VERSION 5.7 ;
NAMESCASESENSITIVE ON ;
BUSBITCHARS "[]" ;
DIVIDERCHAR "|" ;

PROPERTYDEFINITIONS
    LAYER LEF58_TYPE STRING ;
END PROPERTYDEFINITIONS


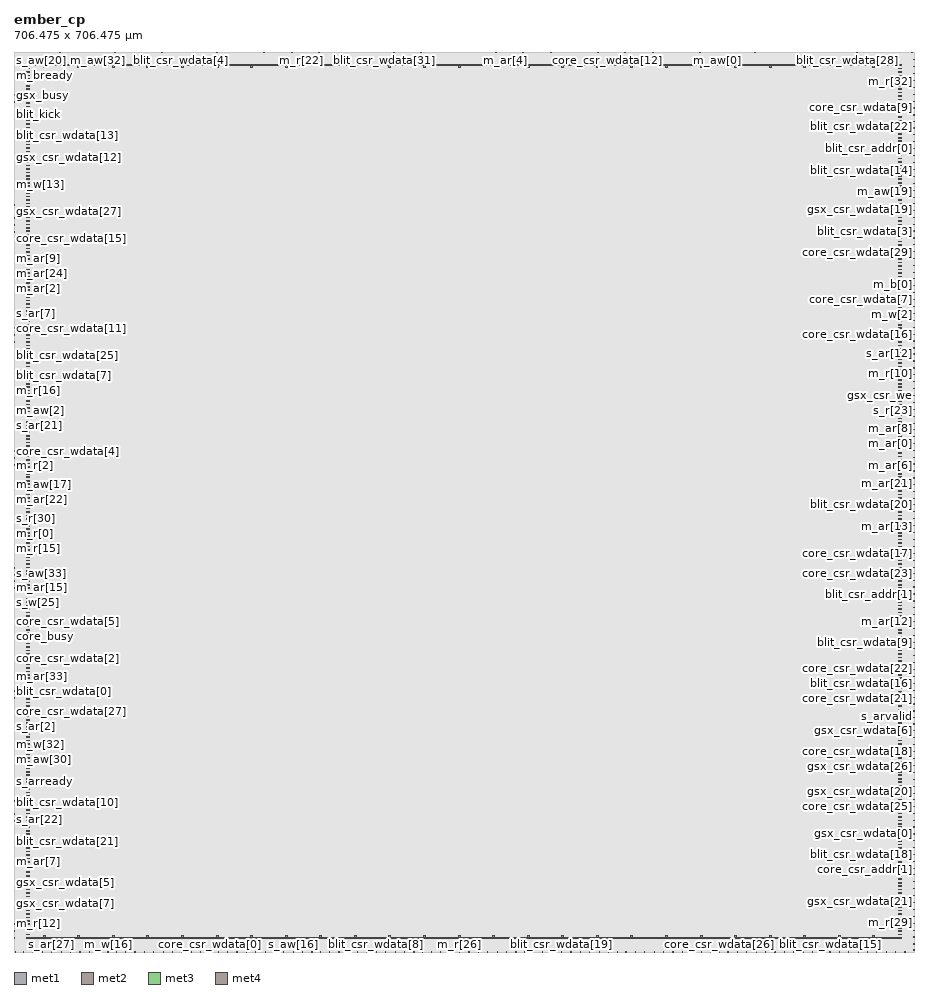
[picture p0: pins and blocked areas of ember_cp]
MACRO ember_cp
    CLASS BLOCK ;
    SIZE 706.475 BY 706.475 ;
    SYMMETRY Y ;
    PIN blit_busy
        DIRECTION INPUT ; 
        USE SIGNAL ; 
        PORT
            LAYER met1 ;
              RECT  705.88 420.34 706.475 420.48 ;
        END
    END blit_busy
    PIN blit_csr_addr[0]
        DIRECTION OUTPUT ; 
        USE SIGNAL ; 
        PORT
            LAYER met1 ;
              RECT  705.88 630.46 706.475 630.6 ;
        END
    END blit_csr_addr[0]
    PIN blit_csr_addr[1]
        DIRECTION OUTPUT ; 
        USE SIGNAL ; 
        PORT
            LAYER met1 ;
              RECT  705.88 280.94 706.475 281.08 ;
        END
    END blit_csr_addr[1]
    PIN blit_csr_wdata[0]
        DIRECTION OUTPUT ; 
        USE SIGNAL ; 
        PORT
            LAYER met1 ;
              RECT  0 204.78 0.595 204.92 ;
        END
    END blit_csr_wdata[0]
    PIN blit_csr_wdata[10]
        DIRECTION OUTPUT ; 
        USE SIGNAL ; 
        PORT
            LAYER met1 ;
              RECT  0 123.86 0.595 124 ;
        END
    END blit_csr_wdata[10]
    PIN blit_csr_wdata[11]
        DIRECTION OUTPUT ; 
        USE SIGNAL ; 
        PORT
            LAYER met2 ;
              RECT  28.68 705.99 28.82 706.475 ;
        END
    END blit_csr_wdata[11]
    PIN blit_csr_wdata[12]
        DIRECTION OUTPUT ; 
        USE SIGNAL ; 
        PORT
            LAYER met2 ;
              RECT  159.32 705.99 159.46 706.475 ;
        END
    END blit_csr_wdata[12]
    PIN blit_csr_wdata[13]
        DIRECTION OUTPUT ; 
        USE SIGNAL ; 
        PORT
            LAYER met1 ;
              RECT  0 640.66 0.595 640.8 ;
        END
    END blit_csr_wdata[13]
    PIN blit_csr_wdata[14]
        DIRECTION OUTPUT ; 
        USE SIGNAL ; 
        PORT
            LAYER met1 ;
              RECT  705.88 619.58 706.475 619.72 ;
        END
    END blit_csr_wdata[14]
    PIN blit_csr_wdata[15]
        DIRECTION OUTPUT ; 
        USE SIGNAL ; 
        PORT
            LAYER met2 ;
              RECT  640.48 0 640.62 0.485 ;
        END
    END blit_csr_wdata[15]
    PIN blit_csr_wdata[16]
        DIRECTION OUTPUT ; 
        USE SIGNAL ; 
        PORT
            LAYER met1 ;
              RECT  705.88 210.9 706.475 211.04 ;
        END
    END blit_csr_wdata[16]
    PIN blit_csr_wdata[17]
        DIRECTION OUTPUT ; 
        USE SIGNAL ; 
        PORT
            LAYER met2 ;
              RECT  626.68 0 626.82 0.485 ;
        END
    END blit_csr_wdata[17]
    PIN blit_csr_wdata[18]
        DIRECTION OUTPUT ; 
        USE SIGNAL ; 
        PORT
            LAYER met1 ;
              RECT  705.88 76.26 706.475 76.4 ;
        END
    END blit_csr_wdata[18]
    PIN blit_csr_wdata[19]
        DIRECTION OUTPUT ; 
        USE SIGNAL ; 
        PORT
            LAYER met2 ;
              RECT  429.8 0 429.94 0.485 ;
        END
    END blit_csr_wdata[19]
    PIN blit_csr_wdata[1]
        DIRECTION OUTPUT ; 
        USE SIGNAL ; 
        PORT
            LAYER met2 ;
              RECT  211.76 0 211.9 0.485 ;
        END
    END blit_csr_wdata[1]
    PIN blit_csr_wdata[20]
        DIRECTION OUTPUT ; 
        USE SIGNAL ; 
        PORT
            LAYER met1 ;
              RECT  705.88 350.98 706.475 351.12 ;
        END
    END blit_csr_wdata[20]
    PIN blit_csr_wdata[21]
        DIRECTION OUTPUT ; 
        USE SIGNAL ; 
        PORT
            LAYER met1 ;
              RECT  0 86.46 0.595 86.6 ;
        END
    END blit_csr_wdata[21]
    PIN blit_csr_wdata[22]
        DIRECTION OUTPUT ; 
        USE SIGNAL ; 
        PORT
            LAYER met1 ;
              RECT  705.88 641.34 706.475 641.48 ;
        END
    END blit_csr_wdata[22]
    PIN blit_csr_wdata[23]
        DIRECTION OUTPUT ; 
        USE SIGNAL ; 
        PORT
            LAYER met1 ;
              RECT  0 511.46 0.595 511.6 ;
        END
    END blit_csr_wdata[23]
    PIN blit_csr_wdata[24]
        DIRECTION OUTPUT ; 
        USE SIGNAL ; 
        PORT
            LAYER met1 ;
              RECT  705.88 608.7 706.475 608.84 ;
        END
    END blit_csr_wdata[24]
    PIN blit_csr_wdata[25]
        DIRECTION OUTPUT ; 
        USE SIGNAL ; 
        PORT
            LAYER met1 ;
              RECT  0 467.94 0.595 468.08 ;
        END
    END blit_csr_wdata[25]
    PIN blit_csr_wdata[26]
        DIRECTION OUTPUT ; 
        USE SIGNAL ; 
        PORT
            LAYER met2 ;
              RECT  51.68 0 51.82 0.485 ;
        END
    END blit_csr_wdata[26]
    PIN blit_csr_wdata[27]
        DIRECTION OUTPUT ; 
        USE SIGNAL ; 
        PORT
            LAYER met2 ;
              RECT  306.52 0 306.66 0.485 ;
        END
    END blit_csr_wdata[27]
    PIN blit_csr_wdata[28]
        DIRECTION OUTPUT ; 
        USE SIGNAL ; 
        PORT
            LAYER met2 ;
              RECT  654.28 705.99 654.42 706.475 ;
        END
    END blit_csr_wdata[28]
    PIN blit_csr_wdata[29]
        DIRECTION OUTPUT ; 
        USE SIGNAL ; 
        PORT
            LAYER met1 ;
              RECT  0 5.54 0.595 5.68 ;
        END
    END blit_csr_wdata[29]
    PIN blit_csr_wdata[2]
        DIRECTION OUTPUT ; 
        USE SIGNAL ; 
        PORT
            LAYER met1 ;
              RECT  705.88 700.5 706.475 700.64 ;
        END
    END blit_csr_wdata[2]
    PIN blit_csr_wdata[30]
        DIRECTION OUTPUT ; 
        USE SIGNAL ; 
        PORT
            LAYER met1 ;
              RECT  0 699.82 0.595 699.96 ;
        END
    END blit_csr_wdata[30]
    PIN blit_csr_wdata[31]
        DIRECTION OUTPUT ; 
        USE SIGNAL ; 
        PORT
            LAYER met2 ;
              RECT  290.88 705.99 291.02 706.475 ;
        END
    END blit_csr_wdata[31]
    PIN blit_csr_wdata[3]
        DIRECTION OUTPUT ; 
        USE SIGNAL ; 
        PORT
            LAYER met1 ;
              RECT  705.88 565.86 706.475 566 ;
        END
    END blit_csr_wdata[3]
    PIN blit_csr_wdata[4]
        DIRECTION OUTPUT ; 
        USE SIGNAL ; 
        PORT
            LAYER met2 ;
              RECT  130.8 705.99 130.94 706.475 ;
        END
    END blit_csr_wdata[4]
    PIN blit_csr_wdata[5]
        DIRECTION OUTPUT ; 
        USE SIGNAL ; 
        PORT
            LAYER met1 ;
              RECT  0 231.98 0.595 232.12 ;
        END
    END blit_csr_wdata[5]
    PIN blit_csr_wdata[6]
        DIRECTION OUTPUT ; 
        USE SIGNAL ; 
        PORT
            LAYER met1 ;
              RECT  0 167.38 0.595 167.52 ;
        END
    END blit_csr_wdata[6]
    PIN blit_csr_wdata[7]
        DIRECTION OUTPUT ; 
        USE SIGNAL ; 
        PORT
            LAYER met1 ;
              RECT  0 452.3 0.595 452.44 ;
        END
    END blit_csr_wdata[7]
    PIN blit_csr_wdata[8]
        DIRECTION OUTPUT ; 
        USE SIGNAL ; 
        PORT
            LAYER met2 ;
              RECT  284.44 0 284.58 0.485 ;
        END
    END blit_csr_wdata[8]
    PIN blit_csr_wdata[9]
        DIRECTION OUTPUT ; 
        USE SIGNAL ; 
        PORT
            LAYER met1 ;
              RECT  705.88 242.86 706.475 243 ;
        END
    END blit_csr_wdata[9]
    PIN blit_csr_we
        DIRECTION OUTPUT ; 
        USE SIGNAL ; 
        PORT
            LAYER met1 ;
              RECT  0 21.86 0.595 22 ;
        END
    END blit_csr_we
    PIN blit_kick
        DIRECTION OUTPUT ; 
        USE SIGNAL ; 
        PORT
            LAYER met1 ;
              RECT  0 650.86 0.595 651 ;
        END
    END blit_kick
    PIN clk
        DIRECTION INPUT ; 
        USE SIGNAL ; 
        PORT
            LAYER met2 ;
              RECT  611.96 0 612.1 0.485 ;
        END
    END clk
    PIN core_busy
        DIRECTION INPUT ; 
        USE SIGNAL ; 
        PORT
            LAYER met1 ;
              RECT  0 247.62 0.595 247.76 ;
        END
    END core_busy
    PIN core_csr_addr[0]
        DIRECTION OUTPUT ; 
        USE SIGNAL ; 
        PORT
            LAYER met2 ;
              RECT  364.48 0 364.62 0.485 ;
        END
    END core_csr_addr[0]
    PIN core_csr_addr[1]
        DIRECTION OUTPUT ; 
        USE SIGNAL ; 
        PORT
            LAYER met1 ;
              RECT  705.88 70.82 706.475 70.96 ;
        END
    END core_csr_addr[1]
    PIN core_csr_wdata[0]
        DIRECTION OUTPUT ; 
        USE SIGNAL ; 
        PORT
            LAYER met2 ;
              RECT  153.8 0 153.94 0.485 ;
        END
    END core_csr_wdata[0]
    PIN core_csr_wdata[10]
        DIRECTION OUTPUT ; 
        USE SIGNAL ; 
        PORT
            LAYER met2 ;
              RECT  124.36 0 124.5 0.485 ;
        END
    END core_csr_wdata[10]
    PIN core_csr_wdata[11]
        DIRECTION OUTPUT ; 
        USE SIGNAL ; 
        PORT
            LAYER met1 ;
              RECT  0 489.7 0.595 489.84 ;
        END
    END core_csr_wdata[11]
    PIN core_csr_wdata[12]
        DIRECTION OUTPUT ; 
        USE SIGNAL ; 
        PORT
            LAYER met2 ;
              RECT  465.68 705.99 465.82 706.475 ;
        END
    END core_csr_wdata[12]
    PIN core_csr_wdata[13]
        DIRECTION OUTPUT ; 
        USE SIGNAL ; 
        PORT
            LAYER met2 ;
              RECT  450.96 705.99 451.1 706.475 ;
        END
    END core_csr_wdata[13]
    PIN core_csr_wdata[14]
        DIRECTION OUTPUT ; 
        USE SIGNAL ; 
        PORT
            LAYER met1 ;
              RECT  0 457.74 0.595 457.88 ;
        END
    END core_csr_wdata[14]
    PIN core_csr_wdata[15]
        DIRECTION OUTPUT ; 
        USE SIGNAL ; 
        PORT
            LAYER met1 ;
              RECT  0 559.74 0.595 559.88 ;
        END
    END core_csr_wdata[15]
    PIN core_csr_wdata[16]
        DIRECTION OUTPUT ; 
        USE SIGNAL ; 
        PORT
            LAYER met1 ;
              RECT  705.88 484.94 706.475 485.08 ;
        END
    END core_csr_wdata[16]
    PIN core_csr_wdata[17]
        DIRECTION OUTPUT ; 
        USE SIGNAL ; 
        PORT
            LAYER met1 ;
              RECT  705.88 312.9 706.475 313.04 ;
        END
    END core_csr_wdata[17]
    PIN core_csr_wdata[18]
        DIRECTION OUTPUT ; 
        USE SIGNAL ; 
        PORT
            LAYER met1 ;
              RECT  705.88 157.18 706.475 157.32 ;
        END
    END core_csr_wdata[18]
    PIN core_csr_wdata[19]
        DIRECTION OUTPUT ; 
        USE SIGNAL ; 
        PORT
            LAYER met2 ;
              RECT  117 0 117.14 0.485 ;
        END
    END core_csr_wdata[19]
    PIN core_csr_wdata[1]
        DIRECTION OUTPUT ; 
        USE SIGNAL ; 
        PORT
            LAYER met2 ;
              RECT  232 705.99 232.14 706.475 ;
        END
    END core_csr_wdata[1]
    PIN core_csr_wdata[20]
        DIRECTION OUTPUT ; 
        USE SIGNAL ; 
        PORT
            LAYER met1 ;
              RECT  0 661.74 0.595 661.88 ;
        END
    END core_csr_wdata[20]
    PIN core_csr_wdata[21]
        DIRECTION OUTPUT ; 
        USE SIGNAL ; 
        PORT
            LAYER met1 ;
              RECT  705.88 205.46 706.475 205.6 ;
        END
    END core_csr_wdata[21]
    PIN core_csr_wdata[22]
        DIRECTION OUTPUT ; 
        USE SIGNAL ; 
        PORT
            LAYER met1 ;
              RECT  705.88 216.34 706.475 216.48 ;
        END
    END core_csr_wdata[22]
    PIN core_csr_wdata[23]
        DIRECTION OUTPUT ; 
        USE SIGNAL ; 
        PORT
            LAYER met1 ;
              RECT  705.88 297.26 706.475 297.4 ;
        END
    END core_csr_wdata[23]
    PIN core_csr_wdata[24]
        DIRECTION OUTPUT ; 
        USE SIGNAL ; 
        PORT
            LAYER met1 ;
              RECT  705.88 1.46 706.475 1.6 ;
        END
    END core_csr_wdata[24]
    PIN core_csr_wdata[25]
        DIRECTION OUTPUT ; 
        USE SIGNAL ; 
        PORT
            LAYER met1 ;
              RECT  705.88 114.34 706.475 114.48 ;
        END
    END core_csr_wdata[25]
    PIN core_csr_wdata[26]
        DIRECTION OUTPUT ; 
        USE SIGNAL ; 
        PORT
            LAYER met2 ;
              RECT  554 0 554.14 0.485 ;
        END
    END core_csr_wdata[26]
    PIN core_csr_wdata[27]
        DIRECTION OUTPUT ; 
        USE SIGNAL ; 
        PORT
            LAYER met1 ;
              RECT  0 188.46 0.595 188.6 ;
        END
    END core_csr_wdata[27]
    PIN core_csr_wdata[28]
        DIRECTION OUTPUT ; 
        USE SIGNAL ; 
        PORT
            LAYER met2 ;
              RECT  102.28 0 102.42 0.485 ;
        END
    END core_csr_wdata[28]
    PIN core_csr_wdata[29]
        DIRECTION OUTPUT ; 
        USE SIGNAL ; 
        PORT
            LAYER met1 ;
              RECT  705.88 554.98 706.475 555.12 ;
        END
    END core_csr_wdata[29]
    PIN core_csr_wdata[2]
        DIRECTION OUTPUT ; 
        USE SIGNAL ; 
        PORT
            LAYER met1 ;
              RECT  0 236.74 0.595 236.88 ;
        END
    END core_csr_wdata[2]
    PIN core_csr_wdata[30]
        DIRECTION OUTPUT ; 
        USE SIGNAL ; 
        PORT
            LAYER met2 ;
              RECT  319.4 705.99 319.54 706.475 ;
        END
    END core_csr_wdata[30]
    PIN core_csr_wdata[31]
        DIRECTION OUTPUT ; 
        USE SIGNAL ; 
        PORT
            LAYER met1 ;
              RECT  705.88 189.14 706.475 189.28 ;
        END
    END core_csr_wdata[31]
    PIN core_csr_wdata[3]
        DIRECTION OUTPUT ; 
        USE SIGNAL ; 
        PORT
            LAYER met1 ;
              RECT  0 10.98 0.595 11.12 ;
        END
    END core_csr_wdata[3]
    PIN core_csr_wdata[4]
        DIRECTION OUTPUT ; 
        USE SIGNAL ; 
        PORT
            LAYER met1 ;
              RECT  0 393.14 0.595 393.28 ;
        END
    END core_csr_wdata[4]
    PIN core_csr_wdata[5]
        DIRECTION OUTPUT ; 
        USE SIGNAL ; 
        PORT
            LAYER met1 ;
              RECT  0 253.06 0.595 253.2 ;
        END
    END core_csr_wdata[5]
    PIN core_csr_wdata[6]
        DIRECTION OUTPUT ; 
        USE SIGNAL ; 
        PORT
            LAYER met2 ;
              RECT  277.08 0 277.22 0.485 ;
        END
    END core_csr_wdata[6]
    PIN core_csr_wdata[7]
        DIRECTION OUTPUT ; 
        USE SIGNAL ; 
        PORT
            LAYER met1 ;
              RECT  705.88 512.14 706.475 512.28 ;
        END
    END core_csr_wdata[7]
    PIN core_csr_wdata[8]
        DIRECTION OUTPUT ; 
        USE SIGNAL ; 
        PORT
            LAYER met2 ;
              RECT  639.56 705.99 639.7 706.475 ;
        END
    END core_csr_wdata[8]
    PIN core_csr_wdata[9]
        DIRECTION OUTPUT ; 
        USE SIGNAL ; 
        PORT
            LAYER met1 ;
              RECT  705.88 656.98 706.475 657.12 ;
        END
    END core_csr_wdata[9]
    PIN core_csr_we
        DIRECTION OUTPUT ; 
        USE SIGNAL ; 
        PORT
            LAYER met2 ;
              RECT  596.32 705.99 596.46 706.475 ;
        END
    END core_csr_we
    PIN core_kick
        DIRECTION OUTPUT ; 
        USE SIGNAL ; 
        PORT
            LAYER met1 ;
              RECT  705.88 227.22 706.475 227.36 ;
        END
    END core_kick
    PIN gsx_busy
        DIRECTION INPUT ; 
        USE SIGNAL ; 
        PORT
            LAYER met1 ;
              RECT  0 672.62 0.595 672.76 ;
        END
    END gsx_busy
    PIN gsx_csr_addr[0]
        DIRECTION OUTPUT ; 
        USE SIGNAL ; 
        PORT
            LAYER met2 ;
              RECT  379.2 0 379.34 0.485 ;
        END
    END gsx_csr_addr[0]
    PIN gsx_csr_addr[1]
        DIRECTION OUTPUT ; 
        USE SIGNAL ; 
        PORT
            LAYER met1 ;
              RECT  705.88 60.62 706.475 60.76 ;
        END
    END gsx_csr_addr[1]
    PIN gsx_csr_wdata[0]
        DIRECTION OUTPUT ; 
        USE SIGNAL ; 
        PORT
            LAYER met1 ;
              RECT  705.88 92.58 706.475 92.72 ;
        END
    END gsx_csr_wdata[0]
    PIN gsx_csr_wdata[10]
        DIRECTION OUTPUT ; 
        USE SIGNAL ; 
        PORT
            LAYER met2 ;
              RECT  22.24 0 22.38 0.485 ;
        END
    END gsx_csr_wdata[10]
    PIN gsx_csr_wdata[11]
        DIRECTION OUTPUT ; 
        USE SIGNAL ; 
        PORT
            LAYER met1 ;
              RECT  0 172.82 0.595 172.96 ;
        END
    END gsx_csr_wdata[11]
    PIN gsx_csr_wdata[12]
        DIRECTION OUTPUT ; 
        USE SIGNAL ; 
        PORT
            LAYER met1 ;
              RECT  0 629.78 0.595 629.92 ;
        END
    END gsx_csr_wdata[12]
    PIN gsx_csr_wdata[13]
        DIRECTION OUTPUT ; 
        USE SIGNAL ; 
        PORT
            LAYER met2 ;
              RECT  574.24 705.99 574.38 706.475 ;
        END
    END gsx_csr_wdata[13]
    PIN gsx_csr_wdata[14]
        DIRECTION OUTPUT ; 
        USE SIGNAL ; 
        PORT
            LAYER met2 ;
              RECT  312.04 705.99 312.18 706.475 ;
        END
    END gsx_csr_wdata[14]
    PIN gsx_csr_wdata[15]
        DIRECTION OUTPUT ; 
        USE SIGNAL ; 
        PORT
            LAYER met2 ;
              RECT  669 705.99 669.14 706.475 ;
        END
    END gsx_csr_wdata[15]
    PIN gsx_csr_wdata[16]
        DIRECTION OUTPUT ; 
        USE SIGNAL ; 
        PORT
            LAYER met2 ;
              RECT  422.44 0 422.58 0.485 ;
        END
    END gsx_csr_wdata[16]
    PIN gsx_csr_wdata[17]
        DIRECTION OUTPUT ; 
        USE SIGNAL ; 
        PORT
            LAYER met1 ;
              RECT  0 226.54 0.595 226.68 ;
        END
    END gsx_csr_wdata[17]
    PIN gsx_csr_wdata[18]
        DIRECTION OUTPUT ; 
        USE SIGNAL ; 
        PORT
            LAYER met2 ;
              RECT  181.4 705.99 181.54 706.475 ;
        END
    END gsx_csr_wdata[18]
    PIN gsx_csr_wdata[19]
        DIRECTION OUTPUT ; 
        USE SIGNAL ; 
        PORT
            LAYER met1 ;
              RECT  705.88 576.74 706.475 576.88 ;
        END
    END gsx_csr_wdata[19]
    PIN gsx_csr_wdata[1]
        DIRECTION OUTPUT ; 
        USE SIGNAL ; 
        PORT
            LAYER met2 ;
              RECT  196.12 705.99 196.26 706.475 ;
        END
    END gsx_csr_wdata[1]
    PIN gsx_csr_wdata[20]
        DIRECTION OUTPUT ; 
        USE SIGNAL ; 
        PORT
            LAYER met1 ;
              RECT  705.88 119.78 706.475 119.92 ;
        END
    END gsx_csr_wdata[20]
    PIN gsx_csr_wdata[21]
        DIRECTION OUTPUT ; 
        USE SIGNAL ; 
        PORT
            LAYER met1 ;
              RECT  705.88 33.42 706.475 33.56 ;
        END
    END gsx_csr_wdata[21]
    PIN gsx_csr_wdata[22]
        DIRECTION OUTPUT ; 
        USE SIGNAL ; 
        PORT
            LAYER met2 ;
              RECT  400.36 0 400.5 0.485 ;
        END
    END gsx_csr_wdata[22]
    PIN gsx_csr_wdata[23]
        DIRECTION OUTPUT ; 
        USE SIGNAL ; 
        PORT
            LAYER met1 ;
              RECT  705.88 614.14 706.475 614.28 ;
        END
    END gsx_csr_wdata[23]
    PIN gsx_csr_wdata[24]
        DIRECTION OUTPUT ; 
        USE SIGNAL ; 
        PORT
            LAYER met1 ;
              RECT  705.88 323.78 706.475 323.92 ;
        END
    END gsx_csr_wdata[24]
    PIN gsx_csr_wdata[25]
        DIRECTION OUTPUT ; 
        USE SIGNAL ; 
        PORT
            LAYER met2 ;
              RECT  72.84 705.99 72.98 706.475 ;
        END
    END gsx_csr_wdata[25]
    PIN gsx_csr_wdata[26]
        DIRECTION OUTPUT ; 
        USE SIGNAL ; 
        PORT
            LAYER met1 ;
              RECT  705.88 151.74 706.475 151.88 ;
        END
    END gsx_csr_wdata[26]
    PIN gsx_csr_wdata[27]
        DIRECTION OUTPUT ; 
        USE SIGNAL ; 
        PORT
            LAYER met1 ;
              RECT  0 581.5 0.595 581.64 ;
        END
    END gsx_csr_wdata[27]
    PIN gsx_csr_wdata[28]
        DIRECTION OUTPUT ; 
        USE SIGNAL ; 
        PORT
            LAYER met1 ;
              RECT  0 586.26 0.595 586.4 ;
        END
    END gsx_csr_wdata[28]
    PIN gsx_csr_wdata[29]
        DIRECTION OUTPUT ; 
        USE SIGNAL ; 
        PORT
            LAYER met1 ;
              RECT  705.88 98.02 706.475 98.16 ;
        END
    END gsx_csr_wdata[29]
    PIN gsx_csr_wdata[2]
        DIRECTION OUTPUT ; 
        USE SIGNAL ; 
        PORT
            LAYER met2 ;
              RECT  356.2 705.99 356.34 706.475 ;
        END
    END gsx_csr_wdata[2]
    PIN gsx_csr_wdata[30]
        DIRECTION OUTPUT ; 
        USE SIGNAL ; 
        PORT
            LAYER met2 ;
              RECT  94.92 0 95.06 0.485 ;
        END
    END gsx_csr_wdata[30]
    PIN gsx_csr_wdata[31]
        DIRECTION OUTPUT ; 
        USE SIGNAL ; 
        PORT
            LAYER met1 ;
              RECT  705.88 140.86 706.475 141 ;
        END
    END gsx_csr_wdata[31]
    PIN gsx_csr_wdata[3]
        DIRECTION OUTPUT ; 
        USE SIGNAL ; 
        PORT
            LAYER met2 ;
              RECT  79.28 705.99 79.42 706.475 ;
        END
    END gsx_csr_wdata[3]
    PIN gsx_csr_wdata[4]
        DIRECTION OUTPUT ; 
        USE SIGNAL ; 
        PORT
            LAYER met1 ;
              RECT  0 118.42 0.595 118.56 ;
        END
    END gsx_csr_wdata[4]
    PIN gsx_csr_wdata[5]
        DIRECTION OUTPUT ; 
        USE SIGNAL ; 
        PORT
            LAYER met1 ;
              RECT  0 54.5 0.595 54.64 ;
        END
    END gsx_csr_wdata[5]
    PIN gsx_csr_wdata[6]
        DIRECTION OUTPUT ; 
        USE SIGNAL ; 
        PORT
            LAYER met1 ;
              RECT  705.88 173.5 706.475 173.64 ;
        END
    END gsx_csr_wdata[6]
    PIN gsx_csr_wdata[7]
        DIRECTION OUTPUT ; 
        USE SIGNAL ; 
        PORT
            LAYER met1 ;
              RECT  0 38.18 0.595 38.32 ;
        END
    END gsx_csr_wdata[7]
    PIN gsx_csr_wdata[8]
        DIRECTION OUTPUT ; 
        USE SIGNAL ; 
        PORT
            LAYER met1 ;
              RECT  0 161.94 0.595 162.08 ;
        END
    END gsx_csr_wdata[8]
    PIN gsx_csr_wdata[9]
        DIRECTION OUTPUT ; 
        USE SIGNAL ; 
        PORT
            LAYER met1 ;
              RECT  0 59.26 0.595 59.4 ;
        END
    END gsx_csr_wdata[9]
    PIN gsx_csr_we
        DIRECTION OUTPUT ; 
        USE SIGNAL ; 
        PORT
            LAYER met1 ;
              RECT  705.88 436.66 706.475 436.8 ;
        END
    END gsx_csr_we
    PIN gsx_kick
        DIRECTION OUTPUT ; 
        USE SIGNAL ; 
        PORT
            LAYER met2 ;
              RECT  246.72 705.99 246.86 706.475 ;
        END
    END gsx_kick
    PIN m_ar[0]
        DIRECTION OUTPUT ; 
        USE SIGNAL ; 
        PORT
            LAYER met1 ;
              RECT  705.88 399.26 706.475 399.4 ;
        END
    END m_ar[0]
    PIN m_ar[10]
        DIRECTION OUTPUT ; 
        USE SIGNAL ; 
        PORT
            LAYER met2 ;
              RECT  255 0 255.14 0.485 ;
        END
    END m_ar[10]
    PIN m_ar[11]
        DIRECTION OUTPUT ; 
        USE SIGNAL ; 
        PORT
            LAYER met2 ;
              RECT  523.64 705.99 523.78 706.475 ;
        END
    END m_ar[11]
    PIN m_ar[12]
        DIRECTION OUTPUT ; 
        USE SIGNAL ; 
        PORT
            LAYER met1 ;
              RECT  705.88 259.18 706.475 259.32 ;
        END
    END m_ar[12]
    PIN m_ar[13]
        DIRECTION OUTPUT ; 
        USE SIGNAL ; 
        PORT
            LAYER met1 ;
              RECT  705.88 340.1 706.475 340.24 ;
        END
    END m_ar[13]
    PIN m_ar[14]
        DIRECTION OUTPUT ; 
        USE SIGNAL ; 
        PORT
            LAYER met2 ;
              RECT  145.52 705.99 145.66 706.475 ;
        END
    END m_ar[14]
    PIN m_ar[15]
        DIRECTION OUTPUT ; 
        USE SIGNAL ; 
        PORT
            LAYER met1 ;
              RECT  0 285.7 0.595 285.84 ;
        END
    END m_ar[15]
    PIN m_ar[16]
        DIRECTION OUTPUT ; 
        USE SIGNAL ; 
        PORT
            LAYER met2 ;
              RECT  174.04 705.99 174.18 706.475 ;
        END
    END m_ar[16]
    PIN m_ar[17]
        DIRECTION OUTPUT ; 
        USE SIGNAL ; 
        PORT
            LAYER met1 ;
              RECT  705.88 38.86 706.475 39 ;
        END
    END m_ar[17]
    PIN m_ar[18]
        DIRECTION OUTPUT ; 
        USE SIGNAL ; 
        PORT
            LAYER met1 ;
              RECT  0 269.38 0.595 269.52 ;
        END
    END m_ar[18]
    PIN m_ar[19]
        DIRECTION OUTPUT ; 
        USE SIGNAL ; 
        PORT
            LAYER met1 ;
              RECT  705.88 6.22 706.475 6.36 ;
        END
    END m_ar[19]
    PIN m_ar[1]
        DIRECTION OUTPUT ; 
        USE SIGNAL ; 
        PORT
            LAYER met1 ;
              RECT  0 306.78 0.595 306.92 ;
        END
    END m_ar[1]
    PIN m_ar[20]
        DIRECTION OUTPUT ; 
        USE SIGNAL ; 
        PORT
            LAYER met2 ;
              RECT  625.76 705.99 625.9 706.475 ;
        END
    END m_ar[20]
    PIN m_ar[21]
        DIRECTION OUTPUT ; 
        USE SIGNAL ; 
        PORT
            LAYER met1 ;
              RECT  705.88 361.18 706.475 361.32 ;
        END
    END m_ar[21]
    PIN m_ar[22]
        DIRECTION OUTPUT ; 
        USE SIGNAL ; 
        PORT
            LAYER met1 ;
              RECT  0 355.06 0.595 355.2 ;
        END
    END m_ar[22]
    PIN m_ar[23]
        DIRECTION OUTPUT ; 
        USE SIGNAL ; 
        PORT
            LAYER met2 ;
              RECT  218.2 705.99 218.34 706.475 ;
        END
    END m_ar[23]
    PIN m_ar[24]
        DIRECTION OUTPUT ; 
        USE SIGNAL ; 
        PORT
            LAYER met1 ;
              RECT  0 532.54 0.595 532.68 ;
        END
    END m_ar[24]
    PIN m_ar[25]
        DIRECTION OUTPUT ; 
        USE SIGNAL ; 
        PORT
            LAYER met2 ;
              RECT  399.44 705.99 399.58 706.475 ;
        END
    END m_ar[25]
    PIN m_ar[26]
        DIRECTION OUTPUT ; 
        USE SIGNAL ; 
        PORT
            LAYER met1 ;
              RECT  705.88 334.66 706.475 334.8 ;
        END
    END m_ar[26]
    PIN m_ar[27]
        DIRECTION OUTPUT ; 
        USE SIGNAL ; 
        PORT
            LAYER met1 ;
              RECT  705.88 11.66 706.475 11.8 ;
        END
    END m_ar[27]
    PIN m_ar[28]
        DIRECTION OUTPUT ; 
        USE SIGNAL ; 
        PORT
            LAYER met1 ;
              RECT  0 635.22 0.595 635.36 ;
        END
    END m_ar[28]
    PIN m_ar[29]
        DIRECTION OUTPUT ; 
        USE SIGNAL ; 
        PORT
            LAYER met2 ;
              RECT  479.48 705.99 479.62 706.475 ;
        END
    END m_ar[29]
    PIN m_ar[2]
        DIRECTION OUTPUT ; 
        USE SIGNAL ; 
        PORT
            LAYER met1 ;
              RECT  0 527.1 0.595 527.24 ;
        END
    END m_ar[2]
    PIN m_ar[30]
        DIRECTION OUTPUT ; 
        USE SIGNAL ; 
        PORT
            LAYER met2 ;
              RECT  305.6 705.99 305.74 706.475 ;
        END
    END m_ar[30]
    PIN m_ar[31]
        DIRECTION OUTPUT ; 
        USE SIGNAL ; 
        PORT
            LAYER met1 ;
              RECT  0 350.3 0.595 350.44 ;
        END
    END m_ar[31]
    PIN m_ar[32]
        DIRECTION OUTPUT ; 
        USE SIGNAL ; 
        PORT
            LAYER met1 ;
              RECT  705.88 501.26 706.475 501.4 ;
        END
    END m_ar[32]
    PIN m_ar[33]
        DIRECTION OUTPUT ; 
        USE SIGNAL ; 
        PORT
            LAYER met1 ;
              RECT  0 210.22 0.595 210.36 ;
        END
    END m_ar[33]
    PIN m_ar[34]
        DIRECTION OUTPUT ; 
        USE SIGNAL ; 
        PORT
            LAYER met2 ;
              RECT  619.32 0 619.46 0.485 ;
        END
    END m_ar[34]
    PIN m_ar[3]
        DIRECTION OUTPUT ; 
        USE SIGNAL ; 
        PORT
            LAYER met2 ;
              RECT  116.08 705.99 116.22 706.475 ;
        END
    END m_ar[3]
    PIN m_ar[4]
        DIRECTION OUTPUT ; 
        USE SIGNAL ; 
        PORT
            LAYER met2 ;
              RECT  385.64 705.99 385.78 706.475 ;
        END
    END m_ar[4]
    PIN m_ar[5]
        DIRECTION OUTPUT ; 
        USE SIGNAL ; 
        PORT
            LAYER met2 ;
              RECT  138.16 705.99 138.3 706.475 ;
        END
    END m_ar[5]
    PIN m_ar[6]
        DIRECTION OUTPUT ; 
        USE SIGNAL ; 
        PORT
            LAYER met1 ;
              RECT  705.88 388.38 706.475 388.52 ;
        END
    END m_ar[6]
    PIN m_ar[7]
        DIRECTION OUTPUT ; 
        USE SIGNAL ; 
        PORT
            LAYER met1 ;
              RECT  0 64.7 0.595 64.84 ;
        END
    END m_ar[7]
    PIN m_ar[8]
        DIRECTION OUTPUT ; 
        USE SIGNAL ; 
        PORT
            LAYER met1 ;
              RECT  705.88 404.7 706.475 404.84 ;
        END
    END m_ar[8]
    PIN m_ar[9]
        DIRECTION OUTPUT ; 
        USE SIGNAL ; 
        PORT
            LAYER met1 ;
              RECT  0 537.98 0.595 538.12 ;
        END
    END m_ar[9]
    PIN m_arready
        DIRECTION INPUT ; 
        USE SIGNAL ; 
        PORT
            LAYER met2 ;
              RECT  473.96 0 474.1 0.485 ;
        END
    END m_arready
    PIN m_arvalid
        DIRECTION OUTPUT ; 
        USE SIGNAL ; 
        PORT
            LAYER met2 ;
              RECT  531.92 0 532.06 0.485 ;
        END
    END m_arvalid
    PIN m_aw[0]
        DIRECTION OUTPUT ; 
        USE SIGNAL ; 
        PORT
            LAYER met2 ;
              RECT  552.16 705.99 552.3 706.475 ;
        END
    END m_aw[0]
    PIN m_aw[10]
        DIRECTION OUTPUT ; 
        USE SIGNAL ; 
        PORT
            LAYER met1 ;
              RECT  705.88 684.18 706.475 684.32 ;
        END
    END m_aw[10]
    PIN m_aw[11]
        DIRECTION OUTPUT ; 
        USE SIGNAL ; 
        PORT
            LAYER met2 ;
              RECT  21.32 705.99 21.46 706.475 ;
        END
    END m_aw[11]
    PIN m_aw[12]
        DIRECTION OUTPUT ; 
        USE SIGNAL ; 
        PORT
            LAYER met2 ;
              RECT  291.8 0 291.94 0.485 ;
        END
    END m_aw[12]
    PIN m_aw[13]
        DIRECTION OUTPUT ; 
        USE SIGNAL ; 
        PORT
            LAYER met2 ;
              RECT  437.16 0 437.3 0.485 ;
        END
    END m_aw[13]
    PIN m_aw[14]
        DIRECTION OUTPUT ; 
        USE SIGNAL ; 
        PORT
            LAYER met2 ;
              RECT  226.48 0 226.62 0.485 ;
        END
    END m_aw[14]
    PIN m_aw[15]
        DIRECTION OUTPUT ; 
        USE SIGNAL ; 
        PORT
            LAYER met1 ;
              RECT  0 624.34 0.595 624.48 ;
        END
    END m_aw[15]
    PIN m_aw[16]
        DIRECTION OUTPUT ; 
        USE SIGNAL ; 
        PORT
            LAYER met2 ;
              RECT  335.04 0 335.18 0.485 ;
        END
    END m_aw[16]
    PIN m_aw[17]
        DIRECTION OUTPUT ; 
        USE SIGNAL ; 
        PORT
            LAYER met1 ;
              RECT  0 360.5 0.595 360.64 ;
        END
    END m_aw[17]
    PIN m_aw[18]
        DIRECTION OUTPUT ; 
        USE SIGNAL ; 
        PORT
            LAYER met2 ;
              RECT  501.56 705.99 501.7 706.475 ;
        END
    END m_aw[18]
    PIN m_aw[19]
        DIRECTION OUTPUT ; 
        USE SIGNAL ; 
        PORT
            LAYER met1 ;
              RECT  705.88 603.26 706.475 603.4 ;
        END
    END m_aw[19]
    PIN m_aw[1]
        DIRECTION OUTPUT ; 
        USE SIGNAL ; 
        PORT
            LAYER met1 ;
              RECT  705.88 194.58 706.475 194.72 ;
        END
    END m_aw[1]
    PIN m_aw[20]
        DIRECTION OUTPUT ; 
        USE SIGNAL ; 
        PORT
            LAYER met2 ;
              RECT  313.88 0 314.02 0.485 ;
        END
    END m_aw[20]
    PIN m_aw[21]
        DIRECTION OUTPUT ; 
        USE SIGNAL ; 
        PORT
            LAYER met2 ;
              RECT  684.64 0 684.78 0.485 ;
        END
    END m_aw[21]
    PIN m_aw[22]
        DIRECTION OUTPUT ; 
        USE SIGNAL ; 
        PORT
            LAYER met2 ;
              RECT  589.88 0 590.02 0.485 ;
        END
    END m_aw[22]
    PIN m_aw[23]
        DIRECTION OUTPUT ; 
        USE SIGNAL ; 
        PORT
            LAYER met1 ;
              RECT  705.88 44.3 706.475 44.44 ;
        END
    END m_aw[23]
    PIN m_aw[24]
        DIRECTION OUTPUT ; 
        USE SIGNAL ; 
        PORT
            LAYER met1 ;
              RECT  705.88 22.54 706.475 22.68 ;
        END
    END m_aw[24]
    PIN m_aw[25]
        DIRECTION OUTPUT ; 
        USE SIGNAL ; 
        PORT
            LAYER met2 ;
              RECT  233.84 0 233.98 0.485 ;
        END
    END m_aw[25]
    PIN m_aw[26]
        DIRECTION OUTPUT ; 
        USE SIGNAL ; 
        PORT
            LAYER met2 ;
              RECT  101.36 705.99 101.5 706.475 ;
        END
    END m_aw[26]
    PIN m_aw[27]
        DIRECTION OUTPUT ; 
        USE SIGNAL ; 
        PORT
            LAYER met2 ;
              RECT  581.6 705.99 581.74 706.475 ;
        END
    END m_aw[27]
    PIN m_aw[28]
        DIRECTION OUTPUT ; 
        USE SIGNAL ; 
        PORT
            LAYER met2 ;
              RECT  334.12 705.99 334.26 706.475 ;
        END
    END m_aw[28]
    PIN m_aw[29]
        DIRECTION OUTPUT ; 
        USE SIGNAL ; 
        PORT
            LAYER met2 ;
              RECT  517.2 0 517.34 0.485 ;
        END
    END m_aw[29]
    PIN m_aw[2]
        DIRECTION OUTPUT ; 
        USE SIGNAL ; 
        PORT
            LAYER met1 ;
              RECT  0 425.1 0.595 425.24 ;
        END
    END m_aw[2]
    PIN m_aw[30]
        DIRECTION OUTPUT ; 
        USE SIGNAL ; 
        PORT
            LAYER met1 ;
              RECT  0 151.06 0.595 151.2 ;
        END
    END m_aw[30]
    PIN m_aw[31]
        DIRECTION OUTPUT ; 
        USE SIGNAL ; 
        PORT
            LAYER met1 ;
              RECT  0 408.78 0.595 408.92 ;
        END
    END m_aw[31]
    PIN m_aw[32]
        DIRECTION OUTPUT ; 
        USE SIGNAL ; 
        PORT
            LAYER met2 ;
              RECT  65.48 705.99 65.62 706.475 ;
        END
    END m_aw[32]
    PIN m_aw[33]
        DIRECTION OUTPUT ; 
        USE SIGNAL ; 
        PORT
            LAYER met2 ;
              RECT  342.4 0 342.54 0.485 ;
        END
    END m_aw[33]
    PIN m_aw[34]
        DIRECTION OUTPUT ; 
        USE SIGNAL ; 
        PORT
            LAYER met2 ;
              RECT  407.72 0 407.86 0.485 ;
        END
    END m_aw[34]
    PIN m_aw[3]
        DIRECTION OUTPUT ; 
        USE SIGNAL ; 
        PORT
            LAYER met1 ;
              RECT  705.88 695.06 706.475 695.2 ;
        END
    END m_aw[3]
    PIN m_aw[4]
        DIRECTION OUTPUT ; 
        USE SIGNAL ; 
        PORT
            LAYER met1 ;
              RECT  705.88 625.02 706.475 625.16 ;
        END
    END m_aw[4]
    PIN m_aw[5]
        DIRECTION OUTPUT ; 
        USE SIGNAL ; 
        PORT
            LAYER met1 ;
              RECT  0 221.1 0.595 221.24 ;
        END
    END m_aw[5]
    PIN m_aw[6]
        DIRECTION OUTPUT ; 
        USE SIGNAL ; 
        PORT
            LAYER met1 ;
              RECT  0 516.9 0.595 517.04 ;
        END
    END m_aw[6]
    PIN m_aw[7]
        DIRECTION OUTPUT ; 
        USE SIGNAL ; 
        PORT
            LAYER met2 ;
              RECT  283.52 705.99 283.66 706.475 ;
        END
    END m_aw[7]
    PIN m_aw[8]
        DIRECTION OUTPUT ; 
        USE SIGNAL ; 
        PORT
            LAYER met2 ;
              RECT  189.68 0 189.82 0.485 ;
        END
    END m_aw[8]
    PIN m_aw[9]
        DIRECTION OUTPUT ; 
        USE SIGNAL ; 
        PORT
            LAYER met1 ;
              RECT  705.88 414.9 706.475 415.04 ;
        END
    END m_aw[9]
    PIN m_awready
        DIRECTION INPUT ; 
        USE SIGNAL ; 
        PORT
            LAYER met2 ;
              RECT  509.84 0 509.98 0.485 ;
        END
    END m_awready
    PIN m_awvalid
        DIRECTION OUTPUT ; 
        USE SIGNAL ; 
        PORT
            LAYER met1 ;
              RECT  0 683.5 0.595 683.64 ;
        END
    END m_awvalid
    PIN m_b[0]
        DIRECTION INPUT ; 
        USE SIGNAL ; 
        PORT
            LAYER met1 ;
              RECT  705.88 517.58 706.475 517.72 ;
        END
    END m_b[0]
    PIN m_b[1]
        DIRECTION INPUT ; 
        USE SIGNAL ; 
        PORT
            LAYER met2 ;
              RECT  632.2 705.99 632.34 706.475 ;
        END
    END m_b[1]
    PIN m_bready
        DIRECTION OUTPUT ; 
        USE SIGNAL ; 
        PORT
            LAYER met1 ;
              RECT  0 694.38 0.595 694.52 ;
        END
    END m_bready
    PIN m_bvalid
        DIRECTION INPUT ; 
        USE SIGNAL ; 
        PORT
            LAYER met2 ;
              RECT  299.16 0 299.3 0.485 ;
        END
    END m_bvalid
    PIN m_r[0]
        DIRECTION INPUT ; 
        USE SIGNAL ; 
        PORT
            LAYER met1 ;
              RECT  0 328.54 0.595 328.68 ;
        END
    END m_r[0]
    PIN m_r[10]
        DIRECTION INPUT ; 
        USE SIGNAL ; 
        PORT
            LAYER met1 ;
              RECT  705.88 447.54 706.475 447.68 ;
        END
    END m_r[10]
    PIN m_r[11]
        DIRECTION INPUT ; 
        USE SIGNAL ; 
        PORT
            LAYER met1 ;
              RECT  705.88 27.98 706.475 28.12 ;
        END
    END m_r[11]
    PIN m_r[12]
        DIRECTION INPUT ; 
        USE SIGNAL ; 
        PORT
            LAYER met1 ;
              RECT  0 16.42 0.595 16.56 ;
        END
    END m_r[12]
    PIN m_r[13]
        DIRECTION INPUT ; 
        USE SIGNAL ; 
        PORT
            LAYER met2 ;
              RECT  43.4 705.99 43.54 706.475 ;
        END
    END m_r[13]
    PIN m_r[14]
        DIRECTION INPUT ; 
        USE SIGNAL ; 
        PORT
            LAYER met2 ;
              RECT  691.08 705.99 691.22 706.475 ;
        END
    END m_r[14]
    PIN m_r[15]
        DIRECTION INPUT ; 
        USE SIGNAL ; 
        PORT
            LAYER met1 ;
              RECT  0 323.1 0.595 323.24 ;
        END
    END m_r[15]
    PIN m_r[16]
        DIRECTION INPUT ; 
        USE SIGNAL ; 
        PORT
            LAYER met1 ;
              RECT  0 446.86 0.595 447 ;
        END
    END m_r[16]
    PIN m_r[17]
        DIRECTION INPUT ; 
        USE SIGNAL ; 
        PORT
            LAYER met1 ;
              RECT  0 473.38 0.595 473.52 ;
        END
    END m_r[17]
    PIN m_r[18]
        DIRECTION INPUT ; 
        USE SIGNAL ; 
        PORT
            LAYER met1 ;
              RECT  705.88 635.9 706.475 636.04 ;
        END
    END m_r[18]
    PIN m_r[19]
        DIRECTION INPUT ; 
        USE SIGNAL ; 
        PORT
            LAYER met1 ;
              RECT  705.88 582.18 706.475 582.32 ;
        END
    END m_r[19]
    PIN m_r[1]
        DIRECTION INPUT ; 
        USE SIGNAL ; 
        PORT
            LAYER met1 ;
              RECT  0 404.02 0.595 404.16 ;
        END
    END m_r[1]
    PIN m_r[20]
        DIRECTION INPUT ; 
        USE SIGNAL ; 
        PORT
            LAYER met1 ;
              RECT  705.88 355.74 706.475 355.88 ;
        END
    END m_r[20]
    PIN m_r[21]
        DIRECTION INPUT ; 
        USE SIGNAL ; 
        PORT
            LAYER met2 ;
              RECT  428.88 705.99 429.02 706.475 ;
        END
    END m_r[21]
    PIN m_r[22]
        DIRECTION INPUT ; 
        USE SIGNAL ; 
        PORT
            LAYER met2 ;
              RECT  225.56 705.99 225.7 706.475 ;
        END
    END m_r[22]
    PIN m_r[23]
        DIRECTION INPUT ; 
        USE SIGNAL ; 
        PORT
            LAYER met2 ;
              RECT  261.44 705.99 261.58 706.475 ;
        END
    END m_r[23]
    PIN m_r[24]
        DIRECTION INPUT ; 
        USE SIGNAL ; 
        PORT
            LAYER met2 ;
              RECT  566.88 705.99 567.02 706.475 ;
        END
    END m_r[24]
    PIN m_r[25]
        DIRECTION INPUT ; 
        USE SIGNAL ; 
        PORT
            LAYER met2 ;
              RECT  393.92 0 394.06 0.485 ;
        END
    END m_r[25]
    PIN m_r[26]
        DIRECTION INPUT ; 
        USE SIGNAL ; 
        PORT
            LAYER met2 ;
              RECT  349.76 0 349.9 0.485 ;
        END
    END m_r[26]
    PIN m_r[27]
        DIRECTION INPUT ; 
        USE SIGNAL ; 
        PORT
            LAYER met1 ;
              RECT  705.88 458.42 706.475 458.56 ;
        END
    END m_r[27]
    PIN m_r[28]
        DIRECTION INPUT ; 
        USE SIGNAL ; 
        PORT
            LAYER met2 ;
              RECT  436.24 705.99 436.38 706.475 ;
        END
    END m_r[28]
    PIN m_r[29]
        DIRECTION INPUT ; 
        USE SIGNAL ; 
        PORT
            LAYER met1 ;
              RECT  705.88 17.1 706.475 17.24 ;
        END
    END m_r[29]
    PIN m_r[2]
        DIRECTION INPUT ; 
        USE SIGNAL ; 
        PORT
            LAYER met1 ;
              RECT  0 387.7 0.595 387.84 ;
        END
    END m_r[2]
    PIN m_r[30]
        DIRECTION INPUT ; 
        USE SIGNAL ; 
        PORT
            LAYER met2 ;
              RECT  123.44 705.99 123.58 706.475 ;
        END
    END m_r[30]
    PIN m_r[31]
        DIRECTION INPUT ; 
        USE SIGNAL ; 
        PORT
            LAYER met2 ;
              RECT  203.48 705.99 203.62 706.475 ;
        END
    END m_r[31]
    PIN m_r[32]
        DIRECTION INPUT ; 
        USE SIGNAL ; 
        PORT
            LAYER met1 ;
              RECT  705.88 689.62 706.475 689.76 ;
        END
    END m_r[32]
    PIN m_r[33]
        DIRECTION INPUT ; 
        USE SIGNAL ; 
        PORT
            LAYER met1 ;
              RECT  705.88 410.14 706.475 410.28 ;
        END
    END m_r[33]
    PIN m_r[3]
        DIRECTION INPUT ; 
        USE SIGNAL ; 
        PORT
            LAYER met1 ;
              RECT  705.88 162.62 706.475 162.76 ;
        END
    END m_r[3]
    PIN m_r[4]
        DIRECTION INPUT ; 
        USE SIGNAL ; 
        PORT
            LAYER met1 ;
              RECT  705.88 238.1 706.475 238.24 ;
        END
    END m_r[4]
    PIN m_r[5]
        DIRECTION INPUT ; 
        USE SIGNAL ; 
        PORT
            LAYER met2 ;
              RECT  575.16 0 575.3 0.485 ;
        END
    END m_r[5]
    PIN m_r[6]
        DIRECTION INPUT ; 
        USE SIGNAL ; 
        PORT
            LAYER met1 ;
              RECT  0 242.18 0.595 242.32 ;
        END
    END m_r[6]
    PIN m_r[7]
        DIRECTION INPUT ; 
        USE SIGNAL ; 
        PORT
            LAYER met1 ;
              RECT  705.88 345.54 706.475 345.68 ;
        END
    END m_r[7]
    PIN m_r[8]
        DIRECTION INPUT ; 
        USE SIGNAL ; 
        PORT
            LAYER met1 ;
              RECT  0 371.38 0.595 371.52 ;
        END
    END m_r[8]
    PIN m_r[9]
        DIRECTION INPUT ; 
        USE SIGNAL ; 
        PORT
            LAYER met1 ;
              RECT  0 113.66 0.595 113.8 ;
        END
    END m_r[9]
    PIN m_rready
        DIRECTION OUTPUT ; 
        USE SIGNAL ; 
        PORT
            LAYER met2 ;
              RECT  371.84 0 371.98 0.485 ;
        END
    END m_rready
    PIN m_rvalid
        DIRECTION INPUT ; 
        USE SIGNAL ; 
        PORT
            LAYER met2 ;
              RECT  254.08 705.99 254.22 706.475 ;
        END
    END m_rvalid
    PIN m_w[0]
        DIRECTION OUTPUT ; 
        USE SIGNAL ; 
        PORT
            LAYER met1 ;
              RECT  705.88 495.82 706.475 495.96 ;
        END
    END m_w[0]
    PIN m_w[10]
        DIRECTION OUTPUT ; 
        USE SIGNAL ; 
        PORT
            LAYER met1 ;
              RECT  0 500.58 0.595 500.72 ;
        END
    END m_w[10]
    PIN m_w[11]
        DIRECTION OUTPUT ; 
        USE SIGNAL ; 
        PORT
            LAYER met1 ;
              RECT  0 81.02 0.595 81.16 ;
        END
    END m_w[11]
    PIN m_w[12]
        DIRECTION OUTPUT ; 
        USE SIGNAL ; 
        PORT
            LAYER met2 ;
              RECT  204.4 0 204.54 0.485 ;
        END
    END m_w[12]
    PIN m_w[13]
        DIRECTION OUTPUT ; 
        USE SIGNAL ; 
        PORT
            LAYER met1 ;
              RECT  0 602.58 0.595 602.72 ;
        END
    END m_w[13]
    PIN m_w[14]
        DIRECTION OUTPUT ; 
        USE SIGNAL ; 
        PORT
            LAYER met1 ;
              RECT  0 312.22 0.595 312.36 ;
        END
    END m_w[14]
    PIN m_w[15]
        DIRECTION OUTPUT ; 
        USE SIGNAL ; 
        PORT
            LAYER met1 ;
              RECT  0 570.62 0.595 570.76 ;
        END
    END m_w[15]
    PIN m_w[16]
        DIRECTION OUTPUT ; 
        USE SIGNAL ; 
        PORT
            LAYER met2 ;
              RECT  73.76 0 73.9 0.485 ;
        END
    END m_w[16]
    PIN m_w[17]
        DIRECTION OUTPUT ; 
        USE SIGNAL ; 
        PORT
            LAYER met2 ;
              RECT  348.84 705.99 348.98 706.475 ;
        END
    END m_w[17]
    PIN m_w[18]
        DIRECTION OUTPUT ; 
        USE SIGNAL ; 
        PORT
            LAYER met2 ;
              RECT  495.12 0 495.26 0.485 ;
        END
    END m_w[18]
    PIN m_w[19]
        DIRECTION OUTPUT ; 
        USE SIGNAL ; 
        PORT
            LAYER met2 ;
              RECT  210.84 705.99 210.98 706.475 ;
        END
    END m_w[19]
    PIN m_w[1]
        DIRECTION OUTPUT ; 
        USE SIGNAL ; 
        PORT
            LAYER met2 ;
              RECT  677.28 0 677.42 0.485 ;
        END
    END m_w[1]
    PIN m_w[20]
        DIRECTION OUTPUT ; 
        USE SIGNAL ; 
        PORT
            LAYER met2 ;
              RECT  459.24 0 459.38 0.485 ;
        END
    END m_w[20]
    PIN m_w[21]
        DIRECTION OUTPUT ; 
        USE SIGNAL ; 
        PORT
            LAYER met1 ;
              RECT  705.88 291.82 706.475 291.96 ;
        END
    END m_w[21]
    PIN m_w[22]
        DIRECTION OUTPUT ; 
        USE SIGNAL ; 
        PORT
            LAYER met2 ;
              RECT  378.28 705.99 378.42 706.475 ;
        END
    END m_w[22]
    PIN m_w[23]
        DIRECTION OUTPUT ; 
        USE SIGNAL ; 
        PORT
            LAYER met1 ;
              RECT  0 295.9 0.595 296.04 ;
        END
    END m_w[23]
    PIN m_w[24]
        DIRECTION OUTPUT ; 
        USE SIGNAL ; 
        PORT
            LAYER met2 ;
              RECT  683.72 705.99 683.86 706.475 ;
        END
    END m_w[24]
    PIN m_w[25]
        DIRECTION OUTPUT ; 
        USE SIGNAL ; 
        PORT
            LAYER met1 ;
              RECT  0 613.46 0.595 613.6 ;
        END
    END m_w[25]
    PIN m_w[26]
        DIRECTION OUTPUT ; 
        USE SIGNAL ; 
        PORT
            LAYER met1 ;
              RECT  0 43.62 0.595 43.76 ;
        END
    END m_w[26]
    PIN m_w[27]
        DIRECTION OUTPUT ; 
        USE SIGNAL ; 
        PORT
            LAYER met2 ;
              RECT  240.28 0 240.42 0.485 ;
        END
    END m_w[27]
    PIN m_w[28]
        DIRECTION OUTPUT ; 
        USE SIGNAL ; 
        PORT
            LAYER met1 ;
              RECT  705.88 49.74 706.475 49.88 ;
        END
    END m_w[28]
    PIN m_w[29]
        DIRECTION OUTPUT ; 
        USE SIGNAL ; 
        PORT
            LAYER met2 ;
              RECT  239.36 705.99 239.5 706.475 ;
        END
    END m_w[29]
    PIN m_w[2]
        DIRECTION OUTPUT ; 
        USE SIGNAL ; 
        PORT
            LAYER met1 ;
              RECT  705.88 506.7 706.475 506.84 ;
        END
    END m_w[2]
    PIN m_w[30]
        DIRECTION OUTPUT ; 
        USE SIGNAL ; 
        PORT
            LAYER met1 ;
              RECT  705.88 318.34 706.475 318.48 ;
        END
    END m_w[30]
    PIN m_w[31]
        DIRECTION OUTPUT ; 
        USE SIGNAL ; 
        PORT
            LAYER met2 ;
              RECT  559.52 705.99 559.66 706.475 ;
        END
    END m_w[31]
    PIN m_w[32]
        DIRECTION OUTPUT ; 
        USE SIGNAL ; 
        PORT
            LAYER met1 ;
              RECT  0 156.5 0.595 156.64 ;
        END
    END m_w[32]
    PIN m_w[33]
        DIRECTION OUTPUT ; 
        USE SIGNAL ; 
        PORT
            LAYER met1 ;
              RECT  0 667.18 0.595 667.32 ;
        END
    END m_w[33]
    PIN m_w[34]
        DIRECTION OUTPUT ; 
        USE SIGNAL ; 
        PORT
            LAYER met1 ;
              RECT  705.88 377.5 706.475 377.64 ;
        END
    END m_w[34]
    PIN m_w[35]
        DIRECTION OUTPUT ; 
        USE SIGNAL ; 
        PORT
            LAYER met1 ;
              RECT  705.88 592.38 706.475 592.52 ;
        END
    END m_w[35]
    PIN m_w[3]
        DIRECTION OUTPUT ; 
        USE SIGNAL ; 
        PORT
            LAYER met2 ;
              RECT  6.6 705.99 6.74 706.475 ;
        END
    END m_w[3]
    PIN m_w[4]
        DIRECTION OUTPUT ; 
        USE SIGNAL ; 
        PORT
            LAYER met1 ;
              RECT  0 548.86 0.595 549 ;
        END
    END m_w[4]
    PIN m_w[5]
        DIRECTION OUTPUT ; 
        USE SIGNAL ; 
        PORT
            LAYER met1 ;
              RECT  0 317.66 0.595 317.8 ;
        END
    END m_w[5]
    PIN m_w[6]
        DIRECTION OUTPUT ; 
        USE SIGNAL ; 
        PORT
            LAYER met2 ;
              RECT  197.04 0 197.18 0.485 ;
        END
    END m_w[6]
    PIN m_w[7]
        DIRECTION OUTPUT ; 
        USE SIGNAL ; 
        PORT
            LAYER met2 ;
              RECT  699.36 0 699.5 0.485 ;
        END
    END m_w[7]
    PIN m_w[8]
        DIRECTION OUTPUT ; 
        USE SIGNAL ; 
        PORT
            LAYER met1 ;
              RECT  705.88 183.7 706.475 183.84 ;
        END
    END m_w[8]
    PIN m_w[9]
        DIRECTION OUTPUT ; 
        USE SIGNAL ; 
        PORT
            LAYER met2 ;
              RECT  166.68 705.99 166.82 706.475 ;
        END
    END m_w[9]
    PIN m_wready
        DIRECTION INPUT ; 
        USE SIGNAL ; 
        PORT
            LAYER met1 ;
              RECT  0 656.3 0.595 656.44 ;
        END
    END m_wready
    PIN m_wvalid
        DIRECTION OUTPUT ; 
        USE SIGNAL ; 
        PORT
            LAYER met2 ;
              RECT  508.92 705.99 509.06 706.475 ;
        END
    END m_wvalid
    PIN rst_n
        DIRECTION INPUT ; 
        USE SIGNAL ; 
        PORT
            LAYER met2 ;
              RECT  392.08 705.99 392.22 706.475 ;
        END
    END rst_n
    PIN rtr_busy
        DIRECTION INPUT ; 
        USE SIGNAL ; 
        PORT
            LAYER met2 ;
              RECT  247.64 0 247.78 0.485 ;
        END
    END rtr_busy
    PIN rtr_kick
        DIRECTION OUTPUT ; 
        USE SIGNAL ; 
        PORT
            LAYER met1 ;
              RECT  0 32.74 0.595 32.88 ;
        END
    END rtr_kick
    PIN s_ar[0]
        DIRECTION INPUT ; 
        USE SIGNAL ; 
        PORT
            LAYER met1 ;
              RECT  705.88 55.18 706.475 55.32 ;
        END
    END s_ar[0]
    PIN s_ar[10]
        DIRECTION INPUT ; 
        USE SIGNAL ; 
        PORT
            LAYER met2 ;
              RECT  341.48 705.99 341.62 706.475 ;
        END
    END s_ar[10]
    PIN s_ar[11]
        DIRECTION INPUT ; 
        USE SIGNAL ; 
        PORT
            LAYER met2 ;
              RECT  160.24 0 160.38 0.485 ;
        END
    END s_ar[11]
    PIN s_ar[12]
        DIRECTION INPUT ; 
        USE SIGNAL ; 
        PORT
            LAYER met1 ;
              RECT  705.88 463.86 706.475 464 ;
        END
    END s_ar[12]
    PIN s_ar[13]
        DIRECTION INPUT ; 
        USE SIGNAL ; 
        PORT
            LAYER met2 ;
              RECT  661.64 705.99 661.78 706.475 ;
        END
    END s_ar[13]
    PIN s_ar[14]
        DIRECTION INPUT ; 
        USE SIGNAL ; 
        PORT
            LAYER met2 ;
              RECT  611.04 705.99 611.18 706.475 ;
        END
    END s_ar[14]
    PIN s_ar[15]
        DIRECTION INPUT ; 
        USE SIGNAL ; 
        PORT
            LAYER met1 ;
              RECT  705.88 678.74 706.475 678.88 ;
        END
    END s_ar[15]
    PIN s_ar[16]
        DIRECTION INPUT ; 
        USE SIGNAL ; 
        PORT
            LAYER met1 ;
              RECT  0 215.66 0.595 215.8 ;
        END
    END s_ar[16]
    PIN s_ar[17]
        DIRECTION INPUT ; 
        USE SIGNAL ; 
        PORT
            LAYER met1 ;
              RECT  0 376.82 0.595 376.96 ;
        END
    END s_ar[17]
    PIN s_ar[18]
        DIRECTION INPUT ; 
        USE SIGNAL ; 
        PORT
            LAYER met2 ;
              RECT  444.52 0 444.66 0.485 ;
        END
    END s_ar[18]
    PIN s_ar[19]
        DIRECTION INPUT ; 
        USE SIGNAL ; 
        PORT
            LAYER met1 ;
              RECT  0 591.7 0.595 591.84 ;
        END
    END s_ar[19]
    PIN s_ar[1]
        DIRECTION INPUT ; 
        USE SIGNAL ; 
        PORT
            LAYER met1 ;
              RECT  0 543.42 0.595 543.56 ;
        END
    END s_ar[1]
    PIN s_ar[20]
        DIRECTION INPUT ; 
        USE SIGNAL ; 
        PORT
            LAYER met2 ;
              RECT  7.52 0 7.66 0.485 ;
        END
    END s_ar[20]
    PIN s_ar[21]
        DIRECTION INPUT ; 
        USE SIGNAL ; 
        PORT
            LAYER met1 ;
              RECT  0 419.66 0.595 419.8 ;
        END
    END s_ar[21]
    PIN s_ar[22]
        DIRECTION INPUT ; 
        USE SIGNAL ; 
        PORT
            LAYER met1 ;
              RECT  0 97.34 0.595 97.48 ;
        END
    END s_ar[22]
    PIN s_ar[23]
        DIRECTION INPUT ; 
        USE SIGNAL ; 
        PORT
            LAYER met1 ;
              RECT  705.88 146.3 706.475 146.44 ;
        END
    END s_ar[23]
    PIN s_ar[24]
        DIRECTION INPUT ; 
        USE SIGNAL ; 
        PORT
            LAYER met2 ;
              RECT  588.96 705.99 589.1 706.475 ;
        END
    END s_ar[24]
    PIN s_ar[25]
        DIRECTION INPUT ; 
        USE SIGNAL ; 
        PORT
            LAYER met1 ;
              RECT  705.88 200.02 706.475 200.16 ;
        END
    END s_ar[25]
    PIN s_ar[26]
        DIRECTION INPUT ; 
        USE SIGNAL ; 
        PORT
            LAYER met1 ;
              RECT  0 576.06 0.595 576.2 ;
        END
    END s_ar[26]
    PIN s_ar[27]
        DIRECTION INPUT ; 
        USE SIGNAL ; 
        PORT
            LAYER met2 ;
              RECT  29.6 0 29.74 0.485 ;
        END
    END s_ar[27]
    PIN s_ar[28]
        DIRECTION INPUT ; 
        USE SIGNAL ; 
        PORT
            LAYER met2 ;
              RECT  167.6 0 167.74 0.485 ;
        END
    END s_ar[28]
    PIN s_ar[29]
        DIRECTION INPUT ; 
        USE SIGNAL ; 
        PORT
            LAYER met2 ;
              RECT  386.56 0 386.7 0.485 ;
        END
    END s_ar[29]
    PIN s_ar[2]
        DIRECTION INPUT ; 
        USE SIGNAL ; 
        PORT
            LAYER met1 ;
              RECT  0 183.02 0.595 183.16 ;
        END
    END s_ar[2]
    PIN s_ar[30]
        DIRECTION INPUT ; 
        USE SIGNAL ; 
        PORT
            LAYER met1 ;
              RECT  0 478.82 0.595 478.96 ;
        END
    END s_ar[30]
    PIN s_ar[31]
        DIRECTION INPUT ; 
        USE SIGNAL ; 
        PORT
            LAYER met1 ;
              RECT  0 435.98 0.595 436.12 ;
        END
    END s_ar[31]
    PIN s_ar[32]
        DIRECTION INPUT ; 
        USE SIGNAL ; 
        PORT
            LAYER met2 ;
              RECT  647.84 0 647.98 0.485 ;
        END
    END s_ar[32]
    PIN s_ar[33]
        DIRECTION INPUT ; 
        USE SIGNAL ; 
        PORT
            LAYER met1 ;
              RECT  705.88 425.78 706.475 425.92 ;
        END
    END s_ar[33]
    PIN s_ar[34]
        DIRECTION INPUT ; 
        USE SIGNAL ; 
        PORT
            LAYER met1 ;
              RECT  705.88 544.1 706.475 544.24 ;
        END
    END s_ar[34]
    PIN s_ar[3]
        DIRECTION INPUT ; 
        USE SIGNAL ; 
        PORT
            LAYER met2 ;
              RECT  669.92 0 670.06 0.485 ;
        END
    END s_ar[3]
    PIN s_ar[4]
        DIRECTION INPUT ; 
        USE SIGNAL ; 
        PORT
            LAYER met2 ;
              RECT  58.12 705.99 58.26 706.475 ;
        END
    END s_ar[4]
    PIN s_ar[5]
        DIRECTION INPUT ; 
        USE SIGNAL ; 
        PORT
            LAYER met1 ;
              RECT  705.88 108.9 706.475 109.04 ;
        END
    END s_ar[5]
    PIN s_ar[6]
        DIRECTION INPUT ; 
        USE SIGNAL ; 
        PORT
            LAYER met1 ;
              RECT  705.88 523.02 706.475 523.16 ;
        END
    END s_ar[6]
    PIN s_ar[7]
        DIRECTION INPUT ; 
        USE SIGNAL ; 
        PORT
            LAYER met1 ;
              RECT  0 495.14 0.595 495.28 ;
        END
    END s_ar[7]
    PIN s_ar[8]
        DIRECTION INPUT ; 
        USE SIGNAL ; 
        PORT
            LAYER met1 ;
              RECT  705.88 442.1 706.475 442.24 ;
        END
    END s_ar[8]
    PIN s_ar[9]
        DIRECTION INPUT ; 
        USE SIGNAL ; 
        PORT
            LAYER met2 ;
              RECT  655.2 0 655.34 0.485 ;
        END
    END s_ar[9]
    PIN s_arready
        DIRECTION OUTPUT ; 
        USE SIGNAL ; 
        PORT
            LAYER met1 ;
              RECT  0 140.18 0.595 140.32 ;
        END
    END s_arready
    PIN s_arvalid
        DIRECTION INPUT ; 
        USE SIGNAL ; 
        PORT
            LAYER met1 ;
              RECT  705.88 178.94 706.475 179.08 ;
        END
    END s_arvalid
    PIN s_aw[0]
        DIRECTION INPUT ; 
        USE SIGNAL ; 
        PORT
            LAYER met1 ;
              RECT  0 108.22 0.595 108.36 ;
        END
    END s_aw[0]
    PIN s_aw[10]
        DIRECTION INPUT ; 
        USE SIGNAL ; 
        PORT
            LAYER met1 ;
              RECT  705.88 65.38 706.475 65.52 ;
        END
    END s_aw[10]
    PIN s_aw[11]
        DIRECTION INPUT ; 
        USE SIGNAL ; 
        PORT
            LAYER met1 ;
              RECT  0 704.58 0.595 704.72 ;
        END
    END s_aw[11]
    PIN s_aw[12]
        DIRECTION INPUT ; 
        USE SIGNAL ; 
        PORT
            LAYER met2 ;
              RECT  109.64 0 109.78 0.485 ;
        END
    END s_aw[12]
    PIN s_aw[13]
        DIRECTION INPUT ; 
        USE SIGNAL ; 
        PORT
            LAYER met1 ;
              RECT  0 344.86 0.595 345 ;
        END
    END s_aw[13]
    PIN s_aw[14]
        DIRECTION INPUT ; 
        USE SIGNAL ; 
        PORT
            LAYER met1 ;
              RECT  0 339.42 0.595 339.56 ;
        END
    END s_aw[14]
    PIN s_aw[15]
        DIRECTION INPUT ; 
        USE SIGNAL ; 
        PORT
            LAYER met1 ;
              RECT  705.88 528.46 706.475 528.6 ;
        END
    END s_aw[15]
    PIN s_aw[16]
        DIRECTION INPUT ; 
        USE SIGNAL ; 
        PORT
            LAYER met2 ;
              RECT  219.12 0 219.26 0.485 ;
        END
    END s_aw[16]
    PIN s_aw[17]
        DIRECTION INPUT ; 
        USE SIGNAL ; 
        PORT
            LAYER met1 ;
              RECT  705.88 81.7 706.475 81.84 ;
        END
    END s_aw[17]
    PIN s_aw[18]
        DIRECTION INPUT ; 
        USE SIGNAL ; 
        PORT
            LAYER met1 ;
              RECT  0 274.82 0.595 274.96 ;
        END
    END s_aw[18]
    PIN s_aw[19]
        DIRECTION INPUT ; 
        USE SIGNAL ; 
        PORT
            LAYER met2 ;
              RECT  531 705.99 531.14 706.475 ;
        END
    END s_aw[19]
    PIN s_aw[1]
        DIRECTION INPUT ; 
        USE SIGNAL ; 
        PORT
            LAYER met1 ;
              RECT  705.88 597.82 706.475 597.96 ;
        END
    END s_aw[1]
    PIN s_aw[20]
        DIRECTION INPUT ; 
        USE SIGNAL ; 
        PORT
            LAYER met2 ;
              RECT  13.96 705.99 14.1 706.475 ;
        END
    END s_aw[20]
    PIN s_aw[21]
        DIRECTION INPUT ; 
        USE SIGNAL ; 
        PORT
            LAYER met2 ;
              RECT  86.64 705.99 86.78 706.475 ;
        END
    END s_aw[21]
    PIN s_aw[22]
        DIRECTION INPUT ; 
        USE SIGNAL ; 
        PORT
            LAYER met1 ;
              RECT  705.88 221.78 706.475 221.92 ;
        END
    END s_aw[22]
    PIN s_aw[23]
        DIRECTION INPUT ; 
        USE SIGNAL ; 
        PORT
            LAYER met1 ;
              RECT  0 27.3 0.595 27.44 ;
        END
    END s_aw[23]
    PIN s_aw[24]
        DIRECTION INPUT ; 
        USE SIGNAL ; 
        PORT
            LAYER met1 ;
              RECT  705.88 329.22 706.475 329.36 ;
        END
    END s_aw[24]
    PIN s_aw[25]
        DIRECTION INPUT ; 
        USE SIGNAL ; 
        PORT
            LAYER met2 ;
              RECT  370.92 705.99 371.06 706.475 ;
        END
    END s_aw[25]
    PIN s_aw[26]
        DIRECTION INPUT ; 
        USE SIGNAL ; 
        PORT
            LAYER met2 ;
              RECT  188.76 705.99 188.9 706.475 ;
        END
    END s_aw[26]
    PIN s_aw[27]
        DIRECTION INPUT ; 
        USE SIGNAL ; 
        PORT
            LAYER met1 ;
              RECT  0 597.14 0.595 597.28 ;
        END
    END s_aw[27]
    PIN s_aw[28]
        DIRECTION INPUT ; 
        USE SIGNAL ; 
        PORT
            LAYER met2 ;
              RECT  80.2 0 80.34 0.485 ;
        END
    END s_aw[28]
    PIN s_aw[29]
        DIRECTION INPUT ; 
        USE SIGNAL ; 
        PORT
            LAYER met1 ;
              RECT  0 365.94 0.595 366.08 ;
        END
    END s_aw[29]
    PIN s_aw[2]
        DIRECTION INPUT ; 
        USE SIGNAL ; 
        PORT
            LAYER met1 ;
              RECT  0 75.58 0.595 75.72 ;
        END
    END s_aw[2]
    PIN s_aw[30]
        DIRECTION INPUT ; 
        USE SIGNAL ; 
        PORT
            LAYER met1 ;
              RECT  705.88 533.22 706.475 533.36 ;
        END
    END s_aw[30]
    PIN s_aw[31]
        DIRECTION INPUT ; 
        USE SIGNAL ; 
        PORT
            LAYER met2 ;
              RECT  546.64 0 546.78 0.485 ;
        END
    END s_aw[31]
    PIN s_aw[32]
        DIRECTION INPUT ; 
        USE SIGNAL ; 
        PORT
            LAYER met1 ;
              RECT  705.88 490.38 706.475 490.52 ;
        END
    END s_aw[32]
    PIN s_aw[33]
        DIRECTION INPUT ; 
        USE SIGNAL ; 
        PORT
            LAYER met1 ;
              RECT  0 291.14 0.595 291.28 ;
        END
    END s_aw[33]
    PIN s_aw[34]
        DIRECTION INPUT ; 
        USE SIGNAL ; 
        PORT
            LAYER met1 ;
              RECT  705.88 87.14 706.475 87.28 ;
        END
    END s_aw[34]
    PIN s_aw[3]
        DIRECTION INPUT ; 
        USE SIGNAL ; 
        PORT
            LAYER met2 ;
              RECT  363.56 705.99 363.7 706.475 ;
        END
    END s_aw[3]
    PIN s_aw[4]
        DIRECTION INPUT ; 
        USE SIGNAL ; 
        PORT
            LAYER met2 ;
              RECT  603.68 705.99 603.82 706.475 ;
        END
    END s_aw[4]
    PIN s_aw[5]
        DIRECTION INPUT ; 
        USE SIGNAL ; 
        PORT
            LAYER met2 ;
              RECT  480.4 0 480.54 0.485 ;
        END
    END s_aw[5]
    PIN s_aw[6]
        DIRECTION INPUT ; 
        USE SIGNAL ; 
        PORT
            LAYER met1 ;
              RECT  0 258.5 0.595 258.64 ;
        END
    END s_aw[6]
    PIN s_aw[7]
        DIRECTION INPUT ; 
        USE SIGNAL ; 
        PORT
            LAYER met1 ;
              RECT  705.88 253.74 706.475 253.88 ;
        END
    END s_aw[7]
    PIN s_aw[8]
        DIRECTION INPUT ; 
        USE SIGNAL ; 
        PORT
            LAYER met1 ;
              RECT  0 645.42 0.595 645.56 ;
        END
    END s_aw[8]
    PIN s_aw[9]
        DIRECTION INPUT ; 
        USE SIGNAL ; 
        PORT
            LAYER met2 ;
              RECT  466.6 0 466.74 0.485 ;
        END
    END s_aw[9]
    PIN s_awready
        DIRECTION OUTPUT ; 
        USE SIGNAL ; 
        PORT
            LAYER met2 ;
              RECT  87.56 0 87.7 0.485 ;
        END
    END s_awready
    PIN s_awvalid
        DIRECTION INPUT ; 
        USE SIGNAL ; 
        PORT
            LAYER met1 ;
              RECT  0 102.78 0.595 102.92 ;
        END
    END s_awvalid
    PIN s_b[0]
        DIRECTION OUTPUT ; 
        USE SIGNAL ; 
        PORT
            LAYER met1 ;
              RECT  705.88 474.06 706.475 474.2 ;
        END
    END s_b[0]
    PIN s_b[1]
        DIRECTION OUTPUT ; 
        USE SIGNAL ; 
        PORT
            LAYER met2 ;
              RECT  704.88 705.99 705.02 706.475 ;
        END
    END s_b[1]
    PIN s_bready
        DIRECTION INPUT ; 
        USE SIGNAL ; 
        PORT
            LAYER met2 ;
              RECT  327.68 0 327.82 0.485 ;
        END
    END s_bready
    PIN s_bvalid
        DIRECTION OUTPUT ; 
        USE SIGNAL ; 
        PORT
            LAYER met2 ;
              RECT  494.2 705.99 494.34 706.475 ;
        END
    END s_bvalid
    PIN s_r[0]
        DIRECTION OUTPUT ; 
        USE SIGNAL ; 
        PORT
            LAYER met1 ;
              RECT  705.88 372.06 706.475 372.2 ;
        END
    END s_r[0]
    PIN s_r[10]
        DIRECTION OUTPUT ; 
        USE SIGNAL ; 
        PORT
            LAYER met1 ;
              RECT  0 145.62 0.595 145.76 ;
        END
    END s_r[10]
    PIN s_r[11]
        DIRECTION OUTPUT ; 
        USE SIGNAL ; 
        PORT
            LAYER met2 ;
              RECT  472.12 705.99 472.26 706.475 ;
        END
    END s_r[11]
    PIN s_r[12]
        DIRECTION OUTPUT ; 
        USE SIGNAL ; 
        PORT
            LAYER met2 ;
              RECT  633.12 0 633.26 0.485 ;
        END
    END s_r[12]
    PIN s_r[13]
        DIRECTION OUTPUT ; 
        USE SIGNAL ; 
        PORT
            LAYER met2 ;
              RECT  269.72 0 269.86 0.485 ;
        END
    END s_r[13]
    PIN s_r[14]
        DIRECTION OUTPUT ; 
        USE SIGNAL ; 
        PORT
            LAYER met2 ;
              RECT  44.32 0 44.46 0.485 ;
        END
    END s_r[14]
    PIN s_r[15]
        DIRECTION OUTPUT ; 
        USE SIGNAL ; 
        PORT
            LAYER met1 ;
              RECT  705.88 103.46 706.475 103.6 ;
        END
    END s_r[15]
    PIN s_r[16]
        DIRECTION OUTPUT ; 
        USE SIGNAL ; 
        PORT
            LAYER met1 ;
              RECT  705.88 275.5 706.475 275.64 ;
        END
    END s_r[16]
    PIN s_r[17]
        DIRECTION OUTPUT ; 
        USE SIGNAL ; 
        PORT
            LAYER met1 ;
              RECT  0 129.3 0.595 129.44 ;
        END
    END s_r[17]
    PIN s_r[18]
        DIRECTION OUTPUT ; 
        USE SIGNAL ; 
        PORT
            LAYER met1 ;
              RECT  705.88 646.78 706.475 646.92 ;
        END
    END s_r[18]
    PIN s_r[19]
        DIRECTION OUTPUT ; 
        USE SIGNAL ; 
        PORT
            LAYER met1 ;
              RECT  0 441.42 0.595 441.56 ;
        END
    END s_r[19]
    PIN s_r[1]
        DIRECTION OUTPUT ; 
        USE SIGNAL ; 
        PORT
            LAYER met1 ;
              RECT  0 484.26 0.595 484.4 ;
        END
    END s_r[1]
    PIN s_r[20]
        DIRECTION OUTPUT ; 
        USE SIGNAL ; 
        PORT
            LAYER met1 ;
              RECT  0 463.18 0.595 463.32 ;
        END
    END s_r[20]
    PIN s_r[21]
        DIRECTION OUTPUT ; 
        USE SIGNAL ; 
        PORT
            LAYER met2 ;
              RECT  36.96 0 37.1 0.485 ;
        END
    END s_r[21]
    PIN s_r[22]
        DIRECTION OUTPUT ; 
        USE SIGNAL ; 
        PORT
            LAYER met1 ;
              RECT  0 70.14 0.595 70.28 ;
        END
    END s_r[22]
    PIN s_r[23]
        DIRECTION OUTPUT ; 
        USE SIGNAL ; 
        PORT
            LAYER met1 ;
              RECT  705.88 431.22 706.475 431.36 ;
        END
    END s_r[23]
    PIN s_r[24]
        DIRECTION OUTPUT ; 
        USE SIGNAL ; 
        PORT
            LAYER met2 ;
              RECT  487.76 0 487.9 0.485 ;
        END
    END s_r[24]
    PIN s_r[25]
        DIRECTION OUTPUT ; 
        USE SIGNAL ; 
        PORT
            LAYER met2 ;
              RECT  414.16 705.99 414.3 706.475 ;
        END
    END s_r[25]
    PIN s_r[26]
        DIRECTION OUTPUT ; 
        USE SIGNAL ; 
        PORT
            LAYER met2 ;
              RECT  618.4 705.99 618.54 706.475 ;
        END
    END s_r[26]
    PIN s_r[27]
        DIRECTION OUTPUT ; 
        USE SIGNAL ; 
        PORT
            LAYER met1 ;
              RECT  0 618.9 0.595 619.04 ;
        END
    END s_r[27]
    PIN s_r[28]
        DIRECTION OUTPUT ; 
        USE SIGNAL ; 
        PORT
            LAYER met2 ;
              RECT  131.72 0 131.86 0.485 ;
        END
    END s_r[28]
    PIN s_r[29]
        DIRECTION OUTPUT ; 
        USE SIGNAL ; 
        PORT
            LAYER met1 ;
              RECT  0 263.94 0.595 264.08 ;
        END
    END s_r[29]
    PIN s_r[2]
        DIRECTION OUTPUT ; 
        USE SIGNAL ; 
        PORT
            LAYER met2 ;
              RECT  646.92 705.99 647.06 706.475 ;
        END
    END s_r[2]
    PIN s_r[30]
        DIRECTION OUTPUT ; 
        USE SIGNAL ; 
        PORT
            LAYER met1 ;
              RECT  0 333.98 0.595 334.12 ;
        END
    END s_r[30]
    PIN s_r[31]
        DIRECTION OUTPUT ; 
        USE SIGNAL ; 
        PORT
            LAYER met1 ;
              RECT  705.88 587.62 706.475 587.76 ;
        END
    END s_r[31]
    PIN s_r[32]
        DIRECTION OUTPUT ; 
        USE SIGNAL ; 
        PORT
            LAYER met1 ;
              RECT  705.88 307.46 706.475 307.6 ;
        END
    END s_r[32]
    PIN s_r[33]
        DIRECTION OUTPUT ; 
        USE SIGNAL ; 
        PORT
            LAYER met2 ;
              RECT  582.52 0 582.66 0.485 ;
        END
    END s_r[33]
    PIN s_r[3]
        DIRECTION OUTPUT ; 
        USE SIGNAL ; 
        PORT
            LAYER met2 ;
              RECT  545.72 705.99 545.86 706.475 ;
        END
    END s_r[3]
    PIN s_r[4]
        DIRECTION OUTPUT ; 
        USE SIGNAL ; 
        PORT
            LAYER met2 ;
              RECT  50.76 705.99 50.9 706.475 ;
        END
    END s_r[4]
    PIN s_r[5]
        DIRECTION OUTPUT ; 
        USE SIGNAL ; 
        PORT
            LAYER met2 ;
              RECT  262.36 0 262.5 0.485 ;
        END
    END s_r[5]
    PIN s_r[6]
        DIRECTION OUTPUT ; 
        USE SIGNAL ; 
        PORT
            LAYER met1 ;
              RECT  705.88 479.5 706.475 479.64 ;
        END
    END s_r[6]
    PIN s_r[7]
        DIRECTION OUTPUT ; 
        USE SIGNAL ; 
        PORT
            LAYER met2 ;
              RECT  692 0 692.14 0.485 ;
        END
    END s_r[7]
    PIN s_r[8]
        DIRECTION OUTPUT ; 
        USE SIGNAL ; 
        PORT
            LAYER met1 ;
              RECT  705.88 286.38 706.475 286.52 ;
        END
    END s_r[8]
    PIN s_r[9]
        DIRECTION OUTPUT ; 
        USE SIGNAL ; 
        PORT
            LAYER met1 ;
              RECT  0 301.34 0.595 301.48 ;
        END
    END s_r[9]
    PIN s_rready
        DIRECTION INPUT ; 
        USE SIGNAL ; 
        PORT
            LAYER met1 ;
              RECT  705.88 124.54 706.475 124.68 ;
        END
    END s_rready
    PIN s_rvalid
        DIRECTION OUTPUT ; 
        USE SIGNAL ; 
        PORT
            LAYER met2 ;
              RECT  139.08 0 139.22 0.485 ;
        END
    END s_rvalid
    PIN s_w[0]
        DIRECTION INPUT ; 
        USE SIGNAL ; 
        PORT
            LAYER met2 ;
              RECT  415.08 0 415.22 0.485 ;
        END
    END s_w[0]
    PIN s_w[10]
        DIRECTION INPUT ; 
        USE SIGNAL ; 
        PORT
            LAYER met1 ;
              RECT  705.88 366.62 706.475 366.76 ;
        END
    END s_w[10]
    PIN s_w[11]
        DIRECTION INPUT ; 
        USE SIGNAL ; 
        PORT
            LAYER met2 ;
              RECT  516.28 705.99 516.42 706.475 ;
        END
    END s_w[11]
    PIN s_w[12]
        DIRECTION INPUT ; 
        USE SIGNAL ; 
        PORT
            LAYER met1 ;
              RECT  705.88 651.54 706.475 651.68 ;
        END
    END s_w[12]
    PIN s_w[13]
        DIRECTION INPUT ; 
        USE SIGNAL ; 
        PORT
            LAYER met1 ;
              RECT  705.88 129.98 706.475 130.12 ;
        END
    END s_w[13]
    PIN s_w[14]
        DIRECTION INPUT ; 
        USE SIGNAL ; 
        PORT
            LAYER met2 ;
              RECT  66.4 0 66.54 0.485 ;
        END
    END s_w[14]
    PIN s_w[15]
        DIRECTION INPUT ; 
        USE SIGNAL ; 
        PORT
            LAYER met1 ;
              RECT  705.88 452.98 706.475 453.12 ;
        END
    END s_w[15]
    PIN s_w[16]
        DIRECTION INPUT ; 
        USE SIGNAL ; 
        PORT
            LAYER met2 ;
              RECT  14.88 0 15.02 0.485 ;
        END
    END s_w[16]
    PIN s_w[17]
        DIRECTION INPUT ; 
        USE SIGNAL ; 
        PORT
            LAYER met1 ;
              RECT  705.88 667.86 706.475 668 ;
        END
    END s_w[17]
    PIN s_w[18]
        DIRECTION INPUT ; 
        USE SIGNAL ; 
        PORT
            LAYER met2 ;
              RECT  486.84 705.99 486.98 706.475 ;
        END
    END s_w[18]
    PIN s_w[19]
        DIRECTION INPUT ; 
        USE SIGNAL ; 
        PORT
            LAYER met1 ;
              RECT  705.88 168.06 706.475 168.2 ;
        END
    END s_w[19]
    PIN s_w[1]
        DIRECTION INPUT ; 
        USE SIGNAL ; 
        PORT
            LAYER met2 ;
              RECT  458.32 705.99 458.46 706.475 ;
        END
    END s_w[1]
    PIN s_w[20]
        DIRECTION INPUT ; 
        USE SIGNAL ; 
        PORT
            LAYER met2 ;
              RECT  567.8 0 567.94 0.485 ;
        END
    END s_w[20]
    PIN s_w[21]
        DIRECTION INPUT ; 
        USE SIGNAL ; 
        PORT
            LAYER met1 ;
              RECT  0 177.58 0.595 177.72 ;
        END
    END s_w[21]
    PIN s_w[22]
        DIRECTION INPUT ; 
        USE SIGNAL ; 
        PORT
            LAYER met2 ;
              RECT  560.44 0 560.58 0.485 ;
        END
    END s_w[22]
    PIN s_w[23]
        DIRECTION INPUT ; 
        USE SIGNAL ; 
        PORT
            LAYER met2 ;
              RECT  1.08 0 1.22 0.485 ;
        END
    END s_w[23]
    PIN s_w[24]
        DIRECTION INPUT ; 
        USE SIGNAL ; 
        PORT
            LAYER met2 ;
              RECT  662.56 0 662.7 0.485 ;
        END
    END s_w[24]
    PIN s_w[25]
        DIRECTION INPUT ; 
        USE SIGNAL ; 
        PORT
            LAYER met1 ;
              RECT  0 280.26 0.595 280.4 ;
        END
    END s_w[25]
    PIN s_w[26]
        DIRECTION INPUT ; 
        USE SIGNAL ; 
        PORT
            LAYER met1 ;
              RECT  0 522.34 0.595 522.48 ;
        END
    END s_w[26]
    PIN s_w[27]
        DIRECTION INPUT ; 
        USE SIGNAL ; 
        PORT
            LAYER met2 ;
              RECT  94 705.99 94.14 706.475 ;
        END
    END s_w[27]
    PIN s_w[28]
        DIRECTION INPUT ; 
        USE SIGNAL ; 
        PORT
            LAYER met1 ;
              RECT  0 193.9 0.595 194.04 ;
        END
    END s_w[28]
    PIN s_w[29]
        DIRECTION INPUT ; 
        USE SIGNAL ; 
        PORT
            LAYER met2 ;
              RECT  174.96 0 175.1 0.485 ;
        END
    END s_w[29]
    PIN s_w[2]
        DIRECTION INPUT ; 
        USE SIGNAL ; 
        PORT
            LAYER met2 ;
              RECT  59.04 0 59.18 0.485 ;
        END
    END s_w[2]
    PIN s_w[30]
        DIRECTION INPUT ; 
        USE SIGNAL ; 
        PORT
            LAYER met2 ;
              RECT  298.24 705.99 298.38 706.475 ;
        END
    END s_w[30]
    PIN s_w[31]
        DIRECTION INPUT ; 
        USE SIGNAL ; 
        PORT
            LAYER met2 ;
              RECT  108.72 705.99 108.86 706.475 ;
        END
    END s_w[31]
    PIN s_w[32]
        DIRECTION INPUT ; 
        USE SIGNAL ; 
        PORT
            LAYER met2 ;
              RECT  451.88 0 452.02 0.485 ;
        END
    END s_w[32]
    PIN s_w[33]
        DIRECTION INPUT ; 
        USE SIGNAL ; 
        PORT
            LAYER met2 ;
              RECT  443.6 705.99 443.74 706.475 ;
        END
    END s_w[33]
    PIN s_w[34]
        DIRECTION INPUT ; 
        USE SIGNAL ; 
        PORT
            LAYER met1 ;
              RECT  705.88 270.06 706.475 270.2 ;
        END
    END s_w[34]
    PIN s_w[35]
        DIRECTION INPUT ; 
        USE SIGNAL ; 
        PORT
            LAYER met1 ;
              RECT  0 398.58 0.595 398.72 ;
        END
    END s_w[35]
    PIN s_w[3]
        DIRECTION INPUT ; 
        USE SIGNAL ; 
        PORT
            LAYER met1 ;
              RECT  705.88 571.3 706.475 571.44 ;
        END
    END s_w[3]
    PIN s_w[4]
        DIRECTION INPUT ; 
        USE SIGNAL ; 
        PORT
            LAYER met2 ;
              RECT  182.32 0 182.46 0.485 ;
        END
    END s_w[4]
    PIN s_w[5]
        DIRECTION INPUT ; 
        USE SIGNAL ; 
        PORT
            LAYER met2 ;
              RECT  320.32 0 320.46 0.485 ;
        END
    END s_w[5]
    PIN s_w[6]
        DIRECTION INPUT ; 
        USE SIGNAL ; 
        PORT
            LAYER met1 ;
              RECT  0 49.06 0.595 49.2 ;
        END
    END s_w[6]
    PIN s_w[7]
        DIRECTION INPUT ; 
        USE SIGNAL ; 
        PORT
            LAYER met1 ;
              RECT  705.88 549.54 706.475 549.68 ;
        END
    END s_w[7]
    PIN s_w[8]
        DIRECTION INPUT ; 
        USE SIGNAL ; 
        PORT
            LAYER met2 ;
              RECT  502.48 0 502.62 0.485 ;
        END
    END s_w[8]
    PIN s_w[9]
        DIRECTION INPUT ; 
        USE SIGNAL ; 
        PORT
            LAYER met2 ;
              RECT  421.52 705.99 421.66 706.475 ;
        END
    END s_w[9]
    PIN s_wready
        DIRECTION OUTPUT ; 
        USE SIGNAL ; 
        PORT
            LAYER met2 ;
              RECT  406.8 705.99 406.94 706.475 ;
        END
    END s_wready
    PIN s_wvalid
        DIRECTION INPUT ; 
        USE SIGNAL ; 
        PORT
            LAYER met1 ;
              RECT  0 565.18 0.595 565.32 ;
        END
    END s_wvalid
    PIN tu_busy
        DIRECTION INPUT ; 
        USE SIGNAL ; 
        PORT
            LAYER met1 ;
              RECT  0 678.06 0.595 678.2 ;
        END
    END tu_busy
    PIN tu_csr_addr[0]
        DIRECTION OUTPUT ; 
        USE SIGNAL ; 
        PORT
            LAYER met2 ;
              RECT  604.6 0 604.74 0.485 ;
        END
    END tu_csr_addr[0]
    PIN tu_csr_addr[1]
        DIRECTION OUTPUT ; 
        USE SIGNAL ; 
        PORT
            LAYER met1 ;
              RECT  0 134.74 0.595 134.88 ;
        END
    END tu_csr_addr[1]
    PIN tu_csr_wdata[0]
        DIRECTION OUTPUT ; 
        USE SIGNAL ; 
        PORT
            LAYER met1 ;
              RECT  705.88 302.02 706.475 302.16 ;
        END
    END tu_csr_wdata[0]
    PIN tu_csr_wdata[10]
        DIRECTION OUTPUT ; 
        USE SIGNAL ; 
        PORT
            LAYER met1 ;
              RECT  0 414.22 0.595 414.36 ;
        END
    END tu_csr_wdata[10]
    PIN tu_csr_wdata[11]
        DIRECTION OUTPUT ; 
        USE SIGNAL ; 
        PORT
            LAYER met2 ;
              RECT  676.36 705.99 676.5 706.475 ;
        END
    END tu_csr_wdata[11]
    PIN tu_csr_wdata[12]
        DIRECTION OUTPUT ; 
        USE SIGNAL ; 
        PORT
            LAYER met1 ;
              RECT  705.88 673.3 706.475 673.44 ;
        END
    END tu_csr_wdata[12]
    PIN tu_csr_wdata[13]
        DIRECTION OUTPUT ; 
        USE SIGNAL ; 
        PORT
            LAYER met1 ;
              RECT  705.88 560.42 706.475 560.56 ;
        END
    END tu_csr_wdata[13]
    PIN tu_csr_wdata[14]
        DIRECTION OUTPUT ; 
        USE SIGNAL ; 
        PORT
            LAYER met2 ;
              RECT  538.36 705.99 538.5 706.475 ;
        END
    END tu_csr_wdata[14]
    PIN tu_csr_wdata[15]
        DIRECTION OUTPUT ; 
        USE SIGNAL ; 
        PORT
            LAYER met1 ;
              RECT  0 608.02 0.595 608.16 ;
        END
    END tu_csr_wdata[15]
    PIN tu_csr_wdata[16]
        DIRECTION OUTPUT ; 
        USE SIGNAL ; 
        PORT
            LAYER met2 ;
              RECT  698.44 705.99 698.58 706.475 ;
        END
    END tu_csr_wdata[16]
    PIN tu_csr_wdata[17]
        DIRECTION OUTPUT ; 
        USE SIGNAL ; 
        PORT
            LAYER met1 ;
              RECT  0 199.34 0.595 199.48 ;
        END
    END tu_csr_wdata[17]
    PIN tu_csr_wdata[18]
        DIRECTION OUTPUT ; 
        USE SIGNAL ; 
        PORT
            LAYER met1 ;
              RECT  0 382.26 0.595 382.4 ;
        END
    END tu_csr_wdata[18]
    PIN tu_csr_wdata[19]
        DIRECTION OUTPUT ; 
        USE SIGNAL ; 
        PORT
            LAYER met1 ;
              RECT  0 430.54 0.595 430.68 ;
        END
    END tu_csr_wdata[19]
    PIN tu_csr_wdata[1]
        DIRECTION OUTPUT ; 
        USE SIGNAL ; 
        PORT
            LAYER met2 ;
              RECT  539.28 0 539.42 0.485 ;
        END
    END tu_csr_wdata[1]
    PIN tu_csr_wdata[20]
        DIRECTION OUTPUT ; 
        USE SIGNAL ; 
        PORT
            LAYER met1 ;
              RECT  0 554.3 0.595 554.44 ;
        END
    END tu_csr_wdata[20]
    PIN tu_csr_wdata[21]
        DIRECTION OUTPUT ; 
        USE SIGNAL ; 
        PORT
            LAYER met1 ;
              RECT  705.88 248.3 706.475 248.44 ;
        END
    END tu_csr_wdata[21]
    PIN tu_csr_wdata[22]
        DIRECTION OUTPUT ; 
        USE SIGNAL ; 
        PORT
            LAYER met2 ;
              RECT  36.04 705.99 36.18 706.475 ;
        END
    END tu_csr_wdata[22]
    PIN tu_csr_wdata[23]
        DIRECTION OUTPUT ; 
        USE SIGNAL ; 
        PORT
            LAYER met2 ;
              RECT  326.76 705.99 326.9 706.475 ;
        END
    END tu_csr_wdata[23]
    PIN tu_csr_wdata[24]
        DIRECTION OUTPUT ; 
        USE SIGNAL ; 
        PORT
            LAYER met1 ;
              RECT  705.88 135.42 706.475 135.56 ;
        END
    END tu_csr_wdata[24]
    PIN tu_csr_wdata[25]
        DIRECTION OUTPUT ; 
        USE SIGNAL ; 
        PORT
            LAYER met2 ;
              RECT  524.56 0 524.7 0.485 ;
        END
    END tu_csr_wdata[25]
    PIN tu_csr_wdata[26]
        DIRECTION OUTPUT ; 
        USE SIGNAL ; 
        PORT
            LAYER met2 ;
              RECT  146.44 0 146.58 0.485 ;
        END
    END tu_csr_wdata[26]
    PIN tu_csr_wdata[27]
        DIRECTION OUTPUT ; 
        USE SIGNAL ; 
        PORT
            LAYER met1 ;
              RECT  705.88 264.62 706.475 264.76 ;
        END
    END tu_csr_wdata[27]
    PIN tu_csr_wdata[28]
        DIRECTION OUTPUT ; 
        USE SIGNAL ; 
        PORT
            LAYER met1 ;
              RECT  705.88 662.42 706.475 662.56 ;
        END
    END tu_csr_wdata[28]
    PIN tu_csr_wdata[29]
        DIRECTION OUTPUT ; 
        USE SIGNAL ; 
        PORT
            LAYER met2 ;
              RECT  357.12 0 357.26 0.485 ;
        END
    END tu_csr_wdata[29]
    PIN tu_csr_wdata[2]
        DIRECTION OUTPUT ; 
        USE SIGNAL ; 
        PORT
            LAYER met2 ;
              RECT  268.8 705.99 268.94 706.475 ;
        END
    END tu_csr_wdata[2]
    PIN tu_csr_wdata[30]
        DIRECTION OUTPUT ; 
        USE SIGNAL ; 
        PORT
            LAYER met2 ;
              RECT  597.24 0 597.38 0.485 ;
        END
    END tu_csr_wdata[30]
    PIN tu_csr_wdata[31]
        DIRECTION OUTPUT ; 
        USE SIGNAL ; 
        PORT
            LAYER met1 ;
              RECT  705.88 469.3 706.475 469.44 ;
        END
    END tu_csr_wdata[31]
    PIN tu_csr_wdata[3]
        DIRECTION OUTPUT ; 
        USE SIGNAL ; 
        PORT
            LAYER met1 ;
              RECT  0 91.9 0.595 92.04 ;
        END
    END tu_csr_wdata[3]
    PIN tu_csr_wdata[4]
        DIRECTION OUTPUT ; 
        USE SIGNAL ; 
        PORT
            LAYER met2 ;
              RECT  276.16 705.99 276.3 706.475 ;
        END
    END tu_csr_wdata[4]
    PIN tu_csr_wdata[5]
        DIRECTION OUTPUT ; 
        USE SIGNAL ; 
        PORT
            LAYER met1 ;
              RECT  705.88 382.94 706.475 383.08 ;
        END
    END tu_csr_wdata[5]
    PIN tu_csr_wdata[6]
        DIRECTION OUTPUT ; 
        USE SIGNAL ; 
        PORT
            LAYER met2 ;
              RECT  151.96 705.99 152.1 706.475 ;
        END
    END tu_csr_wdata[6]
    PIN tu_csr_wdata[7]
        DIRECTION OUTPUT ; 
        USE SIGNAL ; 
        PORT
            LAYER met1 ;
              RECT  0 688.94 0.595 689.08 ;
        END
    END tu_csr_wdata[7]
    PIN tu_csr_wdata[8]
        DIRECTION OUTPUT ; 
        USE SIGNAL ; 
        PORT
            LAYER met1 ;
              RECT  705.88 538.66 706.475 538.8 ;
        END
    END tu_csr_wdata[8]
    PIN tu_csr_wdata[9]
        DIRECTION OUTPUT ; 
        USE SIGNAL ; 
        PORT
            LAYER met1 ;
              RECT  705.88 232.66 706.475 232.8 ;
        END
    END tu_csr_wdata[9]
    PIN tu_csr_we
        DIRECTION OUTPUT ; 
        USE SIGNAL ; 
        PORT
            LAYER met1 ;
              RECT  0 506.02 0.595 506.16 ;
        END
    END tu_csr_we
    PIN tu_kick
        DIRECTION OUTPUT ; 
        USE SIGNAL ; 
        PORT
            LAYER met1 ;
              RECT  705.88 393.82 706.475 393.96 ;
        END
    END tu_kick
    PIN VGND
        DIRECTION INOUT ; 
        USE GROUND ; 
        PORT
            LAYER met2 ;
              RECT  22.92 10.695 24.46 11.065 ;
        END
        PORT
            LAYER met2 ;
              RECT  22.92 696.135 24.46 696.505 ;
        END
        PORT
            LAYER met2 ;
              RECT  50.06 10.695 51.6 11.065 ;
        END
        PORT
            LAYER met2 ;
              RECT  50.06 696.135 51.6 696.505 ;
        END
        PORT
            LAYER met2 ;
              RECT  77.2 10.695 78.74 11.065 ;
        END
        PORT
            LAYER met2 ;
              RECT  77.2 696.135 78.74 696.505 ;
        END
        PORT
            LAYER met2 ;
              RECT  104.34 10.695 105.88 11.065 ;
        END
        PORT
            LAYER met2 ;
              RECT  104.34 696.135 105.88 696.505 ;
        END
        PORT
            LAYER met2 ;
              RECT  131.48 10.695 133.02 11.065 ;
        END
        PORT
            LAYER met2 ;
              RECT  131.48 696.135 133.02 696.505 ;
        END
        PORT
            LAYER met2 ;
              RECT  158.62 10.695 160.16 11.065 ;
        END
        PORT
            LAYER met2 ;
              RECT  158.62 696.135 160.16 696.505 ;
        END
        PORT
            LAYER met2 ;
              RECT  185.76 10.695 187.3 11.065 ;
        END
        PORT
            LAYER met2 ;
              RECT  185.76 696.135 187.3 696.505 ;
        END
        PORT
            LAYER met2 ;
              RECT  212.9 10.695 214.44 11.065 ;
        END
        PORT
            LAYER met2 ;
              RECT  212.9 696.135 214.44 696.505 ;
        END
        PORT
            LAYER met2 ;
              RECT  240.04 10.695 241.58 11.065 ;
        END
        PORT
            LAYER met2 ;
              RECT  240.04 696.135 241.58 696.505 ;
        END
        PORT
            LAYER met2 ;
              RECT  267.18 10.695 268.72 11.065 ;
        END
        PORT
            LAYER met2 ;
              RECT  267.18 696.135 268.72 696.505 ;
        END
        PORT
            LAYER met2 ;
              RECT  294.32 10.695 295.86 11.065 ;
        END
        PORT
            LAYER met2 ;
              RECT  294.32 696.135 295.86 696.505 ;
        END
        PORT
            LAYER met2 ;
              RECT  321.46 10.695 323 11.065 ;
        END
        PORT
            LAYER met2 ;
              RECT  321.46 696.135 323 696.505 ;
        END
        PORT
            LAYER met2 ;
              RECT  348.6 10.695 350.14 11.065 ;
        END
        PORT
            LAYER met2 ;
              RECT  348.6 696.135 350.14 696.505 ;
        END
        PORT
            LAYER met2 ;
              RECT  375.74 10.695 377.28 11.065 ;
        END
        PORT
            LAYER met2 ;
              RECT  375.74 696.135 377.28 696.505 ;
        END
        PORT
            LAYER met2 ;
              RECT  402.88 10.695 404.42 11.065 ;
        END
        PORT
            LAYER met2 ;
              RECT  402.88 696.135 404.42 696.505 ;
        END
        PORT
            LAYER met2 ;
              RECT  430.02 10.695 431.56 11.065 ;
        END
        PORT
            LAYER met2 ;
              RECT  430.02 696.135 431.56 696.505 ;
        END
        PORT
            LAYER met2 ;
              RECT  457.16 10.695 458.7 11.065 ;
        END
        PORT
            LAYER met2 ;
              RECT  457.16 696.135 458.7 696.505 ;
        END
        PORT
            LAYER met2 ;
              RECT  484.3 10.695 485.84 11.065 ;
        END
        PORT
            LAYER met2 ;
              RECT  484.3 696.135 485.84 696.505 ;
        END
        PORT
            LAYER met2 ;
              RECT  511.44 10.695 512.98 11.065 ;
        END
        PORT
            LAYER met2 ;
              RECT  511.44 696.135 512.98 696.505 ;
        END
        PORT
            LAYER met2 ;
              RECT  538.58 10.695 540.12 11.065 ;
        END
        PORT
            LAYER met2 ;
              RECT  538.58 696.135 540.12 696.505 ;
        END
        PORT
            LAYER met2 ;
              RECT  565.72 10.695 567.26 11.065 ;
        END
        PORT
            LAYER met2 ;
              RECT  565.72 696.135 567.26 696.505 ;
        END
        PORT
            LAYER met2 ;
              RECT  592.86 10.695 594.4 11.065 ;
        END
        PORT
            LAYER met2 ;
              RECT  592.86 696.135 594.4 696.505 ;
        END
        PORT
            LAYER met2 ;
              RECT  620 10.695 621.54 11.065 ;
        END
        PORT
            LAYER met2 ;
              RECT  620 696.135 621.54 696.505 ;
        END
        PORT
            LAYER met2 ;
              RECT  647.14 10.695 648.68 11.065 ;
        END
        PORT
            LAYER met2 ;
              RECT  647.14 696.135 648.68 696.505 ;
        END
        PORT
            LAYER met2 ;
              RECT  674.28 10.695 675.82 11.065 ;
        END
        PORT
            LAYER met2 ;
              RECT  674.28 696.135 675.82 696.505 ;
        END
        PORT
            LAYER met3 ;
              RECT  22.9 10.715 24.48 11.045 ;
        END
        PORT
            LAYER met3 ;
              RECT  22.9 696.155 24.48 696.485 ;
        END
        PORT
            LAYER met3 ;
              RECT  50.04 10.715 51.62 11.045 ;
        END
        PORT
            LAYER met3 ;
              RECT  50.04 696.155 51.62 696.485 ;
        END
        PORT
            LAYER met3 ;
              RECT  77.18 10.715 78.76 11.045 ;
        END
        PORT
            LAYER met3 ;
              RECT  77.18 696.155 78.76 696.485 ;
        END
        PORT
            LAYER met3 ;
              RECT  104.32 10.715 105.9 11.045 ;
        END
        PORT
            LAYER met3 ;
              RECT  104.32 696.155 105.9 696.485 ;
        END
        PORT
            LAYER met3 ;
              RECT  131.46 10.715 133.04 11.045 ;
        END
        PORT
            LAYER met3 ;
              RECT  131.46 696.155 133.04 696.485 ;
        END
        PORT
            LAYER met3 ;
              RECT  158.6 10.715 160.18 11.045 ;
        END
        PORT
            LAYER met3 ;
              RECT  158.6 696.155 160.18 696.485 ;
        END
        PORT
            LAYER met3 ;
              RECT  185.74 10.715 187.32 11.045 ;
        END
        PORT
            LAYER met3 ;
              RECT  185.74 696.155 187.32 696.485 ;
        END
        PORT
            LAYER met3 ;
              RECT  212.88 10.715 214.46 11.045 ;
        END
        PORT
            LAYER met3 ;
              RECT  212.88 696.155 214.46 696.485 ;
        END
        PORT
            LAYER met3 ;
              RECT  240.02 10.715 241.6 11.045 ;
        END
        PORT
            LAYER met3 ;
              RECT  240.02 696.155 241.6 696.485 ;
        END
        PORT
            LAYER met3 ;
              RECT  267.16 10.715 268.74 11.045 ;
        END
        PORT
            LAYER met3 ;
              RECT  267.16 696.155 268.74 696.485 ;
        END
        PORT
            LAYER met3 ;
              RECT  294.3 10.715 295.88 11.045 ;
        END
        PORT
            LAYER met3 ;
              RECT  294.3 696.155 295.88 696.485 ;
        END
        PORT
            LAYER met3 ;
              RECT  321.44 10.715 323.02 11.045 ;
        END
        PORT
            LAYER met3 ;
              RECT  321.44 696.155 323.02 696.485 ;
        END
        PORT
            LAYER met3 ;
              RECT  348.58 10.715 350.16 11.045 ;
        END
        PORT
            LAYER met3 ;
              RECT  348.58 696.155 350.16 696.485 ;
        END
        PORT
            LAYER met3 ;
              RECT  375.72 10.715 377.3 11.045 ;
        END
        PORT
            LAYER met3 ;
              RECT  375.72 696.155 377.3 696.485 ;
        END
        PORT
            LAYER met3 ;
              RECT  402.86 10.715 404.44 11.045 ;
        END
        PORT
            LAYER met3 ;
              RECT  402.86 696.155 404.44 696.485 ;
        END
        PORT
            LAYER met3 ;
              RECT  430 10.715 431.58 11.045 ;
        END
        PORT
            LAYER met3 ;
              RECT  430 696.155 431.58 696.485 ;
        END
        PORT
            LAYER met3 ;
              RECT  457.14 10.715 458.72 11.045 ;
        END
        PORT
            LAYER met3 ;
              RECT  457.14 696.155 458.72 696.485 ;
        END
        PORT
            LAYER met3 ;
              RECT  484.28 10.715 485.86 11.045 ;
        END
        PORT
            LAYER met3 ;
              RECT  484.28 696.155 485.86 696.485 ;
        END
        PORT
            LAYER met3 ;
              RECT  511.42 10.715 513 11.045 ;
        END
        PORT
            LAYER met3 ;
              RECT  511.42 696.155 513 696.485 ;
        END
        PORT
            LAYER met3 ;
              RECT  538.56 10.715 540.14 11.045 ;
        END
        PORT
            LAYER met3 ;
              RECT  538.56 696.155 540.14 696.485 ;
        END
        PORT
            LAYER met3 ;
              RECT  565.7 10.715 567.28 11.045 ;
        END
        PORT
            LAYER met3 ;
              RECT  565.7 696.155 567.28 696.485 ;
        END
        PORT
            LAYER met3 ;
              RECT  592.84 10.715 594.42 11.045 ;
        END
        PORT
            LAYER met3 ;
              RECT  592.84 696.155 594.42 696.485 ;
        END
        PORT
            LAYER met3 ;
              RECT  619.98 10.715 621.56 11.045 ;
        END
        PORT
            LAYER met3 ;
              RECT  619.98 696.155 621.56 696.485 ;
        END
        PORT
            LAYER met3 ;
              RECT  647.12 10.715 648.7 11.045 ;
        END
        PORT
            LAYER met3 ;
              RECT  647.12 696.155 648.7 696.485 ;
        END
        PORT
            LAYER met3 ;
              RECT  674.26 10.715 675.84 11.045 ;
        END
        PORT
            LAYER met3 ;
              RECT  674.26 696.155 675.84 696.485 ;
        END
        PORT
            LAYER met1 ;
              RECT  10.12 10.64 696.44 11.12 ;
        END
        PORT
            LAYER met1 ;
              RECT  694.44 10.64 696.44 11.12 ;
        END
        PORT
            LAYER met1 ;
              RECT  10.12 10.64 12.12 11.12 ;
        END
        PORT
            LAYER met1 ;
              RECT  694.44 16.08 696.44 16.56 ;
        END
        PORT
            LAYER met1 ;
              RECT  10.12 16.08 12.12 16.56 ;
        END
        PORT
            LAYER met1 ;
              RECT  694.44 21.52 696.44 22 ;
        END
        PORT
            LAYER met1 ;
              RECT  10.12 21.52 12.12 22 ;
        END
        PORT
            LAYER met1 ;
              RECT  694.44 26.96 696.44 27.44 ;
        END
        PORT
            LAYER met1 ;
              RECT  10.12 26.96 12.12 27.44 ;
        END
        PORT
            LAYER met1 ;
              RECT  694.44 32.4 696.44 32.88 ;
        END
        PORT
            LAYER met1 ;
              RECT  10.12 32.4 12.12 32.88 ;
        END
        PORT
            LAYER met1 ;
              RECT  694.44 37.84 696.44 38.32 ;
        END
        PORT
            LAYER met1 ;
              RECT  10.12 37.84 12.12 38.32 ;
        END
        PORT
            LAYER met1 ;
              RECT  694.44 43.28 696.44 43.76 ;
        END
        PORT
            LAYER met1 ;
              RECT  10.12 43.28 12.12 43.76 ;
        END
        PORT
            LAYER met1 ;
              RECT  694.44 48.72 696.44 49.2 ;
        END
        PORT
            LAYER met1 ;
              RECT  10.12 48.72 12.12 49.2 ;
        END
        PORT
            LAYER met1 ;
              RECT  694.44 54.16 696.44 54.64 ;
        END
        PORT
            LAYER met1 ;
              RECT  10.12 54.16 12.12 54.64 ;
        END
        PORT
            LAYER met1 ;
              RECT  694.44 59.6 696.44 60.08 ;
        END
        PORT
            LAYER met1 ;
              RECT  10.12 59.6 12.12 60.08 ;
        END
        PORT
            LAYER met1 ;
              RECT  694.44 65.04 696.44 65.52 ;
        END
        PORT
            LAYER met1 ;
              RECT  10.12 65.04 12.12 65.52 ;
        END
        PORT
            LAYER met1 ;
              RECT  694.44 70.48 696.44 70.96 ;
        END
        PORT
            LAYER met1 ;
              RECT  10.12 70.48 12.12 70.96 ;
        END
        PORT
            LAYER met1 ;
              RECT  694.44 75.92 696.44 76.4 ;
        END
        PORT
            LAYER met1 ;
              RECT  10.12 75.92 12.12 76.4 ;
        END
        PORT
            LAYER met1 ;
              RECT  694.44 81.36 696.44 81.84 ;
        END
        PORT
            LAYER met1 ;
              RECT  10.12 81.36 12.12 81.84 ;
        END
        PORT
            LAYER met1 ;
              RECT  694.44 86.8 696.44 87.28 ;
        END
        PORT
            LAYER met1 ;
              RECT  10.12 86.8 12.12 87.28 ;
        END
        PORT
            LAYER met1 ;
              RECT  694.44 92.24 696.44 92.72 ;
        END
        PORT
            LAYER met1 ;
              RECT  10.12 92.24 12.12 92.72 ;
        END
        PORT
            LAYER met1 ;
              RECT  694.44 97.68 696.44 98.16 ;
        END
        PORT
            LAYER met1 ;
              RECT  10.12 97.68 12.12 98.16 ;
        END
        PORT
            LAYER met1 ;
              RECT  694.44 103.12 696.44 103.6 ;
        END
        PORT
            LAYER met1 ;
              RECT  10.12 103.12 12.12 103.6 ;
        END
        PORT
            LAYER met1 ;
              RECT  694.44 108.56 696.44 109.04 ;
        END
        PORT
            LAYER met1 ;
              RECT  10.12 108.56 12.12 109.04 ;
        END
        PORT
            LAYER met1 ;
              RECT  694.44 114 696.44 114.48 ;
        END
        PORT
            LAYER met1 ;
              RECT  10.12 114 12.12 114.48 ;
        END
        PORT
            LAYER met1 ;
              RECT  694.44 119.44 696.44 119.92 ;
        END
        PORT
            LAYER met1 ;
              RECT  10.12 119.44 12.12 119.92 ;
        END
        PORT
            LAYER met1 ;
              RECT  694.44 124.88 696.44 125.36 ;
        END
        PORT
            LAYER met1 ;
              RECT  10.12 124.88 12.12 125.36 ;
        END
        PORT
            LAYER met1 ;
              RECT  694.44 130.32 696.44 130.8 ;
        END
        PORT
            LAYER met1 ;
              RECT  10.12 130.32 12.12 130.8 ;
        END
        PORT
            LAYER met1 ;
              RECT  694.44 135.76 696.44 136.24 ;
        END
        PORT
            LAYER met1 ;
              RECT  10.12 135.76 12.12 136.24 ;
        END
        PORT
            LAYER met1 ;
              RECT  694.44 141.2 696.44 141.68 ;
        END
        PORT
            LAYER met1 ;
              RECT  10.12 141.2 12.12 141.68 ;
        END
        PORT
            LAYER met1 ;
              RECT  694.44 146.64 696.44 147.12 ;
        END
        PORT
            LAYER met1 ;
              RECT  10.12 146.64 12.12 147.12 ;
        END
        PORT
            LAYER met1 ;
              RECT  694.44 152.08 696.44 152.56 ;
        END
        PORT
            LAYER met1 ;
              RECT  10.12 152.08 12.12 152.56 ;
        END
        PORT
            LAYER met1 ;
              RECT  694.44 157.52 696.44 158 ;
        END
        PORT
            LAYER met1 ;
              RECT  10.12 157.52 12.12 158 ;
        END
        PORT
            LAYER met1 ;
              RECT  694.44 162.96 696.44 163.44 ;
        END
        PORT
            LAYER met1 ;
              RECT  10.12 162.96 12.12 163.44 ;
        END
        PORT
            LAYER met1 ;
              RECT  694.44 168.4 696.44 168.88 ;
        END
        PORT
            LAYER met1 ;
              RECT  10.12 168.4 12.12 168.88 ;
        END
        PORT
            LAYER met1 ;
              RECT  694.44 173.84 696.44 174.32 ;
        END
        PORT
            LAYER met1 ;
              RECT  10.12 173.84 12.12 174.32 ;
        END
        PORT
            LAYER met1 ;
              RECT  694.44 179.28 696.44 179.76 ;
        END
        PORT
            LAYER met1 ;
              RECT  10.12 179.28 12.12 179.76 ;
        END
        PORT
            LAYER met1 ;
              RECT  694.44 184.72 696.44 185.2 ;
        END
        PORT
            LAYER met1 ;
              RECT  10.12 184.72 12.12 185.2 ;
        END
        PORT
            LAYER met1 ;
              RECT  694.44 190.16 696.44 190.64 ;
        END
        PORT
            LAYER met1 ;
              RECT  10.12 190.16 12.12 190.64 ;
        END
        PORT
            LAYER met1 ;
              RECT  694.44 195.6 696.44 196.08 ;
        END
        PORT
            LAYER met1 ;
              RECT  10.12 195.6 12.12 196.08 ;
        END
        PORT
            LAYER met1 ;
              RECT  694.44 201.04 696.44 201.52 ;
        END
        PORT
            LAYER met1 ;
              RECT  10.12 201.04 12.12 201.52 ;
        END
        PORT
            LAYER met1 ;
              RECT  694.44 206.48 696.44 206.96 ;
        END
        PORT
            LAYER met1 ;
              RECT  10.12 206.48 12.12 206.96 ;
        END
        PORT
            LAYER met1 ;
              RECT  694.44 211.92 696.44 212.4 ;
        END
        PORT
            LAYER met1 ;
              RECT  10.12 211.92 12.12 212.4 ;
        END
        PORT
            LAYER met1 ;
              RECT  694.44 217.36 696.44 217.84 ;
        END
        PORT
            LAYER met1 ;
              RECT  10.12 217.36 12.12 217.84 ;
        END
        PORT
            LAYER met1 ;
              RECT  694.44 222.8 696.44 223.28 ;
        END
        PORT
            LAYER met1 ;
              RECT  10.12 222.8 12.12 223.28 ;
        END
        PORT
            LAYER met1 ;
              RECT  694.44 228.24 696.44 228.72 ;
        END
        PORT
            LAYER met1 ;
              RECT  10.12 228.24 12.12 228.72 ;
        END
        PORT
            LAYER met1 ;
              RECT  694.44 233.68 696.44 234.16 ;
        END
        PORT
            LAYER met1 ;
              RECT  10.12 233.68 12.12 234.16 ;
        END
        PORT
            LAYER met1 ;
              RECT  694.44 239.12 696.44 239.6 ;
        END
        PORT
            LAYER met1 ;
              RECT  10.12 239.12 12.12 239.6 ;
        END
        PORT
            LAYER met1 ;
              RECT  694.44 244.56 696.44 245.04 ;
        END
        PORT
            LAYER met1 ;
              RECT  10.12 244.56 12.12 245.04 ;
        END
        PORT
            LAYER met1 ;
              RECT  694.44 250 696.44 250.48 ;
        END
        PORT
            LAYER met1 ;
              RECT  10.12 250 12.12 250.48 ;
        END
        PORT
            LAYER met1 ;
              RECT  694.44 255.44 696.44 255.92 ;
        END
        PORT
            LAYER met1 ;
              RECT  10.12 255.44 12.12 255.92 ;
        END
        PORT
            LAYER met1 ;
              RECT  694.44 260.88 696.44 261.36 ;
        END
        PORT
            LAYER met1 ;
              RECT  10.12 260.88 12.12 261.36 ;
        END
        PORT
            LAYER met1 ;
              RECT  694.44 266.32 696.44 266.8 ;
        END
        PORT
            LAYER met1 ;
              RECT  10.12 266.32 12.12 266.8 ;
        END
        PORT
            LAYER met1 ;
              RECT  694.44 271.76 696.44 272.24 ;
        END
        PORT
            LAYER met1 ;
              RECT  10.12 271.76 12.12 272.24 ;
        END
        PORT
            LAYER met1 ;
              RECT  694.44 277.2 696.44 277.68 ;
        END
        PORT
            LAYER met1 ;
              RECT  10.12 277.2 12.12 277.68 ;
        END
        PORT
            LAYER met1 ;
              RECT  694.44 282.64 696.44 283.12 ;
        END
        PORT
            LAYER met1 ;
              RECT  10.12 282.64 12.12 283.12 ;
        END
        PORT
            LAYER met1 ;
              RECT  694.44 288.08 696.44 288.56 ;
        END
        PORT
            LAYER met1 ;
              RECT  10.12 288.08 12.12 288.56 ;
        END
        PORT
            LAYER met1 ;
              RECT  694.44 293.52 696.44 294 ;
        END
        PORT
            LAYER met1 ;
              RECT  10.12 293.52 12.12 294 ;
        END
        PORT
            LAYER met1 ;
              RECT  694.44 298.96 696.44 299.44 ;
        END
        PORT
            LAYER met1 ;
              RECT  10.12 298.96 12.12 299.44 ;
        END
        PORT
            LAYER met1 ;
              RECT  694.44 304.4 696.44 304.88 ;
        END
        PORT
            LAYER met1 ;
              RECT  10.12 304.4 12.12 304.88 ;
        END
        PORT
            LAYER met1 ;
              RECT  694.44 309.84 696.44 310.32 ;
        END
        PORT
            LAYER met1 ;
              RECT  10.12 309.84 12.12 310.32 ;
        END
        PORT
            LAYER met1 ;
              RECT  694.44 315.28 696.44 315.76 ;
        END
        PORT
            LAYER met1 ;
              RECT  10.12 315.28 12.12 315.76 ;
        END
        PORT
            LAYER met1 ;
              RECT  694.44 320.72 696.44 321.2 ;
        END
        PORT
            LAYER met1 ;
              RECT  10.12 320.72 12.12 321.2 ;
        END
        PORT
            LAYER met1 ;
              RECT  694.44 326.16 696.44 326.64 ;
        END
        PORT
            LAYER met1 ;
              RECT  10.12 326.16 12.12 326.64 ;
        END
        PORT
            LAYER met1 ;
              RECT  694.44 331.6 696.44 332.08 ;
        END
        PORT
            LAYER met1 ;
              RECT  10.12 331.6 12.12 332.08 ;
        END
        PORT
            LAYER met1 ;
              RECT  694.44 337.04 696.44 337.52 ;
        END
        PORT
            LAYER met1 ;
              RECT  10.12 337.04 12.12 337.52 ;
        END
        PORT
            LAYER met1 ;
              RECT  694.44 342.48 696.44 342.96 ;
        END
        PORT
            LAYER met1 ;
              RECT  10.12 342.48 12.12 342.96 ;
        END
        PORT
            LAYER met1 ;
              RECT  694.44 347.92 696.44 348.4 ;
        END
        PORT
            LAYER met1 ;
              RECT  10.12 347.92 12.12 348.4 ;
        END
        PORT
            LAYER met1 ;
              RECT  694.44 353.36 696.44 353.84 ;
        END
        PORT
            LAYER met1 ;
              RECT  10.12 353.36 12.12 353.84 ;
        END
        PORT
            LAYER met1 ;
              RECT  694.44 358.8 696.44 359.28 ;
        END
        PORT
            LAYER met1 ;
              RECT  10.12 358.8 12.12 359.28 ;
        END
        PORT
            LAYER met1 ;
              RECT  694.44 364.24 696.44 364.72 ;
        END
        PORT
            LAYER met1 ;
              RECT  10.12 364.24 12.12 364.72 ;
        END
        PORT
            LAYER met1 ;
              RECT  694.44 369.68 696.44 370.16 ;
        END
        PORT
            LAYER met1 ;
              RECT  10.12 369.68 12.12 370.16 ;
        END
        PORT
            LAYER met1 ;
              RECT  694.44 375.12 696.44 375.6 ;
        END
        PORT
            LAYER met1 ;
              RECT  10.12 375.12 12.12 375.6 ;
        END
        PORT
            LAYER met1 ;
              RECT  694.44 380.56 696.44 381.04 ;
        END
        PORT
            LAYER met1 ;
              RECT  10.12 380.56 12.12 381.04 ;
        END
        PORT
            LAYER met1 ;
              RECT  694.44 386 696.44 386.48 ;
        END
        PORT
            LAYER met1 ;
              RECT  10.12 386 12.12 386.48 ;
        END
        PORT
            LAYER met1 ;
              RECT  694.44 391.44 696.44 391.92 ;
        END
        PORT
            LAYER met1 ;
              RECT  10.12 391.44 12.12 391.92 ;
        END
        PORT
            LAYER met1 ;
              RECT  694.44 396.88 696.44 397.36 ;
        END
        PORT
            LAYER met1 ;
              RECT  10.12 396.88 12.12 397.36 ;
        END
        PORT
            LAYER met1 ;
              RECT  694.44 402.32 696.44 402.8 ;
        END
        PORT
            LAYER met1 ;
              RECT  10.12 402.32 12.12 402.8 ;
        END
        PORT
            LAYER met1 ;
              RECT  694.44 407.76 696.44 408.24 ;
        END
        PORT
            LAYER met1 ;
              RECT  10.12 407.76 12.12 408.24 ;
        END
        PORT
            LAYER met1 ;
              RECT  694.44 413.2 696.44 413.68 ;
        END
        PORT
            LAYER met1 ;
              RECT  10.12 413.2 12.12 413.68 ;
        END
        PORT
            LAYER met1 ;
              RECT  694.44 418.64 696.44 419.12 ;
        END
        PORT
            LAYER met1 ;
              RECT  10.12 418.64 12.12 419.12 ;
        END
        PORT
            LAYER met1 ;
              RECT  694.44 424.08 696.44 424.56 ;
        END
        PORT
            LAYER met1 ;
              RECT  10.12 424.08 12.12 424.56 ;
        END
        PORT
            LAYER met1 ;
              RECT  694.44 429.52 696.44 430 ;
        END
        PORT
            LAYER met1 ;
              RECT  10.12 429.52 12.12 430 ;
        END
        PORT
            LAYER met1 ;
              RECT  694.44 434.96 696.44 435.44 ;
        END
        PORT
            LAYER met1 ;
              RECT  10.12 434.96 12.12 435.44 ;
        END
        PORT
            LAYER met1 ;
              RECT  694.44 440.4 696.44 440.88 ;
        END
        PORT
            LAYER met1 ;
              RECT  10.12 440.4 12.12 440.88 ;
        END
        PORT
            LAYER met1 ;
              RECT  694.44 445.84 696.44 446.32 ;
        END
        PORT
            LAYER met1 ;
              RECT  10.12 445.84 12.12 446.32 ;
        END
        PORT
            LAYER met1 ;
              RECT  694.44 451.28 696.44 451.76 ;
        END
        PORT
            LAYER met1 ;
              RECT  10.12 451.28 12.12 451.76 ;
        END
        PORT
            LAYER met1 ;
              RECT  694.44 456.72 696.44 457.2 ;
        END
        PORT
            LAYER met1 ;
              RECT  10.12 456.72 12.12 457.2 ;
        END
        PORT
            LAYER met1 ;
              RECT  694.44 462.16 696.44 462.64 ;
        END
        PORT
            LAYER met1 ;
              RECT  10.12 462.16 12.12 462.64 ;
        END
        PORT
            LAYER met1 ;
              RECT  694.44 467.6 696.44 468.08 ;
        END
        PORT
            LAYER met1 ;
              RECT  10.12 467.6 12.12 468.08 ;
        END
        PORT
            LAYER met1 ;
              RECT  694.44 473.04 696.44 473.52 ;
        END
        PORT
            LAYER met1 ;
              RECT  10.12 473.04 12.12 473.52 ;
        END
        PORT
            LAYER met1 ;
              RECT  694.44 478.48 696.44 478.96 ;
        END
        PORT
            LAYER met1 ;
              RECT  10.12 478.48 12.12 478.96 ;
        END
        PORT
            LAYER met1 ;
              RECT  694.44 483.92 696.44 484.4 ;
        END
        PORT
            LAYER met1 ;
              RECT  10.12 483.92 12.12 484.4 ;
        END
        PORT
            LAYER met1 ;
              RECT  694.44 489.36 696.44 489.84 ;
        END
        PORT
            LAYER met1 ;
              RECT  10.12 489.36 12.12 489.84 ;
        END
        PORT
            LAYER met1 ;
              RECT  694.44 494.8 696.44 495.28 ;
        END
        PORT
            LAYER met1 ;
              RECT  10.12 494.8 12.12 495.28 ;
        END
        PORT
            LAYER met1 ;
              RECT  694.44 500.24 696.44 500.72 ;
        END
        PORT
            LAYER met1 ;
              RECT  10.12 500.24 12.12 500.72 ;
        END
        PORT
            LAYER met1 ;
              RECT  694.44 505.68 696.44 506.16 ;
        END
        PORT
            LAYER met1 ;
              RECT  10.12 505.68 12.12 506.16 ;
        END
        PORT
            LAYER met1 ;
              RECT  694.44 511.12 696.44 511.6 ;
        END
        PORT
            LAYER met1 ;
              RECT  10.12 511.12 12.12 511.6 ;
        END
        PORT
            LAYER met1 ;
              RECT  694.44 516.56 696.44 517.04 ;
        END
        PORT
            LAYER met1 ;
              RECT  10.12 516.56 12.12 517.04 ;
        END
        PORT
            LAYER met1 ;
              RECT  694.44 522 696.44 522.48 ;
        END
        PORT
            LAYER met1 ;
              RECT  10.12 522 12.12 522.48 ;
        END
        PORT
            LAYER met1 ;
              RECT  694.44 527.44 696.44 527.92 ;
        END
        PORT
            LAYER met1 ;
              RECT  10.12 527.44 12.12 527.92 ;
        END
        PORT
            LAYER met1 ;
              RECT  694.44 532.88 696.44 533.36 ;
        END
        PORT
            LAYER met1 ;
              RECT  10.12 532.88 12.12 533.36 ;
        END
        PORT
            LAYER met1 ;
              RECT  694.44 538.32 696.44 538.8 ;
        END
        PORT
            LAYER met1 ;
              RECT  10.12 538.32 12.12 538.8 ;
        END
        PORT
            LAYER met1 ;
              RECT  694.44 543.76 696.44 544.24 ;
        END
        PORT
            LAYER met1 ;
              RECT  10.12 543.76 12.12 544.24 ;
        END
        PORT
            LAYER met1 ;
              RECT  694.44 549.2 696.44 549.68 ;
        END
        PORT
            LAYER met1 ;
              RECT  10.12 549.2 12.12 549.68 ;
        END
        PORT
            LAYER met1 ;
              RECT  694.44 554.64 696.44 555.12 ;
        END
        PORT
            LAYER met1 ;
              RECT  10.12 554.64 12.12 555.12 ;
        END
        PORT
            LAYER met1 ;
              RECT  694.44 560.08 696.44 560.56 ;
        END
        PORT
            LAYER met1 ;
              RECT  10.12 560.08 12.12 560.56 ;
        END
        PORT
            LAYER met1 ;
              RECT  694.44 565.52 696.44 566 ;
        END
        PORT
            LAYER met1 ;
              RECT  10.12 565.52 12.12 566 ;
        END
        PORT
            LAYER met1 ;
              RECT  694.44 570.96 696.44 571.44 ;
        END
        PORT
            LAYER met1 ;
              RECT  10.12 570.96 12.12 571.44 ;
        END
        PORT
            LAYER met1 ;
              RECT  694.44 576.4 696.44 576.88 ;
        END
        PORT
            LAYER met1 ;
              RECT  10.12 576.4 12.12 576.88 ;
        END
        PORT
            LAYER met1 ;
              RECT  694.44 581.84 696.44 582.32 ;
        END
        PORT
            LAYER met1 ;
              RECT  10.12 581.84 12.12 582.32 ;
        END
        PORT
            LAYER met1 ;
              RECT  694.44 587.28 696.44 587.76 ;
        END
        PORT
            LAYER met1 ;
              RECT  10.12 587.28 12.12 587.76 ;
        END
        PORT
            LAYER met1 ;
              RECT  694.44 592.72 696.44 593.2 ;
        END
        PORT
            LAYER met1 ;
              RECT  10.12 592.72 12.12 593.2 ;
        END
        PORT
            LAYER met1 ;
              RECT  694.44 598.16 696.44 598.64 ;
        END
        PORT
            LAYER met1 ;
              RECT  10.12 598.16 12.12 598.64 ;
        END
        PORT
            LAYER met1 ;
              RECT  694.44 603.6 696.44 604.08 ;
        END
        PORT
            LAYER met1 ;
              RECT  10.12 603.6 12.12 604.08 ;
        END
        PORT
            LAYER met1 ;
              RECT  694.44 609.04 696.44 609.52 ;
        END
        PORT
            LAYER met1 ;
              RECT  10.12 609.04 12.12 609.52 ;
        END
        PORT
            LAYER met1 ;
              RECT  694.44 614.48 696.44 614.96 ;
        END
        PORT
            LAYER met1 ;
              RECT  10.12 614.48 12.12 614.96 ;
        END
        PORT
            LAYER met1 ;
              RECT  694.44 619.92 696.44 620.4 ;
        END
        PORT
            LAYER met1 ;
              RECT  10.12 619.92 12.12 620.4 ;
        END
        PORT
            LAYER met1 ;
              RECT  694.44 625.36 696.44 625.84 ;
        END
        PORT
            LAYER met1 ;
              RECT  10.12 625.36 12.12 625.84 ;
        END
        PORT
            LAYER met1 ;
              RECT  694.44 630.8 696.44 631.28 ;
        END
        PORT
            LAYER met1 ;
              RECT  10.12 630.8 12.12 631.28 ;
        END
        PORT
            LAYER met1 ;
              RECT  694.44 636.24 696.44 636.72 ;
        END
        PORT
            LAYER met1 ;
              RECT  10.12 636.24 12.12 636.72 ;
        END
        PORT
            LAYER met1 ;
              RECT  694.44 641.68 696.44 642.16 ;
        END
        PORT
            LAYER met1 ;
              RECT  10.12 641.68 12.12 642.16 ;
        END
        PORT
            LAYER met1 ;
              RECT  694.44 647.12 696.44 647.6 ;
        END
        PORT
            LAYER met1 ;
              RECT  10.12 647.12 12.12 647.6 ;
        END
        PORT
            LAYER met1 ;
              RECT  694.44 652.56 696.44 653.04 ;
        END
        PORT
            LAYER met1 ;
              RECT  10.12 652.56 12.12 653.04 ;
        END
        PORT
            LAYER met1 ;
              RECT  694.44 658 696.44 658.48 ;
        END
        PORT
            LAYER met1 ;
              RECT  10.12 658 12.12 658.48 ;
        END
        PORT
            LAYER met1 ;
              RECT  694.44 663.44 696.44 663.92 ;
        END
        PORT
            LAYER met1 ;
              RECT  10.12 663.44 12.12 663.92 ;
        END
        PORT
            LAYER met1 ;
              RECT  694.44 668.88 696.44 669.36 ;
        END
        PORT
            LAYER met1 ;
              RECT  10.12 668.88 12.12 669.36 ;
        END
        PORT
            LAYER met1 ;
              RECT  694.44 674.32 696.44 674.8 ;
        END
        PORT
            LAYER met1 ;
              RECT  10.12 674.32 12.12 674.8 ;
        END
        PORT
            LAYER met1 ;
              RECT  694.44 679.76 696.44 680.24 ;
        END
        PORT
            LAYER met1 ;
              RECT  10.12 679.76 12.12 680.24 ;
        END
        PORT
            LAYER met1 ;
              RECT  694.44 685.2 696.44 685.68 ;
        END
        PORT
            LAYER met1 ;
              RECT  10.12 685.2 12.12 685.68 ;
        END
        PORT
            LAYER met1 ;
              RECT  694.44 690.64 696.44 691.12 ;
        END
        PORT
            LAYER met1 ;
              RECT  10.12 690.64 12.12 691.12 ;
        END
        PORT
            LAYER met1 ;
              RECT  10.12 696.08 696.44 696.56 ;
        END
        PORT
            LAYER met1 ;
              RECT  694.44 696.08 696.44 696.56 ;
        END
        PORT
            LAYER met1 ;
              RECT  10.12 696.08 12.12 696.56 ;
        END
        PORT
            LAYER met4 ;
              RECT  22.89 694.56 24.49 696.56 ;
        END
        PORT
            LAYER met4 ;
              RECT  22.89 10.64 24.49 12.64 ;
        END
        PORT
            LAYER met4 ;
              RECT  50.03 694.56 51.63 696.56 ;
        END
        PORT
            LAYER met4 ;
              RECT  50.03 10.64 51.63 12.64 ;
        END
        PORT
            LAYER met4 ;
              RECT  77.17 694.56 78.77 696.56 ;
        END
        PORT
            LAYER met4 ;
              RECT  77.17 10.64 78.77 12.64 ;
        END
        PORT
            LAYER met4 ;
              RECT  104.31 694.56 105.91 696.56 ;
        END
        PORT
            LAYER met4 ;
              RECT  104.31 10.64 105.91 12.64 ;
        END
        PORT
            LAYER met4 ;
              RECT  131.45 694.56 133.05 696.56 ;
        END
        PORT
            LAYER met4 ;
              RECT  131.45 10.64 133.05 12.64 ;
        END
        PORT
            LAYER met4 ;
              RECT  158.59 694.56 160.19 696.56 ;
        END
        PORT
            LAYER met4 ;
              RECT  158.59 10.64 160.19 12.64 ;
        END
        PORT
            LAYER met4 ;
              RECT  185.73 694.56 187.33 696.56 ;
        END
        PORT
            LAYER met4 ;
              RECT  185.73 10.64 187.33 12.64 ;
        END
        PORT
            LAYER met4 ;
              RECT  212.87 694.56 214.47 696.56 ;
        END
        PORT
            LAYER met4 ;
              RECT  212.87 10.64 214.47 12.64 ;
        END
        PORT
            LAYER met4 ;
              RECT  240.01 694.56 241.61 696.56 ;
        END
        PORT
            LAYER met4 ;
              RECT  240.01 10.64 241.61 12.64 ;
        END
        PORT
            LAYER met4 ;
              RECT  267.15 694.56 268.75 696.56 ;
        END
        PORT
            LAYER met4 ;
              RECT  267.15 10.64 268.75 12.64 ;
        END
        PORT
            LAYER met4 ;
              RECT  294.29 694.56 295.89 696.56 ;
        END
        PORT
            LAYER met4 ;
              RECT  294.29 10.64 295.89 12.64 ;
        END
        PORT
            LAYER met4 ;
              RECT  321.43 694.56 323.03 696.56 ;
        END
        PORT
            LAYER met4 ;
              RECT  321.43 10.64 323.03 12.64 ;
        END
        PORT
            LAYER met4 ;
              RECT  348.57 694.56 350.17 696.56 ;
        END
        PORT
            LAYER met4 ;
              RECT  348.57 10.64 350.17 12.64 ;
        END
        PORT
            LAYER met4 ;
              RECT  375.71 694.56 377.31 696.56 ;
        END
        PORT
            LAYER met4 ;
              RECT  375.71 10.64 377.31 12.64 ;
        END
        PORT
            LAYER met4 ;
              RECT  402.85 694.56 404.45 696.56 ;
        END
        PORT
            LAYER met4 ;
              RECT  402.85 10.64 404.45 12.64 ;
        END
        PORT
            LAYER met4 ;
              RECT  429.99 694.56 431.59 696.56 ;
        END
        PORT
            LAYER met4 ;
              RECT  429.99 10.64 431.59 12.64 ;
        END
        PORT
            LAYER met4 ;
              RECT  457.13 694.56 458.73 696.56 ;
        END
        PORT
            LAYER met4 ;
              RECT  457.13 10.64 458.73 12.64 ;
        END
        PORT
            LAYER met4 ;
              RECT  484.27 694.56 485.87 696.56 ;
        END
        PORT
            LAYER met4 ;
              RECT  484.27 10.64 485.87 12.64 ;
        END
        PORT
            LAYER met4 ;
              RECT  511.41 694.56 513.01 696.56 ;
        END
        PORT
            LAYER met4 ;
              RECT  511.41 10.64 513.01 12.64 ;
        END
        PORT
            LAYER met4 ;
              RECT  538.55 694.56 540.15 696.56 ;
        END
        PORT
            LAYER met4 ;
              RECT  538.55 10.64 540.15 12.64 ;
        END
        PORT
            LAYER met4 ;
              RECT  565.69 694.56 567.29 696.56 ;
        END
        PORT
            LAYER met4 ;
              RECT  565.69 10.64 567.29 12.64 ;
        END
        PORT
            LAYER met4 ;
              RECT  592.83 694.56 594.43 696.56 ;
        END
        PORT
            LAYER met4 ;
              RECT  592.83 10.64 594.43 12.64 ;
        END
        PORT
            LAYER met4 ;
              RECT  619.97 694.56 621.57 696.56 ;
        END
        PORT
            LAYER met4 ;
              RECT  619.97 10.64 621.57 12.64 ;
        END
        PORT
            LAYER met4 ;
              RECT  647.11 694.56 648.71 696.56 ;
        END
        PORT
            LAYER met4 ;
              RECT  647.11 10.64 648.71 12.64 ;
        END
        PORT
            LAYER met4 ;
              RECT  674.25 694.56 675.85 696.56 ;
        END
        PORT
            LAYER met4 ;
              RECT  674.25 10.64 675.85 12.64 ;
        END
    END VGND
    PIN VPWR
        DIRECTION INOUT ; 
        USE POWER ; 
        PORT
            LAYER met1 ;
              RECT  694.44 13.36 696.44 13.84 ;
        END
        PORT
            LAYER met1 ;
              RECT  10.12 13.36 12.12 13.84 ;
        END
        PORT
            LAYER met1 ;
              RECT  694.44 18.8 696.44 19.28 ;
        END
        PORT
            LAYER met1 ;
              RECT  10.12 18.8 12.12 19.28 ;
        END
        PORT
            LAYER met1 ;
              RECT  694.44 24.24 696.44 24.72 ;
        END
        PORT
            LAYER met1 ;
              RECT  10.12 24.24 12.12 24.72 ;
        END
        PORT
            LAYER met1 ;
              RECT  694.44 29.68 696.44 30.16 ;
        END
        PORT
            LAYER met1 ;
              RECT  10.12 29.68 12.12 30.16 ;
        END
        PORT
            LAYER met1 ;
              RECT  694.44 35.12 696.44 35.6 ;
        END
        PORT
            LAYER met1 ;
              RECT  10.12 35.12 12.12 35.6 ;
        END
        PORT
            LAYER met1 ;
              RECT  694.44 40.56 696.44 41.04 ;
        END
        PORT
            LAYER met1 ;
              RECT  10.12 40.56 12.12 41.04 ;
        END
        PORT
            LAYER met1 ;
              RECT  694.44 46 696.44 46.48 ;
        END
        PORT
            LAYER met1 ;
              RECT  10.12 46 12.12 46.48 ;
        END
        PORT
            LAYER met1 ;
              RECT  694.44 51.44 696.44 51.92 ;
        END
        PORT
            LAYER met1 ;
              RECT  10.12 51.44 12.12 51.92 ;
        END
        PORT
            LAYER met1 ;
              RECT  694.44 56.88 696.44 57.36 ;
        END
        PORT
            LAYER met1 ;
              RECT  10.12 56.88 12.12 57.36 ;
        END
        PORT
            LAYER met1 ;
              RECT  694.44 62.32 696.44 62.8 ;
        END
        PORT
            LAYER met1 ;
              RECT  10.12 62.32 12.12 62.8 ;
        END
        PORT
            LAYER met1 ;
              RECT  694.44 67.76 696.44 68.24 ;
        END
        PORT
            LAYER met1 ;
              RECT  10.12 67.76 12.12 68.24 ;
        END
        PORT
            LAYER met1 ;
              RECT  694.44 73.2 696.44 73.68 ;
        END
        PORT
            LAYER met1 ;
              RECT  10.12 73.2 12.12 73.68 ;
        END
        PORT
            LAYER met1 ;
              RECT  694.44 78.64 696.44 79.12 ;
        END
        PORT
            LAYER met1 ;
              RECT  10.12 78.64 12.12 79.12 ;
        END
        PORT
            LAYER met1 ;
              RECT  694.44 84.08 696.44 84.56 ;
        END
        PORT
            LAYER met1 ;
              RECT  10.12 84.08 12.12 84.56 ;
        END
        PORT
            LAYER met1 ;
              RECT  694.44 89.52 696.44 90 ;
        END
        PORT
            LAYER met1 ;
              RECT  10.12 89.52 12.12 90 ;
        END
        PORT
            LAYER met1 ;
              RECT  694.44 94.96 696.44 95.44 ;
        END
        PORT
            LAYER met1 ;
              RECT  10.12 94.96 12.12 95.44 ;
        END
        PORT
            LAYER met1 ;
              RECT  694.44 100.4 696.44 100.88 ;
        END
        PORT
            LAYER met1 ;
              RECT  10.12 100.4 12.12 100.88 ;
        END
        PORT
            LAYER met1 ;
              RECT  694.44 105.84 696.44 106.32 ;
        END
        PORT
            LAYER met1 ;
              RECT  10.12 105.84 12.12 106.32 ;
        END
        PORT
            LAYER met1 ;
              RECT  694.44 111.28 696.44 111.76 ;
        END
        PORT
            LAYER met1 ;
              RECT  10.12 111.28 12.12 111.76 ;
        END
        PORT
            LAYER met1 ;
              RECT  694.44 116.72 696.44 117.2 ;
        END
        PORT
            LAYER met1 ;
              RECT  10.12 116.72 12.12 117.2 ;
        END
        PORT
            LAYER met1 ;
              RECT  694.44 122.16 696.44 122.64 ;
        END
        PORT
            LAYER met1 ;
              RECT  10.12 122.16 12.12 122.64 ;
        END
        PORT
            LAYER met1 ;
              RECT  694.44 127.6 696.44 128.08 ;
        END
        PORT
            LAYER met1 ;
              RECT  10.12 127.6 12.12 128.08 ;
        END
        PORT
            LAYER met1 ;
              RECT  694.44 133.04 696.44 133.52 ;
        END
        PORT
            LAYER met1 ;
              RECT  10.12 133.04 12.12 133.52 ;
        END
        PORT
            LAYER met1 ;
              RECT  694.44 138.48 696.44 138.96 ;
        END
        PORT
            LAYER met1 ;
              RECT  10.12 138.48 12.12 138.96 ;
        END
        PORT
            LAYER met1 ;
              RECT  694.44 143.92 696.44 144.4 ;
        END
        PORT
            LAYER met1 ;
              RECT  10.12 143.92 12.12 144.4 ;
        END
        PORT
            LAYER met1 ;
              RECT  694.44 149.36 696.44 149.84 ;
        END
        PORT
            LAYER met1 ;
              RECT  10.12 149.36 12.12 149.84 ;
        END
        PORT
            LAYER met1 ;
              RECT  694.44 154.8 696.44 155.28 ;
        END
        PORT
            LAYER met1 ;
              RECT  10.12 154.8 12.12 155.28 ;
        END
        PORT
            LAYER met1 ;
              RECT  694.44 160.24 696.44 160.72 ;
        END
        PORT
            LAYER met1 ;
              RECT  10.12 160.24 12.12 160.72 ;
        END
        PORT
            LAYER met1 ;
              RECT  694.44 165.68 696.44 166.16 ;
        END
        PORT
            LAYER met1 ;
              RECT  10.12 165.68 12.12 166.16 ;
        END
        PORT
            LAYER met1 ;
              RECT  694.44 171.12 696.44 171.6 ;
        END
        PORT
            LAYER met1 ;
              RECT  10.12 171.12 12.12 171.6 ;
        END
        PORT
            LAYER met1 ;
              RECT  694.44 176.56 696.44 177.04 ;
        END
        PORT
            LAYER met1 ;
              RECT  10.12 176.56 12.12 177.04 ;
        END
        PORT
            LAYER met1 ;
              RECT  694.44 182 696.44 182.48 ;
        END
        PORT
            LAYER met1 ;
              RECT  10.12 182 12.12 182.48 ;
        END
        PORT
            LAYER met1 ;
              RECT  694.44 187.44 696.44 187.92 ;
        END
        PORT
            LAYER met1 ;
              RECT  10.12 187.44 12.12 187.92 ;
        END
        PORT
            LAYER met1 ;
              RECT  694.44 192.88 696.44 193.36 ;
        END
        PORT
            LAYER met1 ;
              RECT  10.12 192.88 12.12 193.36 ;
        END
        PORT
            LAYER met1 ;
              RECT  694.44 198.32 696.44 198.8 ;
        END
        PORT
            LAYER met1 ;
              RECT  10.12 198.32 12.12 198.8 ;
        END
        PORT
            LAYER met1 ;
              RECT  694.44 203.76 696.44 204.24 ;
        END
        PORT
            LAYER met1 ;
              RECT  10.12 203.76 12.12 204.24 ;
        END
        PORT
            LAYER met1 ;
              RECT  694.44 209.2 696.44 209.68 ;
        END
        PORT
            LAYER met1 ;
              RECT  10.12 209.2 12.12 209.68 ;
        END
        PORT
            LAYER met1 ;
              RECT  694.44 214.64 696.44 215.12 ;
        END
        PORT
            LAYER met1 ;
              RECT  10.12 214.64 12.12 215.12 ;
        END
        PORT
            LAYER met1 ;
              RECT  694.44 220.08 696.44 220.56 ;
        END
        PORT
            LAYER met1 ;
              RECT  10.12 220.08 12.12 220.56 ;
        END
        PORT
            LAYER met1 ;
              RECT  694.44 225.52 696.44 226 ;
        END
        PORT
            LAYER met1 ;
              RECT  10.12 225.52 12.12 226 ;
        END
        PORT
            LAYER met1 ;
              RECT  694.44 230.96 696.44 231.44 ;
        END
        PORT
            LAYER met1 ;
              RECT  10.12 230.96 12.12 231.44 ;
        END
        PORT
            LAYER met1 ;
              RECT  694.44 236.4 696.44 236.88 ;
        END
        PORT
            LAYER met1 ;
              RECT  10.12 236.4 12.12 236.88 ;
        END
        PORT
            LAYER met1 ;
              RECT  694.44 241.84 696.44 242.32 ;
        END
        PORT
            LAYER met1 ;
              RECT  10.12 241.84 12.12 242.32 ;
        END
        PORT
            LAYER met1 ;
              RECT  694.44 247.28 696.44 247.76 ;
        END
        PORT
            LAYER met1 ;
              RECT  10.12 247.28 12.12 247.76 ;
        END
        PORT
            LAYER met1 ;
              RECT  694.44 252.72 696.44 253.2 ;
        END
        PORT
            LAYER met1 ;
              RECT  10.12 252.72 12.12 253.2 ;
        END
        PORT
            LAYER met1 ;
              RECT  694.44 258.16 696.44 258.64 ;
        END
        PORT
            LAYER met1 ;
              RECT  10.12 258.16 12.12 258.64 ;
        END
        PORT
            LAYER met1 ;
              RECT  694.44 263.6 696.44 264.08 ;
        END
        PORT
            LAYER met1 ;
              RECT  10.12 263.6 12.12 264.08 ;
        END
        PORT
            LAYER met1 ;
              RECT  694.44 269.04 696.44 269.52 ;
        END
        PORT
            LAYER met1 ;
              RECT  10.12 269.04 12.12 269.52 ;
        END
        PORT
            LAYER met1 ;
              RECT  694.44 274.48 696.44 274.96 ;
        END
        PORT
            LAYER met1 ;
              RECT  10.12 274.48 12.12 274.96 ;
        END
        PORT
            LAYER met1 ;
              RECT  694.44 279.92 696.44 280.4 ;
        END
        PORT
            LAYER met1 ;
              RECT  10.12 279.92 12.12 280.4 ;
        END
        PORT
            LAYER met1 ;
              RECT  694.44 285.36 696.44 285.84 ;
        END
        PORT
            LAYER met1 ;
              RECT  10.12 285.36 12.12 285.84 ;
        END
        PORT
            LAYER met1 ;
              RECT  694.44 290.8 696.44 291.28 ;
        END
        PORT
            LAYER met1 ;
              RECT  10.12 290.8 12.12 291.28 ;
        END
        PORT
            LAYER met1 ;
              RECT  694.44 296.24 696.44 296.72 ;
        END
        PORT
            LAYER met1 ;
              RECT  10.12 296.24 12.12 296.72 ;
        END
        PORT
            LAYER met1 ;
              RECT  694.44 301.68 696.44 302.16 ;
        END
        PORT
            LAYER met1 ;
              RECT  10.12 301.68 12.12 302.16 ;
        END
        PORT
            LAYER met1 ;
              RECT  694.44 307.12 696.44 307.6 ;
        END
        PORT
            LAYER met1 ;
              RECT  10.12 307.12 12.12 307.6 ;
        END
        PORT
            LAYER met1 ;
              RECT  694.44 312.56 696.44 313.04 ;
        END
        PORT
            LAYER met1 ;
              RECT  10.12 312.56 12.12 313.04 ;
        END
        PORT
            LAYER met1 ;
              RECT  694.44 318 696.44 318.48 ;
        END
        PORT
            LAYER met1 ;
              RECT  10.12 318 12.12 318.48 ;
        END
        PORT
            LAYER met1 ;
              RECT  694.44 323.44 696.44 323.92 ;
        END
        PORT
            LAYER met1 ;
              RECT  10.12 323.44 12.12 323.92 ;
        END
        PORT
            LAYER met1 ;
              RECT  694.44 328.88 696.44 329.36 ;
        END
        PORT
            LAYER met1 ;
              RECT  10.12 328.88 12.12 329.36 ;
        END
        PORT
            LAYER met1 ;
              RECT  694.44 334.32 696.44 334.8 ;
        END
        PORT
            LAYER met1 ;
              RECT  10.12 334.32 12.12 334.8 ;
        END
        PORT
            LAYER met1 ;
              RECT  694.44 339.76 696.44 340.24 ;
        END
        PORT
            LAYER met1 ;
              RECT  10.12 339.76 12.12 340.24 ;
        END
        PORT
            LAYER met1 ;
              RECT  694.44 345.2 696.44 345.68 ;
        END
        PORT
            LAYER met1 ;
              RECT  10.12 345.2 12.12 345.68 ;
        END
        PORT
            LAYER met1 ;
              RECT  694.44 350.64 696.44 351.12 ;
        END
        PORT
            LAYER met1 ;
              RECT  10.12 350.64 12.12 351.12 ;
        END
        PORT
            LAYER met1 ;
              RECT  694.44 356.08 696.44 356.56 ;
        END
        PORT
            LAYER met1 ;
              RECT  10.12 356.08 12.12 356.56 ;
        END
        PORT
            LAYER met1 ;
              RECT  694.44 361.52 696.44 362 ;
        END
        PORT
            LAYER met1 ;
              RECT  10.12 361.52 12.12 362 ;
        END
        PORT
            LAYER met1 ;
              RECT  694.44 366.96 696.44 367.44 ;
        END
        PORT
            LAYER met1 ;
              RECT  10.12 366.96 12.12 367.44 ;
        END
        PORT
            LAYER met1 ;
              RECT  694.44 372.4 696.44 372.88 ;
        END
        PORT
            LAYER met1 ;
              RECT  10.12 372.4 12.12 372.88 ;
        END
        PORT
            LAYER met1 ;
              RECT  694.44 377.84 696.44 378.32 ;
        END
        PORT
            LAYER met1 ;
              RECT  10.12 377.84 12.12 378.32 ;
        END
        PORT
            LAYER met1 ;
              RECT  694.44 383.28 696.44 383.76 ;
        END
        PORT
            LAYER met1 ;
              RECT  10.12 383.28 12.12 383.76 ;
        END
        PORT
            LAYER met1 ;
              RECT  694.44 388.72 696.44 389.2 ;
        END
        PORT
            LAYER met1 ;
              RECT  10.12 388.72 12.12 389.2 ;
        END
        PORT
            LAYER met1 ;
              RECT  694.44 394.16 696.44 394.64 ;
        END
        PORT
            LAYER met1 ;
              RECT  10.12 394.16 12.12 394.64 ;
        END
        PORT
            LAYER met1 ;
              RECT  694.44 399.6 696.44 400.08 ;
        END
        PORT
            LAYER met1 ;
              RECT  10.12 399.6 12.12 400.08 ;
        END
        PORT
            LAYER met1 ;
              RECT  694.44 405.04 696.44 405.52 ;
        END
        PORT
            LAYER met1 ;
              RECT  10.12 405.04 12.12 405.52 ;
        END
        PORT
            LAYER met1 ;
              RECT  694.44 410.48 696.44 410.96 ;
        END
        PORT
            LAYER met1 ;
              RECT  10.12 410.48 12.12 410.96 ;
        END
        PORT
            LAYER met1 ;
              RECT  694.44 415.92 696.44 416.4 ;
        END
        PORT
            LAYER met1 ;
              RECT  10.12 415.92 12.12 416.4 ;
        END
        PORT
            LAYER met1 ;
              RECT  694.44 421.36 696.44 421.84 ;
        END
        PORT
            LAYER met1 ;
              RECT  10.12 421.36 12.12 421.84 ;
        END
        PORT
            LAYER met1 ;
              RECT  694.44 426.8 696.44 427.28 ;
        END
        PORT
            LAYER met1 ;
              RECT  10.12 426.8 12.12 427.28 ;
        END
        PORT
            LAYER met1 ;
              RECT  694.44 432.24 696.44 432.72 ;
        END
        PORT
            LAYER met1 ;
              RECT  10.12 432.24 12.12 432.72 ;
        END
        PORT
            LAYER met1 ;
              RECT  694.44 437.68 696.44 438.16 ;
        END
        PORT
            LAYER met1 ;
              RECT  10.12 437.68 12.12 438.16 ;
        END
        PORT
            LAYER met1 ;
              RECT  694.44 443.12 696.44 443.6 ;
        END
        PORT
            LAYER met1 ;
              RECT  10.12 443.12 12.12 443.6 ;
        END
        PORT
            LAYER met1 ;
              RECT  694.44 448.56 696.44 449.04 ;
        END
        PORT
            LAYER met1 ;
              RECT  10.12 448.56 12.12 449.04 ;
        END
        PORT
            LAYER met1 ;
              RECT  694.44 454 696.44 454.48 ;
        END
        PORT
            LAYER met1 ;
              RECT  10.12 454 12.12 454.48 ;
        END
        PORT
            LAYER met1 ;
              RECT  694.44 459.44 696.44 459.92 ;
        END
        PORT
            LAYER met1 ;
              RECT  10.12 459.44 12.12 459.92 ;
        END
        PORT
            LAYER met1 ;
              RECT  694.44 464.88 696.44 465.36 ;
        END
        PORT
            LAYER met1 ;
              RECT  10.12 464.88 12.12 465.36 ;
        END
        PORT
            LAYER met1 ;
              RECT  694.44 470.32 696.44 470.8 ;
        END
        PORT
            LAYER met1 ;
              RECT  10.12 470.32 12.12 470.8 ;
        END
        PORT
            LAYER met1 ;
              RECT  694.44 475.76 696.44 476.24 ;
        END
        PORT
            LAYER met1 ;
              RECT  10.12 475.76 12.12 476.24 ;
        END
        PORT
            LAYER met1 ;
              RECT  694.44 481.2 696.44 481.68 ;
        END
        PORT
            LAYER met1 ;
              RECT  10.12 481.2 12.12 481.68 ;
        END
        PORT
            LAYER met1 ;
              RECT  694.44 486.64 696.44 487.12 ;
        END
        PORT
            LAYER met1 ;
              RECT  10.12 486.64 12.12 487.12 ;
        END
        PORT
            LAYER met1 ;
              RECT  694.44 492.08 696.44 492.56 ;
        END
        PORT
            LAYER met1 ;
              RECT  10.12 492.08 12.12 492.56 ;
        END
        PORT
            LAYER met1 ;
              RECT  694.44 497.52 696.44 498 ;
        END
        PORT
            LAYER met1 ;
              RECT  10.12 497.52 12.12 498 ;
        END
        PORT
            LAYER met1 ;
              RECT  694.44 502.96 696.44 503.44 ;
        END
        PORT
            LAYER met1 ;
              RECT  10.12 502.96 12.12 503.44 ;
        END
        PORT
            LAYER met1 ;
              RECT  694.44 508.4 696.44 508.88 ;
        END
        PORT
            LAYER met1 ;
              RECT  10.12 508.4 12.12 508.88 ;
        END
        PORT
            LAYER met1 ;
              RECT  694.44 513.84 696.44 514.32 ;
        END
        PORT
            LAYER met1 ;
              RECT  10.12 513.84 12.12 514.32 ;
        END
        PORT
            LAYER met1 ;
              RECT  694.44 519.28 696.44 519.76 ;
        END
        PORT
            LAYER met1 ;
              RECT  10.12 519.28 12.12 519.76 ;
        END
        PORT
            LAYER met1 ;
              RECT  694.44 524.72 696.44 525.2 ;
        END
        PORT
            LAYER met1 ;
              RECT  10.12 524.72 12.12 525.2 ;
        END
        PORT
            LAYER met1 ;
              RECT  694.44 530.16 696.44 530.64 ;
        END
        PORT
            LAYER met1 ;
              RECT  10.12 530.16 12.12 530.64 ;
        END
        PORT
            LAYER met1 ;
              RECT  694.44 535.6 696.44 536.08 ;
        END
        PORT
            LAYER met1 ;
              RECT  10.12 535.6 12.12 536.08 ;
        END
        PORT
            LAYER met1 ;
              RECT  694.44 541.04 696.44 541.52 ;
        END
        PORT
            LAYER met1 ;
              RECT  10.12 541.04 12.12 541.52 ;
        END
        PORT
            LAYER met1 ;
              RECT  694.44 546.48 696.44 546.96 ;
        END
        PORT
            LAYER met1 ;
              RECT  10.12 546.48 12.12 546.96 ;
        END
        PORT
            LAYER met1 ;
              RECT  694.44 551.92 696.44 552.4 ;
        END
        PORT
            LAYER met1 ;
              RECT  10.12 551.92 12.12 552.4 ;
        END
        PORT
            LAYER met1 ;
              RECT  694.44 557.36 696.44 557.84 ;
        END
        PORT
            LAYER met1 ;
              RECT  10.12 557.36 12.12 557.84 ;
        END
        PORT
            LAYER met1 ;
              RECT  694.44 562.8 696.44 563.28 ;
        END
        PORT
            LAYER met1 ;
              RECT  10.12 562.8 12.12 563.28 ;
        END
        PORT
            LAYER met1 ;
              RECT  694.44 568.24 696.44 568.72 ;
        END
        PORT
            LAYER met1 ;
              RECT  10.12 568.24 12.12 568.72 ;
        END
        PORT
            LAYER met1 ;
              RECT  694.44 573.68 696.44 574.16 ;
        END
        PORT
            LAYER met1 ;
              RECT  10.12 573.68 12.12 574.16 ;
        END
        PORT
            LAYER met1 ;
              RECT  694.44 579.12 696.44 579.6 ;
        END
        PORT
            LAYER met1 ;
              RECT  10.12 579.12 12.12 579.6 ;
        END
        PORT
            LAYER met1 ;
              RECT  694.44 584.56 696.44 585.04 ;
        END
        PORT
            LAYER met1 ;
              RECT  10.12 584.56 12.12 585.04 ;
        END
        PORT
            LAYER met1 ;
              RECT  694.44 590 696.44 590.48 ;
        END
        PORT
            LAYER met1 ;
              RECT  10.12 590 12.12 590.48 ;
        END
        PORT
            LAYER met1 ;
              RECT  694.44 595.44 696.44 595.92 ;
        END
        PORT
            LAYER met1 ;
              RECT  10.12 595.44 12.12 595.92 ;
        END
        PORT
            LAYER met1 ;
              RECT  694.44 600.88 696.44 601.36 ;
        END
        PORT
            LAYER met1 ;
              RECT  10.12 600.88 12.12 601.36 ;
        END
        PORT
            LAYER met1 ;
              RECT  694.44 606.32 696.44 606.8 ;
        END
        PORT
            LAYER met1 ;
              RECT  10.12 606.32 12.12 606.8 ;
        END
        PORT
            LAYER met1 ;
              RECT  694.44 611.76 696.44 612.24 ;
        END
        PORT
            LAYER met1 ;
              RECT  10.12 611.76 12.12 612.24 ;
        END
        PORT
            LAYER met1 ;
              RECT  694.44 617.2 696.44 617.68 ;
        END
        PORT
            LAYER met1 ;
              RECT  10.12 617.2 12.12 617.68 ;
        END
        PORT
            LAYER met1 ;
              RECT  694.44 622.64 696.44 623.12 ;
        END
        PORT
            LAYER met1 ;
              RECT  10.12 622.64 12.12 623.12 ;
        END
        PORT
            LAYER met1 ;
              RECT  694.44 628.08 696.44 628.56 ;
        END
        PORT
            LAYER met1 ;
              RECT  10.12 628.08 12.12 628.56 ;
        END
        PORT
            LAYER met1 ;
              RECT  694.44 633.52 696.44 634 ;
        END
        PORT
            LAYER met1 ;
              RECT  10.12 633.52 12.12 634 ;
        END
        PORT
            LAYER met1 ;
              RECT  694.44 638.96 696.44 639.44 ;
        END
        PORT
            LAYER met1 ;
              RECT  10.12 638.96 12.12 639.44 ;
        END
        PORT
            LAYER met1 ;
              RECT  694.44 644.4 696.44 644.88 ;
        END
        PORT
            LAYER met1 ;
              RECT  10.12 644.4 12.12 644.88 ;
        END
        PORT
            LAYER met1 ;
              RECT  694.44 649.84 696.44 650.32 ;
        END
        PORT
            LAYER met1 ;
              RECT  10.12 649.84 12.12 650.32 ;
        END
        PORT
            LAYER met1 ;
              RECT  694.44 655.28 696.44 655.76 ;
        END
        PORT
            LAYER met1 ;
              RECT  10.12 655.28 12.12 655.76 ;
        END
        PORT
            LAYER met1 ;
              RECT  694.44 660.72 696.44 661.2 ;
        END
        PORT
            LAYER met1 ;
              RECT  10.12 660.72 12.12 661.2 ;
        END
        PORT
            LAYER met1 ;
              RECT  694.44 666.16 696.44 666.64 ;
        END
        PORT
            LAYER met1 ;
              RECT  10.12 666.16 12.12 666.64 ;
        END
        PORT
            LAYER met1 ;
              RECT  694.44 671.6 696.44 672.08 ;
        END
        PORT
            LAYER met1 ;
              RECT  10.12 671.6 12.12 672.08 ;
        END
        PORT
            LAYER met1 ;
              RECT  694.44 677.04 696.44 677.52 ;
        END
        PORT
            LAYER met1 ;
              RECT  10.12 677.04 12.12 677.52 ;
        END
        PORT
            LAYER met1 ;
              RECT  694.44 682.48 696.44 682.96 ;
        END
        PORT
            LAYER met1 ;
              RECT  10.12 682.48 12.12 682.96 ;
        END
        PORT
            LAYER met1 ;
              RECT  694.44 687.92 696.44 688.4 ;
        END
        PORT
            LAYER met1 ;
              RECT  10.12 687.92 12.12 688.4 ;
        END
        PORT
            LAYER met1 ;
              RECT  694.44 693.36 696.44 693.84 ;
        END
        PORT
            LAYER met1 ;
              RECT  10.12 693.36 12.12 693.84 ;
        END
    END VPWR
    OBS
      LAYER met5 ;
        RECT  0 0 706.475 706.475 ;
      LAYER met4 ;
        RECT  0 696.56 706.475 706.475 ;
        RECT  675.85 694.56 706.475 696.56 ;
        RECT  648.71 694.56 674.25 696.56 ;
        RECT  621.57 694.56 647.11 696.56 ;
        RECT  594.43 694.56 619.97 696.56 ;
        RECT  567.29 694.56 592.83 696.56 ;
        RECT  540.15 694.56 565.69 696.56 ;
        RECT  513.01 694.56 538.55 696.56 ;
        RECT  485.87 694.56 511.41 696.56 ;
        RECT  458.73 694.56 484.27 696.56 ;
        RECT  431.59 694.56 457.13 696.56 ;
        RECT  404.45 694.56 429.99 696.56 ;
        RECT  377.31 694.56 402.85 696.56 ;
        RECT  350.17 694.56 375.71 696.56 ;
        RECT  323.03 694.56 348.57 696.56 ;
        RECT  295.89 694.56 321.43 696.56 ;
        RECT  268.75 694.56 294.29 696.56 ;
        RECT  241.61 694.56 267.15 696.56 ;
        RECT  214.47 694.56 240.01 696.56 ;
        RECT  187.33 694.56 212.87 696.56 ;
        RECT  160.19 694.56 185.73 696.56 ;
        RECT  133.05 694.56 158.59 696.56 ;
        RECT  105.91 694.56 131.45 696.56 ;
        RECT  78.77 694.56 104.31 696.56 ;
        RECT  51.63 694.56 77.17 696.56 ;
        RECT  24.49 694.56 50.03 696.56 ;
        RECT  0 694.56 22.89 696.56 ;
        RECT  0 12.64 706.475 694.56 ;
        RECT  675.85 10.64 706.475 12.64 ;
        RECT  648.71 10.64 674.25 12.64 ;
        RECT  621.57 10.64 647.11 12.64 ;
        RECT  594.43 10.64 619.97 12.64 ;
        RECT  567.29 10.64 592.83 12.64 ;
        RECT  540.15 10.64 565.69 12.64 ;
        RECT  513.01 10.64 538.55 12.64 ;
        RECT  485.87 10.64 511.41 12.64 ;
        RECT  458.73 10.64 484.27 12.64 ;
        RECT  431.59 10.64 457.13 12.64 ;
        RECT  404.45 10.64 429.99 12.64 ;
        RECT  377.31 10.64 402.85 12.64 ;
        RECT  350.17 10.64 375.71 12.64 ;
        RECT  323.03 10.64 348.57 12.64 ;
        RECT  295.89 10.64 321.43 12.64 ;
        RECT  268.75 10.64 294.29 12.64 ;
        RECT  241.61 10.64 267.15 12.64 ;
        RECT  214.47 10.64 240.01 12.64 ;
        RECT  187.33 10.64 212.87 12.64 ;
        RECT  160.19 10.64 185.73 12.64 ;
        RECT  133.05 10.64 158.59 12.64 ;
        RECT  105.91 10.64 131.45 12.64 ;
        RECT  78.77 10.64 104.31 12.64 ;
        RECT  51.63 10.64 77.17 12.64 ;
        RECT  24.49 10.64 50.03 12.64 ;
        RECT  0 10.64 22.89 12.64 ;
        RECT  0 0 706.475 10.64 ;
      LAYER met3 ;
        RECT  0 696.485 706.475 706.475 ;
        RECT  675.84 696.155 706.475 696.485 ;
        RECT  648.7 696.155 674.26 696.485 ;
        RECT  621.56 696.155 647.12 696.485 ;
        RECT  594.42 696.155 619.98 696.485 ;
        RECT  567.28 696.155 592.84 696.485 ;
        RECT  540.14 696.155 565.7 696.485 ;
        RECT  513 696.155 538.56 696.485 ;
        RECT  485.86 696.155 511.42 696.485 ;
        RECT  458.72 696.155 484.28 696.485 ;
        RECT  431.58 696.155 457.14 696.485 ;
        RECT  404.44 696.155 430 696.485 ;
        RECT  377.3 696.155 402.86 696.485 ;
        RECT  350.16 696.155 375.72 696.485 ;
        RECT  323.02 696.155 348.58 696.485 ;
        RECT  295.88 696.155 321.44 696.485 ;
        RECT  268.74 696.155 294.3 696.485 ;
        RECT  241.6 696.155 267.16 696.485 ;
        RECT  214.46 696.155 240.02 696.485 ;
        RECT  187.32 696.155 212.88 696.485 ;
        RECT  160.18 696.155 185.74 696.485 ;
        RECT  133.04 696.155 158.6 696.485 ;
        RECT  105.9 696.155 131.46 696.485 ;
        RECT  78.76 696.155 104.32 696.485 ;
        RECT  51.62 696.155 77.18 696.485 ;
        RECT  24.48 696.155 50.04 696.485 ;
        RECT  0 696.155 22.9 696.485 ;
        RECT  0 11.045 706.475 696.155 ;
        RECT  675.84 10.715 706.475 11.045 ;
        RECT  648.7 10.715 674.26 11.045 ;
        RECT  621.56 10.715 647.12 11.045 ;
        RECT  594.42 10.715 619.98 11.045 ;
        RECT  567.28 10.715 592.84 11.045 ;
        RECT  540.14 10.715 565.7 11.045 ;
        RECT  513 10.715 538.56 11.045 ;
        RECT  485.86 10.715 511.42 11.045 ;
        RECT  458.72 10.715 484.28 11.045 ;
        RECT  431.58 10.715 457.14 11.045 ;
        RECT  404.44 10.715 430 11.045 ;
        RECT  377.3 10.715 402.86 11.045 ;
        RECT  350.16 10.715 375.72 11.045 ;
        RECT  323.02 10.715 348.58 11.045 ;
        RECT  295.88 10.715 321.44 11.045 ;
        RECT  268.74 10.715 294.3 11.045 ;
        RECT  241.6 10.715 267.16 11.045 ;
        RECT  214.46 10.715 240.02 11.045 ;
        RECT  187.32 10.715 212.88 11.045 ;
        RECT  160.18 10.715 185.74 11.045 ;
        RECT  133.04 10.715 158.6 11.045 ;
        RECT  105.9 10.715 131.46 11.045 ;
        RECT  78.76 10.715 104.32 11.045 ;
        RECT  51.62 10.715 77.18 11.045 ;
        RECT  24.48 10.715 50.04 11.045 ;
        RECT  0 10.715 22.9 11.045 ;
        RECT  0 0 706.475 10.715 ;
      LAYER met2 ;
        RECT  705.02 705.99 706.475 706.475 ;
        RECT  698.58 705.99 704.88 706.475 ;
        RECT  691.22 705.99 698.44 706.475 ;
        RECT  683.86 705.99 691.08 706.475 ;
        RECT  676.5 705.99 683.72 706.475 ;
        RECT  669.14 705.99 676.36 706.475 ;
        RECT  661.78 705.99 669 706.475 ;
        RECT  654.42 705.99 661.64 706.475 ;
        RECT  647.06 705.99 654.28 706.475 ;
        RECT  639.7 705.99 646.92 706.475 ;
        RECT  632.34 705.99 639.56 706.475 ;
        RECT  625.9 705.99 632.2 706.475 ;
        RECT  618.54 705.99 625.76 706.475 ;
        RECT  611.18 705.99 618.4 706.475 ;
        RECT  603.82 705.99 611.04 706.475 ;
        RECT  596.46 705.99 603.68 706.475 ;
        RECT  589.1 705.99 596.32 706.475 ;
        RECT  581.74 705.99 588.96 706.475 ;
        RECT  574.38 705.99 581.6 706.475 ;
        RECT  567.02 705.99 574.24 706.475 ;
        RECT  559.66 705.99 566.88 706.475 ;
        RECT  552.3 705.99 559.52 706.475 ;
        RECT  545.86 705.99 552.16 706.475 ;
        RECT  538.5 705.99 545.72 706.475 ;
        RECT  531.14 705.99 538.36 706.475 ;
        RECT  523.78 705.99 531 706.475 ;
        RECT  516.42 705.99 523.64 706.475 ;
        RECT  509.06 705.99 516.28 706.475 ;
        RECT  501.7 705.99 508.92 706.475 ;
        RECT  494.34 705.99 501.56 706.475 ;
        RECT  486.98 705.99 494.2 706.475 ;
        RECT  479.62 705.99 486.84 706.475 ;
        RECT  472.26 705.99 479.48 706.475 ;
        RECT  465.82 705.99 472.12 706.475 ;
        RECT  458.46 705.99 465.68 706.475 ;
        RECT  451.1 705.99 458.32 706.475 ;
        RECT  443.74 705.99 450.96 706.475 ;
        RECT  436.38 705.99 443.6 706.475 ;
        RECT  429.02 705.99 436.24 706.475 ;
        RECT  421.66 705.99 428.88 706.475 ;
        RECT  414.3 705.99 421.52 706.475 ;
        RECT  406.94 705.99 414.16 706.475 ;
        RECT  399.58 705.99 406.8 706.475 ;
        RECT  392.22 705.99 399.44 706.475 ;
        RECT  385.78 705.99 392.08 706.475 ;
        RECT  378.42 705.99 385.64 706.475 ;
        RECT  371.06 705.99 378.28 706.475 ;
        RECT  363.7 705.99 370.92 706.475 ;
        RECT  356.34 705.99 363.56 706.475 ;
        RECT  348.98 705.99 356.2 706.475 ;
        RECT  341.62 705.99 348.84 706.475 ;
        RECT  334.26 705.99 341.48 706.475 ;
        RECT  326.9 705.99 334.12 706.475 ;
        RECT  319.54 705.99 326.76 706.475 ;
        RECT  312.18 705.99 319.4 706.475 ;
        RECT  305.74 705.99 312.04 706.475 ;
        RECT  298.38 705.99 305.6 706.475 ;
        RECT  291.02 705.99 298.24 706.475 ;
        RECT  283.66 705.99 290.88 706.475 ;
        RECT  276.3 705.99 283.52 706.475 ;
        RECT  268.94 705.99 276.16 706.475 ;
        RECT  261.58 705.99 268.8 706.475 ;
        RECT  254.22 705.99 261.44 706.475 ;
        RECT  246.86 705.99 254.08 706.475 ;
        RECT  239.5 705.99 246.72 706.475 ;
        RECT  232.14 705.99 239.36 706.475 ;
        RECT  225.7 705.99 232 706.475 ;
        RECT  218.34 705.99 225.56 706.475 ;
        RECT  210.98 705.99 218.2 706.475 ;
        RECT  203.62 705.99 210.84 706.475 ;
        RECT  196.26 705.99 203.48 706.475 ;
        RECT  188.9 705.99 196.12 706.475 ;
        RECT  181.54 705.99 188.76 706.475 ;
        RECT  174.18 705.99 181.4 706.475 ;
        RECT  166.82 705.99 174.04 706.475 ;
        RECT  159.46 705.99 166.68 706.475 ;
        RECT  152.1 705.99 159.32 706.475 ;
        RECT  145.66 705.99 151.96 706.475 ;
        RECT  138.3 705.99 145.52 706.475 ;
        RECT  130.94 705.99 138.16 706.475 ;
        RECT  123.58 705.99 130.8 706.475 ;
        RECT  116.22 705.99 123.44 706.475 ;
        RECT  108.86 705.99 116.08 706.475 ;
        RECT  101.5 705.99 108.72 706.475 ;
        RECT  94.14 705.99 101.36 706.475 ;
        RECT  86.78 705.99 94 706.475 ;
        RECT  79.42 705.99 86.64 706.475 ;
        RECT  72.98 705.99 79.28 706.475 ;
        RECT  65.62 705.99 72.84 706.475 ;
        RECT  58.26 705.99 65.48 706.475 ;
        RECT  50.9 705.99 58.12 706.475 ;
        RECT  43.54 705.99 50.76 706.475 ;
        RECT  36.18 705.99 43.4 706.475 ;
        RECT  28.82 705.99 36.04 706.475 ;
        RECT  21.46 705.99 28.68 706.475 ;
        RECT  14.1 705.99 21.32 706.475 ;
        RECT  6.74 705.99 13.96 706.475 ;
        RECT  0 705.99 6.6 706.475 ;
        RECT  0 696.505 706.475 705.99 ;
        RECT  675.82 696.135 706.475 696.505 ;
        RECT  648.68 696.135 674.28 696.505 ;
        RECT  621.54 696.135 647.14 696.505 ;
        RECT  594.4 696.135 620 696.505 ;
        RECT  567.26 696.135 592.86 696.505 ;
        RECT  540.12 696.135 565.72 696.505 ;
        RECT  512.98 696.135 538.58 696.505 ;
        RECT  485.84 696.135 511.44 696.505 ;
        RECT  458.7 696.135 484.3 696.505 ;
        RECT  431.56 696.135 457.16 696.505 ;
        RECT  404.42 696.135 430.02 696.505 ;
        RECT  377.28 696.135 402.88 696.505 ;
        RECT  350.14 696.135 375.74 696.505 ;
        RECT  323 696.135 348.6 696.505 ;
        RECT  295.86 696.135 321.46 696.505 ;
        RECT  268.72 696.135 294.32 696.505 ;
        RECT  241.58 696.135 267.18 696.505 ;
        RECT  214.44 696.135 240.04 696.505 ;
        RECT  187.3 696.135 212.9 696.505 ;
        RECT  160.16 696.135 185.76 696.505 ;
        RECT  133.02 696.135 158.62 696.505 ;
        RECT  105.88 696.135 131.48 696.505 ;
        RECT  78.74 696.135 104.34 696.505 ;
        RECT  51.6 696.135 77.2 696.505 ;
        RECT  24.46 696.135 50.06 696.505 ;
        RECT  0 696.135 22.92 696.505 ;
        RECT  0 11.065 706.475 696.135 ;
        RECT  675.82 10.695 706.475 11.065 ;
        RECT  648.68 10.695 674.28 11.065 ;
        RECT  621.54 10.695 647.14 11.065 ;
        RECT  594.4 10.695 620 11.065 ;
        RECT  567.26 10.695 592.86 11.065 ;
        RECT  540.12 10.695 565.72 11.065 ;
        RECT  512.98 10.695 538.58 11.065 ;
        RECT  485.84 10.695 511.44 11.065 ;
        RECT  458.7 10.695 484.3 11.065 ;
        RECT  431.56 10.695 457.16 11.065 ;
        RECT  404.42 10.695 430.02 11.065 ;
        RECT  377.28 10.695 402.88 11.065 ;
        RECT  350.14 10.695 375.74 11.065 ;
        RECT  323 10.695 348.6 11.065 ;
        RECT  295.86 10.695 321.46 11.065 ;
        RECT  268.72 10.695 294.32 11.065 ;
        RECT  241.58 10.695 267.18 11.065 ;
        RECT  214.44 10.695 240.04 11.065 ;
        RECT  187.3 10.695 212.9 11.065 ;
        RECT  160.16 10.695 185.76 11.065 ;
        RECT  133.02 10.695 158.62 11.065 ;
        RECT  105.88 10.695 131.48 11.065 ;
        RECT  78.74 10.695 104.34 11.065 ;
        RECT  51.6 10.695 77.2 11.065 ;
        RECT  24.46 10.695 50.06 11.065 ;
        RECT  0 10.695 22.92 11.065 ;
        RECT  0 0.485 706.475 10.695 ;
        RECT  699.5 0 706.475 0.485 ;
        RECT  692.14 0 699.36 0.485 ;
        RECT  684.78 0 692 0.485 ;
        RECT  677.42 0 684.64 0.485 ;
        RECT  670.06 0 677.28 0.485 ;
        RECT  662.7 0 669.92 0.485 ;
        RECT  655.34 0 662.56 0.485 ;
        RECT  647.98 0 655.2 0.485 ;
        RECT  640.62 0 647.84 0.485 ;
        RECT  633.26 0 640.48 0.485 ;
        RECT  626.82 0 633.12 0.485 ;
        RECT  619.46 0 626.68 0.485 ;
        RECT  612.1 0 619.32 0.485 ;
        RECT  604.74 0 611.96 0.485 ;
        RECT  597.38 0 604.6 0.485 ;
        RECT  590.02 0 597.24 0.485 ;
        RECT  582.66 0 589.88 0.485 ;
        RECT  575.3 0 582.52 0.485 ;
        RECT  567.94 0 575.16 0.485 ;
        RECT  560.58 0 567.8 0.485 ;
        RECT  554.14 0 560.44 0.485 ;
        RECT  546.78 0 554 0.485 ;
        RECT  539.42 0 546.64 0.485 ;
        RECT  532.06 0 539.28 0.485 ;
        RECT  524.7 0 531.92 0.485 ;
        RECT  517.34 0 524.56 0.485 ;
        RECT  509.98 0 517.2 0.485 ;
        RECT  502.62 0 509.84 0.485 ;
        RECT  495.26 0 502.48 0.485 ;
        RECT  487.9 0 495.12 0.485 ;
        RECT  480.54 0 487.76 0.485 ;
        RECT  474.1 0 480.4 0.485 ;
        RECT  466.74 0 473.96 0.485 ;
        RECT  459.38 0 466.6 0.485 ;
        RECT  452.02 0 459.24 0.485 ;
        RECT  444.66 0 451.88 0.485 ;
        RECT  437.3 0 444.52 0.485 ;
        RECT  429.94 0 437.16 0.485 ;
        RECT  422.58 0 429.8 0.485 ;
        RECT  415.22 0 422.44 0.485 ;
        RECT  407.86 0 415.08 0.485 ;
        RECT  400.5 0 407.72 0.485 ;
        RECT  394.06 0 400.36 0.485 ;
        RECT  386.7 0 393.92 0.485 ;
        RECT  379.34 0 386.56 0.485 ;
        RECT  371.98 0 379.2 0.485 ;
        RECT  364.62 0 371.84 0.485 ;
        RECT  357.26 0 364.48 0.485 ;
        RECT  349.9 0 357.12 0.485 ;
        RECT  342.54 0 349.76 0.485 ;
        RECT  335.18 0 342.4 0.485 ;
        RECT  327.82 0 335.04 0.485 ;
        RECT  320.46 0 327.68 0.485 ;
        RECT  314.02 0 320.32 0.485 ;
        RECT  306.66 0 313.88 0.485 ;
        RECT  299.3 0 306.52 0.485 ;
        RECT  291.94 0 299.16 0.485 ;
        RECT  284.58 0 291.8 0.485 ;
        RECT  277.22 0 284.44 0.485 ;
        RECT  269.86 0 277.08 0.485 ;
        RECT  262.5 0 269.72 0.485 ;
        RECT  255.14 0 262.36 0.485 ;
        RECT  247.78 0 255 0.485 ;
        RECT  240.42 0 247.64 0.485 ;
        RECT  233.98 0 240.28 0.485 ;
        RECT  226.62 0 233.84 0.485 ;
        RECT  219.26 0 226.48 0.485 ;
        RECT  211.9 0 219.12 0.485 ;
        RECT  204.54 0 211.76 0.485 ;
        RECT  197.18 0 204.4 0.485 ;
        RECT  189.82 0 197.04 0.485 ;
        RECT  182.46 0 189.68 0.485 ;
        RECT  175.1 0 182.32 0.485 ;
        RECT  167.74 0 174.96 0.485 ;
        RECT  160.38 0 167.6 0.485 ;
        RECT  153.94 0 160.24 0.485 ;
        RECT  146.58 0 153.8 0.485 ;
        RECT  139.22 0 146.44 0.485 ;
        RECT  131.86 0 139.08 0.485 ;
        RECT  124.5 0 131.72 0.485 ;
        RECT  117.14 0 124.36 0.485 ;
        RECT  109.78 0 117 0.485 ;
        RECT  102.42 0 109.64 0.485 ;
        RECT  95.06 0 102.28 0.485 ;
        RECT  87.7 0 94.92 0.485 ;
        RECT  80.34 0 87.56 0.485 ;
        RECT  73.9 0 80.2 0.485 ;
        RECT  66.54 0 73.76 0.485 ;
        RECT  59.18 0 66.4 0.485 ;
        RECT  51.82 0 59.04 0.485 ;
        RECT  44.46 0 51.68 0.485 ;
        RECT  37.1 0 44.32 0.485 ;
        RECT  29.74 0 36.96 0.485 ;
        RECT  22.38 0 29.6 0.485 ;
        RECT  15.02 0 22.24 0.485 ;
        RECT  7.66 0 14.88 0.485 ;
        RECT  1.22 0 7.52 0.485 ;
        RECT  0 0 1.08 0.485 ;
      LAYER met1 ;
        RECT  0 704.72 706.475 706.475 ;
        RECT  0.595 704.58 706.475 704.72 ;
        RECT  0 700.64 706.475 704.58 ;
        RECT  0 700.5 705.88 700.64 ;
        RECT  0 699.96 706.475 700.5 ;
        RECT  0.595 699.82 706.475 699.96 ;
        RECT  0 696.56 706.475 699.82 ;
        RECT  696.44 696.08 706.475 696.56 ;
        RECT  0 696.08 10.12 696.56 ;
        RECT  0 695.2 706.475 696.08 ;
        RECT  0 695.06 705.88 695.2 ;
        RECT  0 694.52 706.475 695.06 ;
        RECT  0.595 694.38 706.475 694.52 ;
        RECT  0 693.84 706.475 694.38 ;
        RECT  696.44 693.36 706.475 693.84 ;
        RECT  12.12 693.36 694.44 693.84 ;
        RECT  0 693.36 10.12 693.84 ;
        RECT  0 691.12 706.475 693.36 ;
        RECT  696.44 690.64 706.475 691.12 ;
        RECT  12.12 690.64 694.44 691.12 ;
        RECT  0 690.64 10.12 691.12 ;
        RECT  0 689.76 706.475 690.64 ;
        RECT  0 689.62 705.88 689.76 ;
        RECT  0 689.08 706.475 689.62 ;
        RECT  0.595 688.94 706.475 689.08 ;
        RECT  0 688.4 706.475 688.94 ;
        RECT  696.44 687.92 706.475 688.4 ;
        RECT  12.12 687.92 694.44 688.4 ;
        RECT  0 687.92 10.12 688.4 ;
        RECT  0 685.68 706.475 687.92 ;
        RECT  696.44 685.2 706.475 685.68 ;
        RECT  12.12 685.2 694.44 685.68 ;
        RECT  0 685.2 10.12 685.68 ;
        RECT  0 684.32 706.475 685.2 ;
        RECT  0 684.18 705.88 684.32 ;
        RECT  0 683.64 706.475 684.18 ;
        RECT  0.595 683.5 706.475 683.64 ;
        RECT  0 682.96 706.475 683.5 ;
        RECT  696.44 682.48 706.475 682.96 ;
        RECT  12.12 682.48 694.44 682.96 ;
        RECT  0 682.48 10.12 682.96 ;
        RECT  0 680.24 706.475 682.48 ;
        RECT  696.44 679.76 706.475 680.24 ;
        RECT  12.12 679.76 694.44 680.24 ;
        RECT  0 679.76 10.12 680.24 ;
        RECT  0 678.88 706.475 679.76 ;
        RECT  0 678.74 705.88 678.88 ;
        RECT  0 678.2 706.475 678.74 ;
        RECT  0.595 678.06 706.475 678.2 ;
        RECT  0 677.52 706.475 678.06 ;
        RECT  696.44 677.04 706.475 677.52 ;
        RECT  12.12 677.04 694.44 677.52 ;
        RECT  0 677.04 10.12 677.52 ;
        RECT  0 674.8 706.475 677.04 ;
        RECT  696.44 674.32 706.475 674.8 ;
        RECT  12.12 674.32 694.44 674.8 ;
        RECT  0 674.32 10.12 674.8 ;
        RECT  0 673.44 706.475 674.32 ;
        RECT  0 673.3 705.88 673.44 ;
        RECT  0 672.76 706.475 673.3 ;
        RECT  0.595 672.62 706.475 672.76 ;
        RECT  0 672.08 706.475 672.62 ;
        RECT  696.44 671.6 706.475 672.08 ;
        RECT  12.12 671.6 694.44 672.08 ;
        RECT  0 671.6 10.12 672.08 ;
        RECT  0 669.36 706.475 671.6 ;
        RECT  696.44 668.88 706.475 669.36 ;
        RECT  12.12 668.88 694.44 669.36 ;
        RECT  0 668.88 10.12 669.36 ;
        RECT  0 668 706.475 668.88 ;
        RECT  0 667.86 705.88 668 ;
        RECT  0 667.32 706.475 667.86 ;
        RECT  0.595 667.18 706.475 667.32 ;
        RECT  0 666.64 706.475 667.18 ;
        RECT  696.44 666.16 706.475 666.64 ;
        RECT  12.12 666.16 694.44 666.64 ;
        RECT  0 666.16 10.12 666.64 ;
        RECT  0 663.92 706.475 666.16 ;
        RECT  696.44 663.44 706.475 663.92 ;
        RECT  12.12 663.44 694.44 663.92 ;
        RECT  0 663.44 10.12 663.92 ;
        RECT  0 662.56 706.475 663.44 ;
        RECT  0 662.42 705.88 662.56 ;
        RECT  0 661.88 706.475 662.42 ;
        RECT  0.595 661.74 706.475 661.88 ;
        RECT  0 661.2 706.475 661.74 ;
        RECT  696.44 660.72 706.475 661.2 ;
        RECT  12.12 660.72 694.44 661.2 ;
        RECT  0 660.72 10.12 661.2 ;
        RECT  0 658.48 706.475 660.72 ;
        RECT  696.44 658 706.475 658.48 ;
        RECT  12.12 658 694.44 658.48 ;
        RECT  0 658 10.12 658.48 ;
        RECT  0 657.12 706.475 658 ;
        RECT  0 656.98 705.88 657.12 ;
        RECT  0 656.44 706.475 656.98 ;
        RECT  0.595 656.3 706.475 656.44 ;
        RECT  0 655.76 706.475 656.3 ;
        RECT  696.44 655.28 706.475 655.76 ;
        RECT  12.12 655.28 694.44 655.76 ;
        RECT  0 655.28 10.12 655.76 ;
        RECT  0 653.04 706.475 655.28 ;
        RECT  696.44 652.56 706.475 653.04 ;
        RECT  12.12 652.56 694.44 653.04 ;
        RECT  0 652.56 10.12 653.04 ;
        RECT  0 651.68 706.475 652.56 ;
        RECT  0 651.54 705.88 651.68 ;
        RECT  0 651 706.475 651.54 ;
        RECT  0.595 650.86 706.475 651 ;
        RECT  0 650.32 706.475 650.86 ;
        RECT  696.44 649.84 706.475 650.32 ;
        RECT  12.12 649.84 694.44 650.32 ;
        RECT  0 649.84 10.12 650.32 ;
        RECT  0 647.6 706.475 649.84 ;
        RECT  696.44 647.12 706.475 647.6 ;
        RECT  12.12 647.12 694.44 647.6 ;
        RECT  0 647.12 10.12 647.6 ;
        RECT  0 646.92 706.475 647.12 ;
        RECT  0 646.78 705.88 646.92 ;
        RECT  0 645.56 706.475 646.78 ;
        RECT  0.595 645.42 706.475 645.56 ;
        RECT  0 644.88 706.475 645.42 ;
        RECT  696.44 644.4 706.475 644.88 ;
        RECT  12.12 644.4 694.44 644.88 ;
        RECT  0 644.4 10.12 644.88 ;
        RECT  0 642.16 706.475 644.4 ;
        RECT  696.44 641.68 706.475 642.16 ;
        RECT  12.12 641.68 694.44 642.16 ;
        RECT  0 641.68 10.12 642.16 ;
        RECT  0 641.48 706.475 641.68 ;
        RECT  0 641.34 705.88 641.48 ;
        RECT  0 640.8 706.475 641.34 ;
        RECT  0.595 640.66 706.475 640.8 ;
        RECT  0 639.44 706.475 640.66 ;
        RECT  696.44 638.96 706.475 639.44 ;
        RECT  12.12 638.96 694.44 639.44 ;
        RECT  0 638.96 10.12 639.44 ;
        RECT  0 636.72 706.475 638.96 ;
        RECT  696.44 636.24 706.475 636.72 ;
        RECT  12.12 636.24 694.44 636.72 ;
        RECT  0 636.24 10.12 636.72 ;
        RECT  0 636.04 706.475 636.24 ;
        RECT  0 635.9 705.88 636.04 ;
        RECT  0 635.36 706.475 635.9 ;
        RECT  0.595 635.22 706.475 635.36 ;
        RECT  0 634 706.475 635.22 ;
        RECT  696.44 633.52 706.475 634 ;
        RECT  12.12 633.52 694.44 634 ;
        RECT  0 633.52 10.12 634 ;
        RECT  0 631.28 706.475 633.52 ;
        RECT  696.44 630.8 706.475 631.28 ;
        RECT  12.12 630.8 694.44 631.28 ;
        RECT  0 630.8 10.12 631.28 ;
        RECT  0 630.6 706.475 630.8 ;
        RECT  0 630.46 705.88 630.6 ;
        RECT  0 629.92 706.475 630.46 ;
        RECT  0.595 629.78 706.475 629.92 ;
        RECT  0 628.56 706.475 629.78 ;
        RECT  696.44 628.08 706.475 628.56 ;
        RECT  12.12 628.08 694.44 628.56 ;
        RECT  0 628.08 10.12 628.56 ;
        RECT  0 625.84 706.475 628.08 ;
        RECT  696.44 625.36 706.475 625.84 ;
        RECT  12.12 625.36 694.44 625.84 ;
        RECT  0 625.36 10.12 625.84 ;
        RECT  0 625.16 706.475 625.36 ;
        RECT  0 625.02 705.88 625.16 ;
        RECT  0 624.48 706.475 625.02 ;
        RECT  0.595 624.34 706.475 624.48 ;
        RECT  0 623.12 706.475 624.34 ;
        RECT  696.44 622.64 706.475 623.12 ;
        RECT  12.12 622.64 694.44 623.12 ;
        RECT  0 622.64 10.12 623.12 ;
        RECT  0 620.4 706.475 622.64 ;
        RECT  696.44 619.92 706.475 620.4 ;
        RECT  12.12 619.92 694.44 620.4 ;
        RECT  0 619.92 10.12 620.4 ;
        RECT  0 619.72 706.475 619.92 ;
        RECT  0 619.58 705.88 619.72 ;
        RECT  0 619.04 706.475 619.58 ;
        RECT  0.595 618.9 706.475 619.04 ;
        RECT  0 617.68 706.475 618.9 ;
        RECT  696.44 617.2 706.475 617.68 ;
        RECT  12.12 617.2 694.44 617.68 ;
        RECT  0 617.2 10.12 617.68 ;
        RECT  0 614.96 706.475 617.2 ;
        RECT  696.44 614.48 706.475 614.96 ;
        RECT  12.12 614.48 694.44 614.96 ;
        RECT  0 614.48 10.12 614.96 ;
        RECT  0 614.28 706.475 614.48 ;
        RECT  0 614.14 705.88 614.28 ;
        RECT  0 613.6 706.475 614.14 ;
        RECT  0.595 613.46 706.475 613.6 ;
        RECT  0 612.24 706.475 613.46 ;
        RECT  696.44 611.76 706.475 612.24 ;
        RECT  12.12 611.76 694.44 612.24 ;
        RECT  0 611.76 10.12 612.24 ;
        RECT  0 609.52 706.475 611.76 ;
        RECT  696.44 609.04 706.475 609.52 ;
        RECT  12.12 609.04 694.44 609.52 ;
        RECT  0 609.04 10.12 609.52 ;
        RECT  0 608.84 706.475 609.04 ;
        RECT  0 608.7 705.88 608.84 ;
        RECT  0 608.16 706.475 608.7 ;
        RECT  0.595 608.02 706.475 608.16 ;
        RECT  0 606.8 706.475 608.02 ;
        RECT  696.44 606.32 706.475 606.8 ;
        RECT  12.12 606.32 694.44 606.8 ;
        RECT  0 606.32 10.12 606.8 ;
        RECT  0 604.08 706.475 606.32 ;
        RECT  696.44 603.6 706.475 604.08 ;
        RECT  12.12 603.6 694.44 604.08 ;
        RECT  0 603.6 10.12 604.08 ;
        RECT  0 603.4 706.475 603.6 ;
        RECT  0 603.26 705.88 603.4 ;
        RECT  0 602.72 706.475 603.26 ;
        RECT  0.595 602.58 706.475 602.72 ;
        RECT  0 601.36 706.475 602.58 ;
        RECT  696.44 600.88 706.475 601.36 ;
        RECT  12.12 600.88 694.44 601.36 ;
        RECT  0 600.88 10.12 601.36 ;
        RECT  0 598.64 706.475 600.88 ;
        RECT  696.44 598.16 706.475 598.64 ;
        RECT  12.12 598.16 694.44 598.64 ;
        RECT  0 598.16 10.12 598.64 ;
        RECT  0 597.96 706.475 598.16 ;
        RECT  0 597.82 705.88 597.96 ;
        RECT  0 597.28 706.475 597.82 ;
        RECT  0.595 597.14 706.475 597.28 ;
        RECT  0 595.92 706.475 597.14 ;
        RECT  696.44 595.44 706.475 595.92 ;
        RECT  12.12 595.44 694.44 595.92 ;
        RECT  0 595.44 10.12 595.92 ;
        RECT  0 593.2 706.475 595.44 ;
        RECT  696.44 592.72 706.475 593.2 ;
        RECT  12.12 592.72 694.44 593.2 ;
        RECT  0 592.72 10.12 593.2 ;
        RECT  0 592.52 706.475 592.72 ;
        RECT  0 592.38 705.88 592.52 ;
        RECT  0 591.84 706.475 592.38 ;
        RECT  0.595 591.7 706.475 591.84 ;
        RECT  0 590.48 706.475 591.7 ;
        RECT  696.44 590 706.475 590.48 ;
        RECT  12.12 590 694.44 590.48 ;
        RECT  0 590 10.12 590.48 ;
        RECT  0 587.76 706.475 590 ;
        RECT  696.44 587.62 705.88 587.76 ;
        RECT  12.12 587.62 694.44 587.76 ;
        RECT  0 587.62 10.12 587.76 ;
        RECT  696.44 587.28 706.475 587.62 ;
        RECT  12.12 587.28 694.44 587.62 ;
        RECT  0 587.28 10.12 587.62 ;
        RECT  0 586.4 706.475 587.28 ;
        RECT  0.595 586.26 706.475 586.4 ;
        RECT  0 585.04 706.475 586.26 ;
        RECT  696.44 584.56 706.475 585.04 ;
        RECT  12.12 584.56 694.44 585.04 ;
        RECT  0 584.56 10.12 585.04 ;
        RECT  0 582.32 706.475 584.56 ;
        RECT  696.44 582.18 705.88 582.32 ;
        RECT  12.12 582.18 694.44 582.32 ;
        RECT  0 582.18 10.12 582.32 ;
        RECT  696.44 581.84 706.475 582.18 ;
        RECT  12.12 581.84 694.44 582.18 ;
        RECT  0 581.84 10.12 582.18 ;
        RECT  0 581.64 706.475 581.84 ;
        RECT  0.595 581.5 706.475 581.64 ;
        RECT  0 579.6 706.475 581.5 ;
        RECT  696.44 579.12 706.475 579.6 ;
        RECT  12.12 579.12 694.44 579.6 ;
        RECT  0 579.12 10.12 579.6 ;
        RECT  0 576.88 706.475 579.12 ;
        RECT  696.44 576.74 705.88 576.88 ;
        RECT  12.12 576.74 694.44 576.88 ;
        RECT  0 576.74 10.12 576.88 ;
        RECT  696.44 576.4 706.475 576.74 ;
        RECT  12.12 576.4 694.44 576.74 ;
        RECT  0 576.4 10.12 576.74 ;
        RECT  0 576.2 706.475 576.4 ;
        RECT  0.595 576.06 706.475 576.2 ;
        RECT  0 574.16 706.475 576.06 ;
        RECT  696.44 573.68 706.475 574.16 ;
        RECT  12.12 573.68 694.44 574.16 ;
        RECT  0 573.68 10.12 574.16 ;
        RECT  0 571.44 706.475 573.68 ;
        RECT  696.44 571.3 705.88 571.44 ;
        RECT  12.12 571.3 694.44 571.44 ;
        RECT  0 571.3 10.12 571.44 ;
        RECT  696.44 570.96 706.475 571.3 ;
        RECT  12.12 570.96 694.44 571.3 ;
        RECT  0 570.96 10.12 571.3 ;
        RECT  0 570.76 706.475 570.96 ;
        RECT  0.595 570.62 706.475 570.76 ;
        RECT  0 568.72 706.475 570.62 ;
        RECT  696.44 568.24 706.475 568.72 ;
        RECT  12.12 568.24 694.44 568.72 ;
        RECT  0 568.24 10.12 568.72 ;
        RECT  0 566 706.475 568.24 ;
        RECT  696.44 565.86 705.88 566 ;
        RECT  12.12 565.86 694.44 566 ;
        RECT  0 565.86 10.12 566 ;
        RECT  696.44 565.52 706.475 565.86 ;
        RECT  12.12 565.52 694.44 565.86 ;
        RECT  0 565.52 10.12 565.86 ;
        RECT  0 565.32 706.475 565.52 ;
        RECT  0.595 565.18 706.475 565.32 ;
        RECT  0 563.28 706.475 565.18 ;
        RECT  696.44 562.8 706.475 563.28 ;
        RECT  12.12 562.8 694.44 563.28 ;
        RECT  0 562.8 10.12 563.28 ;
        RECT  0 560.56 706.475 562.8 ;
        RECT  696.44 560.42 705.88 560.56 ;
        RECT  12.12 560.42 694.44 560.56 ;
        RECT  0 560.42 10.12 560.56 ;
        RECT  696.44 560.08 706.475 560.42 ;
        RECT  12.12 560.08 694.44 560.42 ;
        RECT  0 560.08 10.12 560.42 ;
        RECT  0 559.88 706.475 560.08 ;
        RECT  0.595 559.74 706.475 559.88 ;
        RECT  0 557.84 706.475 559.74 ;
        RECT  696.44 557.36 706.475 557.84 ;
        RECT  12.12 557.36 694.44 557.84 ;
        RECT  0 557.36 10.12 557.84 ;
        RECT  0 555.12 706.475 557.36 ;
        RECT  696.44 554.98 705.88 555.12 ;
        RECT  12.12 554.98 694.44 555.12 ;
        RECT  0 554.98 10.12 555.12 ;
        RECT  696.44 554.64 706.475 554.98 ;
        RECT  12.12 554.64 694.44 554.98 ;
        RECT  0 554.64 10.12 554.98 ;
        RECT  0 554.44 706.475 554.64 ;
        RECT  0.595 554.3 706.475 554.44 ;
        RECT  0 552.4 706.475 554.3 ;
        RECT  696.44 551.92 706.475 552.4 ;
        RECT  12.12 551.92 694.44 552.4 ;
        RECT  0 551.92 10.12 552.4 ;
        RECT  0 549.68 706.475 551.92 ;
        RECT  696.44 549.54 705.88 549.68 ;
        RECT  12.12 549.54 694.44 549.68 ;
        RECT  0 549.54 10.12 549.68 ;
        RECT  696.44 549.2 706.475 549.54 ;
        RECT  12.12 549.2 694.44 549.54 ;
        RECT  0 549.2 10.12 549.54 ;
        RECT  0 549 706.475 549.2 ;
        RECT  0.595 548.86 706.475 549 ;
        RECT  0 546.96 706.475 548.86 ;
        RECT  696.44 546.48 706.475 546.96 ;
        RECT  12.12 546.48 694.44 546.96 ;
        RECT  0 546.48 10.12 546.96 ;
        RECT  0 544.24 706.475 546.48 ;
        RECT  696.44 544.1 705.88 544.24 ;
        RECT  12.12 544.1 694.44 544.24 ;
        RECT  0 544.1 10.12 544.24 ;
        RECT  696.44 543.76 706.475 544.1 ;
        RECT  12.12 543.76 694.44 544.1 ;
        RECT  0 543.76 10.12 544.1 ;
        RECT  0 543.56 706.475 543.76 ;
        RECT  0.595 543.42 706.475 543.56 ;
        RECT  0 541.52 706.475 543.42 ;
        RECT  696.44 541.04 706.475 541.52 ;
        RECT  12.12 541.04 694.44 541.52 ;
        RECT  0 541.04 10.12 541.52 ;
        RECT  0 538.8 706.475 541.04 ;
        RECT  696.44 538.66 705.88 538.8 ;
        RECT  12.12 538.66 694.44 538.8 ;
        RECT  0 538.66 10.12 538.8 ;
        RECT  696.44 538.32 706.475 538.66 ;
        RECT  12.12 538.32 694.44 538.66 ;
        RECT  0 538.32 10.12 538.66 ;
        RECT  0 538.12 706.475 538.32 ;
        RECT  0.595 537.98 706.475 538.12 ;
        RECT  0 536.08 706.475 537.98 ;
        RECT  696.44 535.6 706.475 536.08 ;
        RECT  12.12 535.6 694.44 536.08 ;
        RECT  0 535.6 10.12 536.08 ;
        RECT  0 533.36 706.475 535.6 ;
        RECT  696.44 533.22 705.88 533.36 ;
        RECT  12.12 533.22 694.44 533.36 ;
        RECT  0 533.22 10.12 533.36 ;
        RECT  696.44 532.88 706.475 533.22 ;
        RECT  12.12 532.88 694.44 533.22 ;
        RECT  0 532.88 10.12 533.22 ;
        RECT  0 532.68 706.475 532.88 ;
        RECT  0.595 532.54 706.475 532.68 ;
        RECT  0 530.64 706.475 532.54 ;
        RECT  696.44 530.16 706.475 530.64 ;
        RECT  12.12 530.16 694.44 530.64 ;
        RECT  0 530.16 10.12 530.64 ;
        RECT  0 528.6 706.475 530.16 ;
        RECT  0 528.46 705.88 528.6 ;
        RECT  0 527.92 706.475 528.46 ;
        RECT  696.44 527.44 706.475 527.92 ;
        RECT  12.12 527.44 694.44 527.92 ;
        RECT  0 527.44 10.12 527.92 ;
        RECT  0 527.24 706.475 527.44 ;
        RECT  0.595 527.1 706.475 527.24 ;
        RECT  0 525.2 706.475 527.1 ;
        RECT  696.44 524.72 706.475 525.2 ;
        RECT  12.12 524.72 694.44 525.2 ;
        RECT  0 524.72 10.12 525.2 ;
        RECT  0 523.16 706.475 524.72 ;
        RECT  0 523.02 705.88 523.16 ;
        RECT  0 522.48 706.475 523.02 ;
        RECT  696.44 522.34 706.475 522.48 ;
        RECT  12.12 522.34 694.44 522.48 ;
        RECT  0.595 522.34 10.12 522.48 ;
        RECT  696.44 522 706.475 522.34 ;
        RECT  12.12 522 694.44 522.34 ;
        RECT  0 522 10.12 522.34 ;
        RECT  0 519.76 706.475 522 ;
        RECT  696.44 519.28 706.475 519.76 ;
        RECT  12.12 519.28 694.44 519.76 ;
        RECT  0 519.28 10.12 519.76 ;
        RECT  0 517.72 706.475 519.28 ;
        RECT  0 517.58 705.88 517.72 ;
        RECT  0 517.04 706.475 517.58 ;
        RECT  696.44 516.9 706.475 517.04 ;
        RECT  12.12 516.9 694.44 517.04 ;
        RECT  0.595 516.9 10.12 517.04 ;
        RECT  696.44 516.56 706.475 516.9 ;
        RECT  12.12 516.56 694.44 516.9 ;
        RECT  0 516.56 10.12 516.9 ;
        RECT  0 514.32 706.475 516.56 ;
        RECT  696.44 513.84 706.475 514.32 ;
        RECT  12.12 513.84 694.44 514.32 ;
        RECT  0 513.84 10.12 514.32 ;
        RECT  0 512.28 706.475 513.84 ;
        RECT  0 512.14 705.88 512.28 ;
        RECT  0 511.6 706.475 512.14 ;
        RECT  696.44 511.46 706.475 511.6 ;
        RECT  12.12 511.46 694.44 511.6 ;
        RECT  0.595 511.46 10.12 511.6 ;
        RECT  696.44 511.12 706.475 511.46 ;
        RECT  12.12 511.12 694.44 511.46 ;
        RECT  0 511.12 10.12 511.46 ;
        RECT  0 508.88 706.475 511.12 ;
        RECT  696.44 508.4 706.475 508.88 ;
        RECT  12.12 508.4 694.44 508.88 ;
        RECT  0 508.4 10.12 508.88 ;
        RECT  0 506.84 706.475 508.4 ;
        RECT  0 506.7 705.88 506.84 ;
        RECT  0 506.16 706.475 506.7 ;
        RECT  696.44 506.02 706.475 506.16 ;
        RECT  12.12 506.02 694.44 506.16 ;
        RECT  0.595 506.02 10.12 506.16 ;
        RECT  696.44 505.68 706.475 506.02 ;
        RECT  12.12 505.68 694.44 506.02 ;
        RECT  0 505.68 10.12 506.02 ;
        RECT  0 503.44 706.475 505.68 ;
        RECT  696.44 502.96 706.475 503.44 ;
        RECT  12.12 502.96 694.44 503.44 ;
        RECT  0 502.96 10.12 503.44 ;
        RECT  0 501.4 706.475 502.96 ;
        RECT  0 501.26 705.88 501.4 ;
        RECT  0 500.72 706.475 501.26 ;
        RECT  696.44 500.58 706.475 500.72 ;
        RECT  12.12 500.58 694.44 500.72 ;
        RECT  0.595 500.58 10.12 500.72 ;
        RECT  696.44 500.24 706.475 500.58 ;
        RECT  12.12 500.24 694.44 500.58 ;
        RECT  0 500.24 10.12 500.58 ;
        RECT  0 498 706.475 500.24 ;
        RECT  696.44 497.52 706.475 498 ;
        RECT  12.12 497.52 694.44 498 ;
        RECT  0 497.52 10.12 498 ;
        RECT  0 495.96 706.475 497.52 ;
        RECT  0 495.82 705.88 495.96 ;
        RECT  0 495.28 706.475 495.82 ;
        RECT  696.44 495.14 706.475 495.28 ;
        RECT  12.12 495.14 694.44 495.28 ;
        RECT  0.595 495.14 10.12 495.28 ;
        RECT  696.44 494.8 706.475 495.14 ;
        RECT  12.12 494.8 694.44 495.14 ;
        RECT  0 494.8 10.12 495.14 ;
        RECT  0 492.56 706.475 494.8 ;
        RECT  696.44 492.08 706.475 492.56 ;
        RECT  12.12 492.08 694.44 492.56 ;
        RECT  0 492.08 10.12 492.56 ;
        RECT  0 490.52 706.475 492.08 ;
        RECT  0 490.38 705.88 490.52 ;
        RECT  0 489.84 706.475 490.38 ;
        RECT  696.44 489.7 706.475 489.84 ;
        RECT  12.12 489.7 694.44 489.84 ;
        RECT  0.595 489.7 10.12 489.84 ;
        RECT  696.44 489.36 706.475 489.7 ;
        RECT  12.12 489.36 694.44 489.7 ;
        RECT  0 489.36 10.12 489.7 ;
        RECT  0 487.12 706.475 489.36 ;
        RECT  696.44 486.64 706.475 487.12 ;
        RECT  12.12 486.64 694.44 487.12 ;
        RECT  0 486.64 10.12 487.12 ;
        RECT  0 485.08 706.475 486.64 ;
        RECT  0 484.94 705.88 485.08 ;
        RECT  0 484.4 706.475 484.94 ;
        RECT  696.44 484.26 706.475 484.4 ;
        RECT  12.12 484.26 694.44 484.4 ;
        RECT  0.595 484.26 10.12 484.4 ;
        RECT  696.44 483.92 706.475 484.26 ;
        RECT  12.12 483.92 694.44 484.26 ;
        RECT  0 483.92 10.12 484.26 ;
        RECT  0 481.68 706.475 483.92 ;
        RECT  696.44 481.2 706.475 481.68 ;
        RECT  12.12 481.2 694.44 481.68 ;
        RECT  0 481.2 10.12 481.68 ;
        RECT  0 479.64 706.475 481.2 ;
        RECT  0 479.5 705.88 479.64 ;
        RECT  0 478.96 706.475 479.5 ;
        RECT  696.44 478.82 706.475 478.96 ;
        RECT  12.12 478.82 694.44 478.96 ;
        RECT  0.595 478.82 10.12 478.96 ;
        RECT  696.44 478.48 706.475 478.82 ;
        RECT  12.12 478.48 694.44 478.82 ;
        RECT  0 478.48 10.12 478.82 ;
        RECT  0 476.24 706.475 478.48 ;
        RECT  696.44 475.76 706.475 476.24 ;
        RECT  12.12 475.76 694.44 476.24 ;
        RECT  0 475.76 10.12 476.24 ;
        RECT  0 474.2 706.475 475.76 ;
        RECT  0 474.06 705.88 474.2 ;
        RECT  0 473.52 706.475 474.06 ;
        RECT  696.44 473.38 706.475 473.52 ;
        RECT  12.12 473.38 694.44 473.52 ;
        RECT  0.595 473.38 10.12 473.52 ;
        RECT  696.44 473.04 706.475 473.38 ;
        RECT  12.12 473.04 694.44 473.38 ;
        RECT  0 473.04 10.12 473.38 ;
        RECT  0 470.8 706.475 473.04 ;
        RECT  696.44 470.32 706.475 470.8 ;
        RECT  12.12 470.32 694.44 470.8 ;
        RECT  0 470.32 10.12 470.8 ;
        RECT  0 469.44 706.475 470.32 ;
        RECT  0 469.3 705.88 469.44 ;
        RECT  0 468.08 706.475 469.3 ;
        RECT  696.44 467.94 706.475 468.08 ;
        RECT  12.12 467.94 694.44 468.08 ;
        RECT  0.595 467.94 10.12 468.08 ;
        RECT  696.44 467.6 706.475 467.94 ;
        RECT  12.12 467.6 694.44 467.94 ;
        RECT  0 467.6 10.12 467.94 ;
        RECT  0 465.36 706.475 467.6 ;
        RECT  696.44 464.88 706.475 465.36 ;
        RECT  12.12 464.88 694.44 465.36 ;
        RECT  0 464.88 10.12 465.36 ;
        RECT  0 464 706.475 464.88 ;
        RECT  0 463.86 705.88 464 ;
        RECT  0 463.32 706.475 463.86 ;
        RECT  0.595 463.18 706.475 463.32 ;
        RECT  0 462.64 706.475 463.18 ;
        RECT  696.44 462.16 706.475 462.64 ;
        RECT  12.12 462.16 694.44 462.64 ;
        RECT  0 462.16 10.12 462.64 ;
        RECT  0 459.92 706.475 462.16 ;
        RECT  696.44 459.44 706.475 459.92 ;
        RECT  12.12 459.44 694.44 459.92 ;
        RECT  0 459.44 10.12 459.92 ;
        RECT  0 458.56 706.475 459.44 ;
        RECT  0 458.42 705.88 458.56 ;
        RECT  0 457.88 706.475 458.42 ;
        RECT  0.595 457.74 706.475 457.88 ;
        RECT  0 457.2 706.475 457.74 ;
        RECT  696.44 456.72 706.475 457.2 ;
        RECT  12.12 456.72 694.44 457.2 ;
        RECT  0 456.72 10.12 457.2 ;
        RECT  0 454.48 706.475 456.72 ;
        RECT  696.44 454 706.475 454.48 ;
        RECT  12.12 454 694.44 454.48 ;
        RECT  0 454 10.12 454.48 ;
        RECT  0 453.12 706.475 454 ;
        RECT  0 452.98 705.88 453.12 ;
        RECT  0 452.44 706.475 452.98 ;
        RECT  0.595 452.3 706.475 452.44 ;
        RECT  0 451.76 706.475 452.3 ;
        RECT  696.44 451.28 706.475 451.76 ;
        RECT  12.12 451.28 694.44 451.76 ;
        RECT  0 451.28 10.12 451.76 ;
        RECT  0 449.04 706.475 451.28 ;
        RECT  696.44 448.56 706.475 449.04 ;
        RECT  12.12 448.56 694.44 449.04 ;
        RECT  0 448.56 10.12 449.04 ;
        RECT  0 447.68 706.475 448.56 ;
        RECT  0 447.54 705.88 447.68 ;
        RECT  0 447 706.475 447.54 ;
        RECT  0.595 446.86 706.475 447 ;
        RECT  0 446.32 706.475 446.86 ;
        RECT  696.44 445.84 706.475 446.32 ;
        RECT  12.12 445.84 694.44 446.32 ;
        RECT  0 445.84 10.12 446.32 ;
        RECT  0 443.6 706.475 445.84 ;
        RECT  696.44 443.12 706.475 443.6 ;
        RECT  12.12 443.12 694.44 443.6 ;
        RECT  0 443.12 10.12 443.6 ;
        RECT  0 442.24 706.475 443.12 ;
        RECT  0 442.1 705.88 442.24 ;
        RECT  0 441.56 706.475 442.1 ;
        RECT  0.595 441.42 706.475 441.56 ;
        RECT  0 440.88 706.475 441.42 ;
        RECT  696.44 440.4 706.475 440.88 ;
        RECT  12.12 440.4 694.44 440.88 ;
        RECT  0 440.4 10.12 440.88 ;
        RECT  0 438.16 706.475 440.4 ;
        RECT  696.44 437.68 706.475 438.16 ;
        RECT  12.12 437.68 694.44 438.16 ;
        RECT  0 437.68 10.12 438.16 ;
        RECT  0 436.8 706.475 437.68 ;
        RECT  0 436.66 705.88 436.8 ;
        RECT  0 436.12 706.475 436.66 ;
        RECT  0.595 435.98 706.475 436.12 ;
        RECT  0 435.44 706.475 435.98 ;
        RECT  696.44 434.96 706.475 435.44 ;
        RECT  12.12 434.96 694.44 435.44 ;
        RECT  0 434.96 10.12 435.44 ;
        RECT  0 432.72 706.475 434.96 ;
        RECT  696.44 432.24 706.475 432.72 ;
        RECT  12.12 432.24 694.44 432.72 ;
        RECT  0 432.24 10.12 432.72 ;
        RECT  0 431.36 706.475 432.24 ;
        RECT  0 431.22 705.88 431.36 ;
        RECT  0 430.68 706.475 431.22 ;
        RECT  0.595 430.54 706.475 430.68 ;
        RECT  0 430 706.475 430.54 ;
        RECT  696.44 429.52 706.475 430 ;
        RECT  12.12 429.52 694.44 430 ;
        RECT  0 429.52 10.12 430 ;
        RECT  0 427.28 706.475 429.52 ;
        RECT  696.44 426.8 706.475 427.28 ;
        RECT  12.12 426.8 694.44 427.28 ;
        RECT  0 426.8 10.12 427.28 ;
        RECT  0 425.92 706.475 426.8 ;
        RECT  0 425.78 705.88 425.92 ;
        RECT  0 425.24 706.475 425.78 ;
        RECT  0.595 425.1 706.475 425.24 ;
        RECT  0 424.56 706.475 425.1 ;
        RECT  696.44 424.08 706.475 424.56 ;
        RECT  12.12 424.08 694.44 424.56 ;
        RECT  0 424.08 10.12 424.56 ;
        RECT  0 421.84 706.475 424.08 ;
        RECT  696.44 421.36 706.475 421.84 ;
        RECT  12.12 421.36 694.44 421.84 ;
        RECT  0 421.36 10.12 421.84 ;
        RECT  0 420.48 706.475 421.36 ;
        RECT  0 420.34 705.88 420.48 ;
        RECT  0 419.8 706.475 420.34 ;
        RECT  0.595 419.66 706.475 419.8 ;
        RECT  0 419.12 706.475 419.66 ;
        RECT  696.44 418.64 706.475 419.12 ;
        RECT  12.12 418.64 694.44 419.12 ;
        RECT  0 418.64 10.12 419.12 ;
        RECT  0 416.4 706.475 418.64 ;
        RECT  696.44 415.92 706.475 416.4 ;
        RECT  12.12 415.92 694.44 416.4 ;
        RECT  0 415.92 10.12 416.4 ;
        RECT  0 415.04 706.475 415.92 ;
        RECT  0 414.9 705.88 415.04 ;
        RECT  0 414.36 706.475 414.9 ;
        RECT  0.595 414.22 706.475 414.36 ;
        RECT  0 413.68 706.475 414.22 ;
        RECT  696.44 413.2 706.475 413.68 ;
        RECT  12.12 413.2 694.44 413.68 ;
        RECT  0 413.2 10.12 413.68 ;
        RECT  0 410.96 706.475 413.2 ;
        RECT  696.44 410.48 706.475 410.96 ;
        RECT  12.12 410.48 694.44 410.96 ;
        RECT  0 410.48 10.12 410.96 ;
        RECT  0 410.28 706.475 410.48 ;
        RECT  0 410.14 705.88 410.28 ;
        RECT  0 408.92 706.475 410.14 ;
        RECT  0.595 408.78 706.475 408.92 ;
        RECT  0 408.24 706.475 408.78 ;
        RECT  696.44 407.76 706.475 408.24 ;
        RECT  12.12 407.76 694.44 408.24 ;
        RECT  0 407.76 10.12 408.24 ;
        RECT  0 405.52 706.475 407.76 ;
        RECT  696.44 405.04 706.475 405.52 ;
        RECT  12.12 405.04 694.44 405.52 ;
        RECT  0 405.04 10.12 405.52 ;
        RECT  0 404.84 706.475 405.04 ;
        RECT  0 404.7 705.88 404.84 ;
        RECT  0 404.16 706.475 404.7 ;
        RECT  0.595 404.02 706.475 404.16 ;
        RECT  0 402.8 706.475 404.02 ;
        RECT  696.44 402.32 706.475 402.8 ;
        RECT  12.12 402.32 694.44 402.8 ;
        RECT  0 402.32 10.12 402.8 ;
        RECT  0 400.08 706.475 402.32 ;
        RECT  696.44 399.6 706.475 400.08 ;
        RECT  12.12 399.6 694.44 400.08 ;
        RECT  0 399.6 10.12 400.08 ;
        RECT  0 399.4 706.475 399.6 ;
        RECT  0 399.26 705.88 399.4 ;
        RECT  0 398.72 706.475 399.26 ;
        RECT  0.595 398.58 706.475 398.72 ;
        RECT  0 397.36 706.475 398.58 ;
        RECT  696.44 396.88 706.475 397.36 ;
        RECT  12.12 396.88 694.44 397.36 ;
        RECT  0 396.88 10.12 397.36 ;
        RECT  0 394.64 706.475 396.88 ;
        RECT  696.44 394.16 706.475 394.64 ;
        RECT  12.12 394.16 694.44 394.64 ;
        RECT  0 394.16 10.12 394.64 ;
        RECT  0 393.96 706.475 394.16 ;
        RECT  0 393.82 705.88 393.96 ;
        RECT  0 393.28 706.475 393.82 ;
        RECT  0.595 393.14 706.475 393.28 ;
        RECT  0 391.92 706.475 393.14 ;
        RECT  696.44 391.44 706.475 391.92 ;
        RECT  12.12 391.44 694.44 391.92 ;
        RECT  0 391.44 10.12 391.92 ;
        RECT  0 389.2 706.475 391.44 ;
        RECT  696.44 388.72 706.475 389.2 ;
        RECT  12.12 388.72 694.44 389.2 ;
        RECT  0 388.72 10.12 389.2 ;
        RECT  0 388.52 706.475 388.72 ;
        RECT  0 388.38 705.88 388.52 ;
        RECT  0 387.84 706.475 388.38 ;
        RECT  0.595 387.7 706.475 387.84 ;
        RECT  0 386.48 706.475 387.7 ;
        RECT  696.44 386 706.475 386.48 ;
        RECT  12.12 386 694.44 386.48 ;
        RECT  0 386 10.12 386.48 ;
        RECT  0 383.76 706.475 386 ;
        RECT  696.44 383.28 706.475 383.76 ;
        RECT  12.12 383.28 694.44 383.76 ;
        RECT  0 383.28 10.12 383.76 ;
        RECT  0 383.08 706.475 383.28 ;
        RECT  0 382.94 705.88 383.08 ;
        RECT  0 382.4 706.475 382.94 ;
        RECT  0.595 382.26 706.475 382.4 ;
        RECT  0 381.04 706.475 382.26 ;
        RECT  696.44 380.56 706.475 381.04 ;
        RECT  12.12 380.56 694.44 381.04 ;
        RECT  0 380.56 10.12 381.04 ;
        RECT  0 378.32 706.475 380.56 ;
        RECT  696.44 377.84 706.475 378.32 ;
        RECT  12.12 377.84 694.44 378.32 ;
        RECT  0 377.84 10.12 378.32 ;
        RECT  0 377.64 706.475 377.84 ;
        RECT  0 377.5 705.88 377.64 ;
        RECT  0 376.96 706.475 377.5 ;
        RECT  0.595 376.82 706.475 376.96 ;
        RECT  0 375.6 706.475 376.82 ;
        RECT  696.44 375.12 706.475 375.6 ;
        RECT  12.12 375.12 694.44 375.6 ;
        RECT  0 375.12 10.12 375.6 ;
        RECT  0 372.88 706.475 375.12 ;
        RECT  696.44 372.4 706.475 372.88 ;
        RECT  12.12 372.4 694.44 372.88 ;
        RECT  0 372.4 10.12 372.88 ;
        RECT  0 372.2 706.475 372.4 ;
        RECT  0 372.06 705.88 372.2 ;
        RECT  0 371.52 706.475 372.06 ;
        RECT  0.595 371.38 706.475 371.52 ;
        RECT  0 370.16 706.475 371.38 ;
        RECT  696.44 369.68 706.475 370.16 ;
        RECT  12.12 369.68 694.44 370.16 ;
        RECT  0 369.68 10.12 370.16 ;
        RECT  0 367.44 706.475 369.68 ;
        RECT  696.44 366.96 706.475 367.44 ;
        RECT  12.12 366.96 694.44 367.44 ;
        RECT  0 366.96 10.12 367.44 ;
        RECT  0 366.76 706.475 366.96 ;
        RECT  0 366.62 705.88 366.76 ;
        RECT  0 366.08 706.475 366.62 ;
        RECT  0.595 365.94 706.475 366.08 ;
        RECT  0 364.72 706.475 365.94 ;
        RECT  696.44 364.24 706.475 364.72 ;
        RECT  12.12 364.24 694.44 364.72 ;
        RECT  0 364.24 10.12 364.72 ;
        RECT  0 362 706.475 364.24 ;
        RECT  696.44 361.52 706.475 362 ;
        RECT  12.12 361.52 694.44 362 ;
        RECT  0 361.52 10.12 362 ;
        RECT  0 361.32 706.475 361.52 ;
        RECT  0 361.18 705.88 361.32 ;
        RECT  0 360.64 706.475 361.18 ;
        RECT  0.595 360.5 706.475 360.64 ;
        RECT  0 359.28 706.475 360.5 ;
        RECT  696.44 358.8 706.475 359.28 ;
        RECT  12.12 358.8 694.44 359.28 ;
        RECT  0 358.8 10.12 359.28 ;
        RECT  0 356.56 706.475 358.8 ;
        RECT  696.44 356.08 706.475 356.56 ;
        RECT  12.12 356.08 694.44 356.56 ;
        RECT  0 356.08 10.12 356.56 ;
        RECT  0 355.88 706.475 356.08 ;
        RECT  0 355.74 705.88 355.88 ;
        RECT  0 355.2 706.475 355.74 ;
        RECT  0.595 355.06 706.475 355.2 ;
        RECT  0 353.84 706.475 355.06 ;
        RECT  696.44 353.36 706.475 353.84 ;
        RECT  12.12 353.36 694.44 353.84 ;
        RECT  0 353.36 10.12 353.84 ;
        RECT  0 351.12 706.475 353.36 ;
        RECT  696.44 350.98 705.88 351.12 ;
        RECT  12.12 350.98 694.44 351.12 ;
        RECT  0 350.98 10.12 351.12 ;
        RECT  696.44 350.64 706.475 350.98 ;
        RECT  12.12 350.64 694.44 350.98 ;
        RECT  0 350.64 10.12 350.98 ;
        RECT  0 350.44 706.475 350.64 ;
        RECT  0.595 350.3 706.475 350.44 ;
        RECT  0 348.4 706.475 350.3 ;
        RECT  696.44 347.92 706.475 348.4 ;
        RECT  12.12 347.92 694.44 348.4 ;
        RECT  0 347.92 10.12 348.4 ;
        RECT  0 345.68 706.475 347.92 ;
        RECT  696.44 345.54 705.88 345.68 ;
        RECT  12.12 345.54 694.44 345.68 ;
        RECT  0 345.54 10.12 345.68 ;
        RECT  696.44 345.2 706.475 345.54 ;
        RECT  12.12 345.2 694.44 345.54 ;
        RECT  0 345.2 10.12 345.54 ;
        RECT  0 345 706.475 345.2 ;
        RECT  0.595 344.86 706.475 345 ;
        RECT  0 342.96 706.475 344.86 ;
        RECT  696.44 342.48 706.475 342.96 ;
        RECT  12.12 342.48 694.44 342.96 ;
        RECT  0 342.48 10.12 342.96 ;
        RECT  0 340.24 706.475 342.48 ;
        RECT  696.44 340.1 705.88 340.24 ;
        RECT  12.12 340.1 694.44 340.24 ;
        RECT  0 340.1 10.12 340.24 ;
        RECT  696.44 339.76 706.475 340.1 ;
        RECT  12.12 339.76 694.44 340.1 ;
        RECT  0 339.76 10.12 340.1 ;
        RECT  0 339.56 706.475 339.76 ;
        RECT  0.595 339.42 706.475 339.56 ;
        RECT  0 337.52 706.475 339.42 ;
        RECT  696.44 337.04 706.475 337.52 ;
        RECT  12.12 337.04 694.44 337.52 ;
        RECT  0 337.04 10.12 337.52 ;
        RECT  0 334.8 706.475 337.04 ;
        RECT  696.44 334.66 705.88 334.8 ;
        RECT  12.12 334.66 694.44 334.8 ;
        RECT  0 334.66 10.12 334.8 ;
        RECT  696.44 334.32 706.475 334.66 ;
        RECT  12.12 334.32 694.44 334.66 ;
        RECT  0 334.32 10.12 334.66 ;
        RECT  0 334.12 706.475 334.32 ;
        RECT  0.595 333.98 706.475 334.12 ;
        RECT  0 332.08 706.475 333.98 ;
        RECT  696.44 331.6 706.475 332.08 ;
        RECT  12.12 331.6 694.44 332.08 ;
        RECT  0 331.6 10.12 332.08 ;
        RECT  0 329.36 706.475 331.6 ;
        RECT  696.44 329.22 705.88 329.36 ;
        RECT  12.12 329.22 694.44 329.36 ;
        RECT  0 329.22 10.12 329.36 ;
        RECT  696.44 328.88 706.475 329.22 ;
        RECT  12.12 328.88 694.44 329.22 ;
        RECT  0 328.88 10.12 329.22 ;
        RECT  0 328.68 706.475 328.88 ;
        RECT  0.595 328.54 706.475 328.68 ;
        RECT  0 326.64 706.475 328.54 ;
        RECT  696.44 326.16 706.475 326.64 ;
        RECT  12.12 326.16 694.44 326.64 ;
        RECT  0 326.16 10.12 326.64 ;
        RECT  0 323.92 706.475 326.16 ;
        RECT  696.44 323.78 705.88 323.92 ;
        RECT  12.12 323.78 694.44 323.92 ;
        RECT  0 323.78 10.12 323.92 ;
        RECT  696.44 323.44 706.475 323.78 ;
        RECT  12.12 323.44 694.44 323.78 ;
        RECT  0 323.44 10.12 323.78 ;
        RECT  0 323.24 706.475 323.44 ;
        RECT  0.595 323.1 706.475 323.24 ;
        RECT  0 321.2 706.475 323.1 ;
        RECT  696.44 320.72 706.475 321.2 ;
        RECT  12.12 320.72 694.44 321.2 ;
        RECT  0 320.72 10.12 321.2 ;
        RECT  0 318.48 706.475 320.72 ;
        RECT  696.44 318.34 705.88 318.48 ;
        RECT  12.12 318.34 694.44 318.48 ;
        RECT  0 318.34 10.12 318.48 ;
        RECT  696.44 318 706.475 318.34 ;
        RECT  12.12 318 694.44 318.34 ;
        RECT  0 318 10.12 318.34 ;
        RECT  0 317.8 706.475 318 ;
        RECT  0.595 317.66 706.475 317.8 ;
        RECT  0 315.76 706.475 317.66 ;
        RECT  696.44 315.28 706.475 315.76 ;
        RECT  12.12 315.28 694.44 315.76 ;
        RECT  0 315.28 10.12 315.76 ;
        RECT  0 313.04 706.475 315.28 ;
        RECT  696.44 312.9 705.88 313.04 ;
        RECT  12.12 312.9 694.44 313.04 ;
        RECT  0 312.9 10.12 313.04 ;
        RECT  696.44 312.56 706.475 312.9 ;
        RECT  12.12 312.56 694.44 312.9 ;
        RECT  0 312.56 10.12 312.9 ;
        RECT  0 312.36 706.475 312.56 ;
        RECT  0.595 312.22 706.475 312.36 ;
        RECT  0 310.32 706.475 312.22 ;
        RECT  696.44 309.84 706.475 310.32 ;
        RECT  12.12 309.84 694.44 310.32 ;
        RECT  0 309.84 10.12 310.32 ;
        RECT  0 307.6 706.475 309.84 ;
        RECT  696.44 307.46 705.88 307.6 ;
        RECT  12.12 307.46 694.44 307.6 ;
        RECT  0 307.46 10.12 307.6 ;
        RECT  696.44 307.12 706.475 307.46 ;
        RECT  12.12 307.12 694.44 307.46 ;
        RECT  0 307.12 10.12 307.46 ;
        RECT  0 306.92 706.475 307.12 ;
        RECT  0.595 306.78 706.475 306.92 ;
        RECT  0 304.88 706.475 306.78 ;
        RECT  696.44 304.4 706.475 304.88 ;
        RECT  12.12 304.4 694.44 304.88 ;
        RECT  0 304.4 10.12 304.88 ;
        RECT  0 302.16 706.475 304.4 ;
        RECT  696.44 302.02 705.88 302.16 ;
        RECT  12.12 302.02 694.44 302.16 ;
        RECT  0 302.02 10.12 302.16 ;
        RECT  696.44 301.68 706.475 302.02 ;
        RECT  12.12 301.68 694.44 302.02 ;
        RECT  0 301.68 10.12 302.02 ;
        RECT  0 301.48 706.475 301.68 ;
        RECT  0.595 301.34 706.475 301.48 ;
        RECT  0 299.44 706.475 301.34 ;
        RECT  696.44 298.96 706.475 299.44 ;
        RECT  12.12 298.96 694.44 299.44 ;
        RECT  0 298.96 10.12 299.44 ;
        RECT  0 297.4 706.475 298.96 ;
        RECT  0 297.26 705.88 297.4 ;
        RECT  0 296.72 706.475 297.26 ;
        RECT  696.44 296.24 706.475 296.72 ;
        RECT  12.12 296.24 694.44 296.72 ;
        RECT  0 296.24 10.12 296.72 ;
        RECT  0 296.04 706.475 296.24 ;
        RECT  0.595 295.9 706.475 296.04 ;
        RECT  0 294 706.475 295.9 ;
        RECT  696.44 293.52 706.475 294 ;
        RECT  12.12 293.52 694.44 294 ;
        RECT  0 293.52 10.12 294 ;
        RECT  0 291.96 706.475 293.52 ;
        RECT  0 291.82 705.88 291.96 ;
        RECT  0 291.28 706.475 291.82 ;
        RECT  696.44 291.14 706.475 291.28 ;
        RECT  12.12 291.14 694.44 291.28 ;
        RECT  0.595 291.14 10.12 291.28 ;
        RECT  696.44 290.8 706.475 291.14 ;
        RECT  12.12 290.8 694.44 291.14 ;
        RECT  0 290.8 10.12 291.14 ;
        RECT  0 288.56 706.475 290.8 ;
        RECT  696.44 288.08 706.475 288.56 ;
        RECT  12.12 288.08 694.44 288.56 ;
        RECT  0 288.08 10.12 288.56 ;
        RECT  0 286.52 706.475 288.08 ;
        RECT  0 286.38 705.88 286.52 ;
        RECT  0 285.84 706.475 286.38 ;
        RECT  696.44 285.7 706.475 285.84 ;
        RECT  12.12 285.7 694.44 285.84 ;
        RECT  0.595 285.7 10.12 285.84 ;
        RECT  696.44 285.36 706.475 285.7 ;
        RECT  12.12 285.36 694.44 285.7 ;
        RECT  0 285.36 10.12 285.7 ;
        RECT  0 283.12 706.475 285.36 ;
        RECT  696.44 282.64 706.475 283.12 ;
        RECT  12.12 282.64 694.44 283.12 ;
        RECT  0 282.64 10.12 283.12 ;
        RECT  0 281.08 706.475 282.64 ;
        RECT  0 280.94 705.88 281.08 ;
        RECT  0 280.4 706.475 280.94 ;
        RECT  696.44 280.26 706.475 280.4 ;
        RECT  12.12 280.26 694.44 280.4 ;
        RECT  0.595 280.26 10.12 280.4 ;
        RECT  696.44 279.92 706.475 280.26 ;
        RECT  12.12 279.92 694.44 280.26 ;
        RECT  0 279.92 10.12 280.26 ;
        RECT  0 277.68 706.475 279.92 ;
        RECT  696.44 277.2 706.475 277.68 ;
        RECT  12.12 277.2 694.44 277.68 ;
        RECT  0 277.2 10.12 277.68 ;
        RECT  0 275.64 706.475 277.2 ;
        RECT  0 275.5 705.88 275.64 ;
        RECT  0 274.96 706.475 275.5 ;
        RECT  696.44 274.82 706.475 274.96 ;
        RECT  12.12 274.82 694.44 274.96 ;
        RECT  0.595 274.82 10.12 274.96 ;
        RECT  696.44 274.48 706.475 274.82 ;
        RECT  12.12 274.48 694.44 274.82 ;
        RECT  0 274.48 10.12 274.82 ;
        RECT  0 272.24 706.475 274.48 ;
        RECT  696.44 271.76 706.475 272.24 ;
        RECT  12.12 271.76 694.44 272.24 ;
        RECT  0 271.76 10.12 272.24 ;
        RECT  0 270.2 706.475 271.76 ;
        RECT  0 270.06 705.88 270.2 ;
        RECT  0 269.52 706.475 270.06 ;
        RECT  696.44 269.38 706.475 269.52 ;
        RECT  12.12 269.38 694.44 269.52 ;
        RECT  0.595 269.38 10.12 269.52 ;
        RECT  696.44 269.04 706.475 269.38 ;
        RECT  12.12 269.04 694.44 269.38 ;
        RECT  0 269.04 10.12 269.38 ;
        RECT  0 266.8 706.475 269.04 ;
        RECT  696.44 266.32 706.475 266.8 ;
        RECT  12.12 266.32 694.44 266.8 ;
        RECT  0 266.32 10.12 266.8 ;
        RECT  0 264.76 706.475 266.32 ;
        RECT  0 264.62 705.88 264.76 ;
        RECT  0 264.08 706.475 264.62 ;
        RECT  696.44 263.94 706.475 264.08 ;
        RECT  12.12 263.94 694.44 264.08 ;
        RECT  0.595 263.94 10.12 264.08 ;
        RECT  696.44 263.6 706.475 263.94 ;
        RECT  12.12 263.6 694.44 263.94 ;
        RECT  0 263.6 10.12 263.94 ;
        RECT  0 261.36 706.475 263.6 ;
        RECT  696.44 260.88 706.475 261.36 ;
        RECT  12.12 260.88 694.44 261.36 ;
        RECT  0 260.88 10.12 261.36 ;
        RECT  0 259.32 706.475 260.88 ;
        RECT  0 259.18 705.88 259.32 ;
        RECT  0 258.64 706.475 259.18 ;
        RECT  696.44 258.5 706.475 258.64 ;
        RECT  12.12 258.5 694.44 258.64 ;
        RECT  0.595 258.5 10.12 258.64 ;
        RECT  696.44 258.16 706.475 258.5 ;
        RECT  12.12 258.16 694.44 258.5 ;
        RECT  0 258.16 10.12 258.5 ;
        RECT  0 255.92 706.475 258.16 ;
        RECT  696.44 255.44 706.475 255.92 ;
        RECT  12.12 255.44 694.44 255.92 ;
        RECT  0 255.44 10.12 255.92 ;
        RECT  0 253.88 706.475 255.44 ;
        RECT  0 253.74 705.88 253.88 ;
        RECT  0 253.2 706.475 253.74 ;
        RECT  696.44 253.06 706.475 253.2 ;
        RECT  12.12 253.06 694.44 253.2 ;
        RECT  0.595 253.06 10.12 253.2 ;
        RECT  696.44 252.72 706.475 253.06 ;
        RECT  12.12 252.72 694.44 253.06 ;
        RECT  0 252.72 10.12 253.06 ;
        RECT  0 250.48 706.475 252.72 ;
        RECT  696.44 250 706.475 250.48 ;
        RECT  12.12 250 694.44 250.48 ;
        RECT  0 250 10.12 250.48 ;
        RECT  0 248.44 706.475 250 ;
        RECT  0 248.3 705.88 248.44 ;
        RECT  0 247.76 706.475 248.3 ;
        RECT  696.44 247.62 706.475 247.76 ;
        RECT  12.12 247.62 694.44 247.76 ;
        RECT  0.595 247.62 10.12 247.76 ;
        RECT  696.44 247.28 706.475 247.62 ;
        RECT  12.12 247.28 694.44 247.62 ;
        RECT  0 247.28 10.12 247.62 ;
        RECT  0 245.04 706.475 247.28 ;
        RECT  696.44 244.56 706.475 245.04 ;
        RECT  12.12 244.56 694.44 245.04 ;
        RECT  0 244.56 10.12 245.04 ;
        RECT  0 243 706.475 244.56 ;
        RECT  0 242.86 705.88 243 ;
        RECT  0 242.32 706.475 242.86 ;
        RECT  696.44 242.18 706.475 242.32 ;
        RECT  12.12 242.18 694.44 242.32 ;
        RECT  0.595 242.18 10.12 242.32 ;
        RECT  696.44 241.84 706.475 242.18 ;
        RECT  12.12 241.84 694.44 242.18 ;
        RECT  0 241.84 10.12 242.18 ;
        RECT  0 239.6 706.475 241.84 ;
        RECT  696.44 239.12 706.475 239.6 ;
        RECT  12.12 239.12 694.44 239.6 ;
        RECT  0 239.12 10.12 239.6 ;
        RECT  0 238.24 706.475 239.12 ;
        RECT  0 238.1 705.88 238.24 ;
        RECT  0 236.88 706.475 238.1 ;
        RECT  696.44 236.74 706.475 236.88 ;
        RECT  12.12 236.74 694.44 236.88 ;
        RECT  0.595 236.74 10.12 236.88 ;
        RECT  696.44 236.4 706.475 236.74 ;
        RECT  12.12 236.4 694.44 236.74 ;
        RECT  0 236.4 10.12 236.74 ;
        RECT  0 234.16 706.475 236.4 ;
        RECT  696.44 233.68 706.475 234.16 ;
        RECT  12.12 233.68 694.44 234.16 ;
        RECT  0 233.68 10.12 234.16 ;
        RECT  0 232.8 706.475 233.68 ;
        RECT  0 232.66 705.88 232.8 ;
        RECT  0 232.12 706.475 232.66 ;
        RECT  0.595 231.98 706.475 232.12 ;
        RECT  0 231.44 706.475 231.98 ;
        RECT  696.44 230.96 706.475 231.44 ;
        RECT  12.12 230.96 694.44 231.44 ;
        RECT  0 230.96 10.12 231.44 ;
        RECT  0 228.72 706.475 230.96 ;
        RECT  696.44 228.24 706.475 228.72 ;
        RECT  12.12 228.24 694.44 228.72 ;
        RECT  0 228.24 10.12 228.72 ;
        RECT  0 227.36 706.475 228.24 ;
        RECT  0 227.22 705.88 227.36 ;
        RECT  0 226.68 706.475 227.22 ;
        RECT  0.595 226.54 706.475 226.68 ;
        RECT  0 226 706.475 226.54 ;
        RECT  696.44 225.52 706.475 226 ;
        RECT  12.12 225.52 694.44 226 ;
        RECT  0 225.52 10.12 226 ;
        RECT  0 223.28 706.475 225.52 ;
        RECT  696.44 222.8 706.475 223.28 ;
        RECT  12.12 222.8 694.44 223.28 ;
        RECT  0 222.8 10.12 223.28 ;
        RECT  0 221.92 706.475 222.8 ;
        RECT  0 221.78 705.88 221.92 ;
        RECT  0 221.24 706.475 221.78 ;
        RECT  0.595 221.1 706.475 221.24 ;
        RECT  0 220.56 706.475 221.1 ;
        RECT  696.44 220.08 706.475 220.56 ;
        RECT  12.12 220.08 694.44 220.56 ;
        RECT  0 220.08 10.12 220.56 ;
        RECT  0 217.84 706.475 220.08 ;
        RECT  696.44 217.36 706.475 217.84 ;
        RECT  12.12 217.36 694.44 217.84 ;
        RECT  0 217.36 10.12 217.84 ;
        RECT  0 216.48 706.475 217.36 ;
        RECT  0 216.34 705.88 216.48 ;
        RECT  0 215.8 706.475 216.34 ;
        RECT  0.595 215.66 706.475 215.8 ;
        RECT  0 215.12 706.475 215.66 ;
        RECT  696.44 214.64 706.475 215.12 ;
        RECT  12.12 214.64 694.44 215.12 ;
        RECT  0 214.64 10.12 215.12 ;
        RECT  0 212.4 706.475 214.64 ;
        RECT  696.44 211.92 706.475 212.4 ;
        RECT  12.12 211.92 694.44 212.4 ;
        RECT  0 211.92 10.12 212.4 ;
        RECT  0 211.04 706.475 211.92 ;
        RECT  0 210.9 705.88 211.04 ;
        RECT  0 210.36 706.475 210.9 ;
        RECT  0.595 210.22 706.475 210.36 ;
        RECT  0 209.68 706.475 210.22 ;
        RECT  696.44 209.2 706.475 209.68 ;
        RECT  12.12 209.2 694.44 209.68 ;
        RECT  0 209.2 10.12 209.68 ;
        RECT  0 206.96 706.475 209.2 ;
        RECT  696.44 206.48 706.475 206.96 ;
        RECT  12.12 206.48 694.44 206.96 ;
        RECT  0 206.48 10.12 206.96 ;
        RECT  0 205.6 706.475 206.48 ;
        RECT  0 205.46 705.88 205.6 ;
        RECT  0 204.92 706.475 205.46 ;
        RECT  0.595 204.78 706.475 204.92 ;
        RECT  0 204.24 706.475 204.78 ;
        RECT  696.44 203.76 706.475 204.24 ;
        RECT  12.12 203.76 694.44 204.24 ;
        RECT  0 203.76 10.12 204.24 ;
        RECT  0 201.52 706.475 203.76 ;
        RECT  696.44 201.04 706.475 201.52 ;
        RECT  12.12 201.04 694.44 201.52 ;
        RECT  0 201.04 10.12 201.52 ;
        RECT  0 200.16 706.475 201.04 ;
        RECT  0 200.02 705.88 200.16 ;
        RECT  0 199.48 706.475 200.02 ;
        RECT  0.595 199.34 706.475 199.48 ;
        RECT  0 198.8 706.475 199.34 ;
        RECT  696.44 198.32 706.475 198.8 ;
        RECT  12.12 198.32 694.44 198.8 ;
        RECT  0 198.32 10.12 198.8 ;
        RECT  0 196.08 706.475 198.32 ;
        RECT  696.44 195.6 706.475 196.08 ;
        RECT  12.12 195.6 694.44 196.08 ;
        RECT  0 195.6 10.12 196.08 ;
        RECT  0 194.72 706.475 195.6 ;
        RECT  0 194.58 705.88 194.72 ;
        RECT  0 194.04 706.475 194.58 ;
        RECT  0.595 193.9 706.475 194.04 ;
        RECT  0 193.36 706.475 193.9 ;
        RECT  696.44 192.88 706.475 193.36 ;
        RECT  12.12 192.88 694.44 193.36 ;
        RECT  0 192.88 10.12 193.36 ;
        RECT  0 190.64 706.475 192.88 ;
        RECT  696.44 190.16 706.475 190.64 ;
        RECT  12.12 190.16 694.44 190.64 ;
        RECT  0 190.16 10.12 190.64 ;
        RECT  0 189.28 706.475 190.16 ;
        RECT  0 189.14 705.88 189.28 ;
        RECT  0 188.6 706.475 189.14 ;
        RECT  0.595 188.46 706.475 188.6 ;
        RECT  0 187.92 706.475 188.46 ;
        RECT  696.44 187.44 706.475 187.92 ;
        RECT  12.12 187.44 694.44 187.92 ;
        RECT  0 187.44 10.12 187.92 ;
        RECT  0 185.2 706.475 187.44 ;
        RECT  696.44 184.72 706.475 185.2 ;
        RECT  12.12 184.72 694.44 185.2 ;
        RECT  0 184.72 10.12 185.2 ;
        RECT  0 183.84 706.475 184.72 ;
        RECT  0 183.7 705.88 183.84 ;
        RECT  0 183.16 706.475 183.7 ;
        RECT  0.595 183.02 706.475 183.16 ;
        RECT  0 182.48 706.475 183.02 ;
        RECT  696.44 182 706.475 182.48 ;
        RECT  12.12 182 694.44 182.48 ;
        RECT  0 182 10.12 182.48 ;
        RECT  0 179.76 706.475 182 ;
        RECT  696.44 179.28 706.475 179.76 ;
        RECT  12.12 179.28 694.44 179.76 ;
        RECT  0 179.28 10.12 179.76 ;
        RECT  0 179.08 706.475 179.28 ;
        RECT  0 178.94 705.88 179.08 ;
        RECT  0 177.72 706.475 178.94 ;
        RECT  0.595 177.58 706.475 177.72 ;
        RECT  0 177.04 706.475 177.58 ;
        RECT  696.44 176.56 706.475 177.04 ;
        RECT  12.12 176.56 694.44 177.04 ;
        RECT  0 176.56 10.12 177.04 ;
        RECT  0 174.32 706.475 176.56 ;
        RECT  696.44 173.84 706.475 174.32 ;
        RECT  12.12 173.84 694.44 174.32 ;
        RECT  0 173.84 10.12 174.32 ;
        RECT  0 173.64 706.475 173.84 ;
        RECT  0 173.5 705.88 173.64 ;
        RECT  0 172.96 706.475 173.5 ;
        RECT  0.595 172.82 706.475 172.96 ;
        RECT  0 171.6 706.475 172.82 ;
        RECT  696.44 171.12 706.475 171.6 ;
        RECT  12.12 171.12 694.44 171.6 ;
        RECT  0 171.12 10.12 171.6 ;
        RECT  0 168.88 706.475 171.12 ;
        RECT  696.44 168.4 706.475 168.88 ;
        RECT  12.12 168.4 694.44 168.88 ;
        RECT  0 168.4 10.12 168.88 ;
        RECT  0 168.2 706.475 168.4 ;
        RECT  0 168.06 705.88 168.2 ;
        RECT  0 167.52 706.475 168.06 ;
        RECT  0.595 167.38 706.475 167.52 ;
        RECT  0 166.16 706.475 167.38 ;
        RECT  696.44 165.68 706.475 166.16 ;
        RECT  12.12 165.68 694.44 166.16 ;
        RECT  0 165.68 10.12 166.16 ;
        RECT  0 163.44 706.475 165.68 ;
        RECT  696.44 162.96 706.475 163.44 ;
        RECT  12.12 162.96 694.44 163.44 ;
        RECT  0 162.96 10.12 163.44 ;
        RECT  0 162.76 706.475 162.96 ;
        RECT  0 162.62 705.88 162.76 ;
        RECT  0 162.08 706.475 162.62 ;
        RECT  0.595 161.94 706.475 162.08 ;
        RECT  0 160.72 706.475 161.94 ;
        RECT  696.44 160.24 706.475 160.72 ;
        RECT  12.12 160.24 694.44 160.72 ;
        RECT  0 160.24 10.12 160.72 ;
        RECT  0 158 706.475 160.24 ;
        RECT  696.44 157.52 706.475 158 ;
        RECT  12.12 157.52 694.44 158 ;
        RECT  0 157.52 10.12 158 ;
        RECT  0 157.32 706.475 157.52 ;
        RECT  0 157.18 705.88 157.32 ;
        RECT  0 156.64 706.475 157.18 ;
        RECT  0.595 156.5 706.475 156.64 ;
        RECT  0 155.28 706.475 156.5 ;
        RECT  696.44 154.8 706.475 155.28 ;
        RECT  12.12 154.8 694.44 155.28 ;
        RECT  0 154.8 10.12 155.28 ;
        RECT  0 152.56 706.475 154.8 ;
        RECT  696.44 152.08 706.475 152.56 ;
        RECT  12.12 152.08 694.44 152.56 ;
        RECT  0 152.08 10.12 152.56 ;
        RECT  0 151.88 706.475 152.08 ;
        RECT  0 151.74 705.88 151.88 ;
        RECT  0 151.2 706.475 151.74 ;
        RECT  0.595 151.06 706.475 151.2 ;
        RECT  0 149.84 706.475 151.06 ;
        RECT  696.44 149.36 706.475 149.84 ;
        RECT  12.12 149.36 694.44 149.84 ;
        RECT  0 149.36 10.12 149.84 ;
        RECT  0 147.12 706.475 149.36 ;
        RECT  696.44 146.64 706.475 147.12 ;
        RECT  12.12 146.64 694.44 147.12 ;
        RECT  0 146.64 10.12 147.12 ;
        RECT  0 146.44 706.475 146.64 ;
        RECT  0 146.3 705.88 146.44 ;
        RECT  0 145.76 706.475 146.3 ;
        RECT  0.595 145.62 706.475 145.76 ;
        RECT  0 144.4 706.475 145.62 ;
        RECT  696.44 143.92 706.475 144.4 ;
        RECT  12.12 143.92 694.44 144.4 ;
        RECT  0 143.92 10.12 144.4 ;
        RECT  0 141.68 706.475 143.92 ;
        RECT  696.44 141.2 706.475 141.68 ;
        RECT  12.12 141.2 694.44 141.68 ;
        RECT  0 141.2 10.12 141.68 ;
        RECT  0 141 706.475 141.2 ;
        RECT  0 140.86 705.88 141 ;
        RECT  0 140.32 706.475 140.86 ;
        RECT  0.595 140.18 706.475 140.32 ;
        RECT  0 138.96 706.475 140.18 ;
        RECT  696.44 138.48 706.475 138.96 ;
        RECT  12.12 138.48 694.44 138.96 ;
        RECT  0 138.48 10.12 138.96 ;
        RECT  0 136.24 706.475 138.48 ;
        RECT  696.44 135.76 706.475 136.24 ;
        RECT  12.12 135.76 694.44 136.24 ;
        RECT  0 135.76 10.12 136.24 ;
        RECT  0 135.56 706.475 135.76 ;
        RECT  0 135.42 705.88 135.56 ;
        RECT  0 134.88 706.475 135.42 ;
        RECT  0.595 134.74 706.475 134.88 ;
        RECT  0 133.52 706.475 134.74 ;
        RECT  696.44 133.04 706.475 133.52 ;
        RECT  12.12 133.04 694.44 133.52 ;
        RECT  0 133.04 10.12 133.52 ;
        RECT  0 130.8 706.475 133.04 ;
        RECT  696.44 130.32 706.475 130.8 ;
        RECT  12.12 130.32 694.44 130.8 ;
        RECT  0 130.32 10.12 130.8 ;
        RECT  0 130.12 706.475 130.32 ;
        RECT  0 129.98 705.88 130.12 ;
        RECT  0 129.44 706.475 129.98 ;
        RECT  0.595 129.3 706.475 129.44 ;
        RECT  0 128.08 706.475 129.3 ;
        RECT  696.44 127.6 706.475 128.08 ;
        RECT  12.12 127.6 694.44 128.08 ;
        RECT  0 127.6 10.12 128.08 ;
        RECT  0 125.36 706.475 127.6 ;
        RECT  696.44 124.88 706.475 125.36 ;
        RECT  12.12 124.88 694.44 125.36 ;
        RECT  0 124.88 10.12 125.36 ;
        RECT  0 124.68 706.475 124.88 ;
        RECT  0 124.54 705.88 124.68 ;
        RECT  0 124 706.475 124.54 ;
        RECT  0.595 123.86 706.475 124 ;
        RECT  0 122.64 706.475 123.86 ;
        RECT  696.44 122.16 706.475 122.64 ;
        RECT  12.12 122.16 694.44 122.64 ;
        RECT  0 122.16 10.12 122.64 ;
        RECT  0 119.92 706.475 122.16 ;
        RECT  696.44 119.78 705.88 119.92 ;
        RECT  12.12 119.78 694.44 119.92 ;
        RECT  0 119.78 10.12 119.92 ;
        RECT  696.44 119.44 706.475 119.78 ;
        RECT  12.12 119.44 694.44 119.78 ;
        RECT  0 119.44 10.12 119.78 ;
        RECT  0 118.56 706.475 119.44 ;
        RECT  0.595 118.42 706.475 118.56 ;
        RECT  0 117.2 706.475 118.42 ;
        RECT  696.44 116.72 706.475 117.2 ;
        RECT  12.12 116.72 694.44 117.2 ;
        RECT  0 116.72 10.12 117.2 ;
        RECT  0 114.48 706.475 116.72 ;
        RECT  696.44 114.34 705.88 114.48 ;
        RECT  12.12 114.34 694.44 114.48 ;
        RECT  0 114.34 10.12 114.48 ;
        RECT  696.44 114 706.475 114.34 ;
        RECT  12.12 114 694.44 114.34 ;
        RECT  0 114 10.12 114.34 ;
        RECT  0 113.8 706.475 114 ;
        RECT  0.595 113.66 706.475 113.8 ;
        RECT  0 111.76 706.475 113.66 ;
        RECT  696.44 111.28 706.475 111.76 ;
        RECT  12.12 111.28 694.44 111.76 ;
        RECT  0 111.28 10.12 111.76 ;
        RECT  0 109.04 706.475 111.28 ;
        RECT  696.44 108.9 705.88 109.04 ;
        RECT  12.12 108.9 694.44 109.04 ;
        RECT  0 108.9 10.12 109.04 ;
        RECT  696.44 108.56 706.475 108.9 ;
        RECT  12.12 108.56 694.44 108.9 ;
        RECT  0 108.56 10.12 108.9 ;
        RECT  0 108.36 706.475 108.56 ;
        RECT  0.595 108.22 706.475 108.36 ;
        RECT  0 106.32 706.475 108.22 ;
        RECT  696.44 105.84 706.475 106.32 ;
        RECT  12.12 105.84 694.44 106.32 ;
        RECT  0 105.84 10.12 106.32 ;
        RECT  0 103.6 706.475 105.84 ;
        RECT  696.44 103.46 705.88 103.6 ;
        RECT  12.12 103.46 694.44 103.6 ;
        RECT  0 103.46 10.12 103.6 ;
        RECT  696.44 103.12 706.475 103.46 ;
        RECT  12.12 103.12 694.44 103.46 ;
        RECT  0 103.12 10.12 103.46 ;
        RECT  0 102.92 706.475 103.12 ;
        RECT  0.595 102.78 706.475 102.92 ;
        RECT  0 100.88 706.475 102.78 ;
        RECT  696.44 100.4 706.475 100.88 ;
        RECT  12.12 100.4 694.44 100.88 ;
        RECT  0 100.4 10.12 100.88 ;
        RECT  0 98.16 706.475 100.4 ;
        RECT  696.44 98.02 705.88 98.16 ;
        RECT  12.12 98.02 694.44 98.16 ;
        RECT  0 98.02 10.12 98.16 ;
        RECT  696.44 97.68 706.475 98.02 ;
        RECT  12.12 97.68 694.44 98.02 ;
        RECT  0 97.68 10.12 98.02 ;
        RECT  0 97.48 706.475 97.68 ;
        RECT  0.595 97.34 706.475 97.48 ;
        RECT  0 95.44 706.475 97.34 ;
        RECT  696.44 94.96 706.475 95.44 ;
        RECT  12.12 94.96 694.44 95.44 ;
        RECT  0 94.96 10.12 95.44 ;
        RECT  0 92.72 706.475 94.96 ;
        RECT  696.44 92.58 705.88 92.72 ;
        RECT  12.12 92.58 694.44 92.72 ;
        RECT  0 92.58 10.12 92.72 ;
        RECT  696.44 92.24 706.475 92.58 ;
        RECT  12.12 92.24 694.44 92.58 ;
        RECT  0 92.24 10.12 92.58 ;
        RECT  0 92.04 706.475 92.24 ;
        RECT  0.595 91.9 706.475 92.04 ;
        RECT  0 90 706.475 91.9 ;
        RECT  696.44 89.52 706.475 90 ;
        RECT  12.12 89.52 694.44 90 ;
        RECT  0 89.52 10.12 90 ;
        RECT  0 87.28 706.475 89.52 ;
        RECT  696.44 87.14 705.88 87.28 ;
        RECT  12.12 87.14 694.44 87.28 ;
        RECT  0 87.14 10.12 87.28 ;
        RECT  696.44 86.8 706.475 87.14 ;
        RECT  12.12 86.8 694.44 87.14 ;
        RECT  0 86.8 10.12 87.14 ;
        RECT  0 86.6 706.475 86.8 ;
        RECT  0.595 86.46 706.475 86.6 ;
        RECT  0 84.56 706.475 86.46 ;
        RECT  696.44 84.08 706.475 84.56 ;
        RECT  12.12 84.08 694.44 84.56 ;
        RECT  0 84.08 10.12 84.56 ;
        RECT  0 81.84 706.475 84.08 ;
        RECT  696.44 81.7 705.88 81.84 ;
        RECT  12.12 81.7 694.44 81.84 ;
        RECT  0 81.7 10.12 81.84 ;
        RECT  696.44 81.36 706.475 81.7 ;
        RECT  12.12 81.36 694.44 81.7 ;
        RECT  0 81.36 10.12 81.7 ;
        RECT  0 81.16 706.475 81.36 ;
        RECT  0.595 81.02 706.475 81.16 ;
        RECT  0 79.12 706.475 81.02 ;
        RECT  696.44 78.64 706.475 79.12 ;
        RECT  12.12 78.64 694.44 79.12 ;
        RECT  0 78.64 10.12 79.12 ;
        RECT  0 76.4 706.475 78.64 ;
        RECT  696.44 76.26 705.88 76.4 ;
        RECT  12.12 76.26 694.44 76.4 ;
        RECT  0 76.26 10.12 76.4 ;
        RECT  696.44 75.92 706.475 76.26 ;
        RECT  12.12 75.92 694.44 76.26 ;
        RECT  0 75.92 10.12 76.26 ;
        RECT  0 75.72 706.475 75.92 ;
        RECT  0.595 75.58 706.475 75.72 ;
        RECT  0 73.68 706.475 75.58 ;
        RECT  696.44 73.2 706.475 73.68 ;
        RECT  12.12 73.2 694.44 73.68 ;
        RECT  0 73.2 10.12 73.68 ;
        RECT  0 70.96 706.475 73.2 ;
        RECT  696.44 70.82 705.88 70.96 ;
        RECT  12.12 70.82 694.44 70.96 ;
        RECT  0 70.82 10.12 70.96 ;
        RECT  696.44 70.48 706.475 70.82 ;
        RECT  12.12 70.48 694.44 70.82 ;
        RECT  0 70.48 10.12 70.82 ;
        RECT  0 70.28 706.475 70.48 ;
        RECT  0.595 70.14 706.475 70.28 ;
        RECT  0 68.24 706.475 70.14 ;
        RECT  696.44 67.76 706.475 68.24 ;
        RECT  12.12 67.76 694.44 68.24 ;
        RECT  0 67.76 10.12 68.24 ;
        RECT  0 65.52 706.475 67.76 ;
        RECT  696.44 65.38 705.88 65.52 ;
        RECT  12.12 65.38 694.44 65.52 ;
        RECT  0 65.38 10.12 65.52 ;
        RECT  696.44 65.04 706.475 65.38 ;
        RECT  12.12 65.04 694.44 65.38 ;
        RECT  0 65.04 10.12 65.38 ;
        RECT  0 64.84 706.475 65.04 ;
        RECT  0.595 64.7 706.475 64.84 ;
        RECT  0 62.8 706.475 64.7 ;
        RECT  696.44 62.32 706.475 62.8 ;
        RECT  12.12 62.32 694.44 62.8 ;
        RECT  0 62.32 10.12 62.8 ;
        RECT  0 60.76 706.475 62.32 ;
        RECT  0 60.62 705.88 60.76 ;
        RECT  0 60.08 706.475 60.62 ;
        RECT  696.44 59.6 706.475 60.08 ;
        RECT  12.12 59.6 694.44 60.08 ;
        RECT  0 59.6 10.12 60.08 ;
        RECT  0 59.4 706.475 59.6 ;
        RECT  0.595 59.26 706.475 59.4 ;
        RECT  0 57.36 706.475 59.26 ;
        RECT  696.44 56.88 706.475 57.36 ;
        RECT  12.12 56.88 694.44 57.36 ;
        RECT  0 56.88 10.12 57.36 ;
        RECT  0 55.32 706.475 56.88 ;
        RECT  0 55.18 705.88 55.32 ;
        RECT  0 54.64 706.475 55.18 ;
        RECT  696.44 54.5 706.475 54.64 ;
        RECT  12.12 54.5 694.44 54.64 ;
        RECT  0.595 54.5 10.12 54.64 ;
        RECT  696.44 54.16 706.475 54.5 ;
        RECT  12.12 54.16 694.44 54.5 ;
        RECT  0 54.16 10.12 54.5 ;
        RECT  0 51.92 706.475 54.16 ;
        RECT  696.44 51.44 706.475 51.92 ;
        RECT  12.12 51.44 694.44 51.92 ;
        RECT  0 51.44 10.12 51.92 ;
        RECT  0 49.88 706.475 51.44 ;
        RECT  0 49.74 705.88 49.88 ;
        RECT  0 49.2 706.475 49.74 ;
        RECT  696.44 49.06 706.475 49.2 ;
        RECT  12.12 49.06 694.44 49.2 ;
        RECT  0.595 49.06 10.12 49.2 ;
        RECT  696.44 48.72 706.475 49.06 ;
        RECT  12.12 48.72 694.44 49.06 ;
        RECT  0 48.72 10.12 49.06 ;
        RECT  0 46.48 706.475 48.72 ;
        RECT  696.44 46 706.475 46.48 ;
        RECT  12.12 46 694.44 46.48 ;
        RECT  0 46 10.12 46.48 ;
        RECT  0 44.44 706.475 46 ;
        RECT  0 44.3 705.88 44.44 ;
        RECT  0 43.76 706.475 44.3 ;
        RECT  696.44 43.62 706.475 43.76 ;
        RECT  12.12 43.62 694.44 43.76 ;
        RECT  0.595 43.62 10.12 43.76 ;
        RECT  696.44 43.28 706.475 43.62 ;
        RECT  12.12 43.28 694.44 43.62 ;
        RECT  0 43.28 10.12 43.62 ;
        RECT  0 41.04 706.475 43.28 ;
        RECT  696.44 40.56 706.475 41.04 ;
        RECT  12.12 40.56 694.44 41.04 ;
        RECT  0 40.56 10.12 41.04 ;
        RECT  0 39 706.475 40.56 ;
        RECT  0 38.86 705.88 39 ;
        RECT  0 38.32 706.475 38.86 ;
        RECT  696.44 38.18 706.475 38.32 ;
        RECT  12.12 38.18 694.44 38.32 ;
        RECT  0.595 38.18 10.12 38.32 ;
        RECT  696.44 37.84 706.475 38.18 ;
        RECT  12.12 37.84 694.44 38.18 ;
        RECT  0 37.84 10.12 38.18 ;
        RECT  0 35.6 706.475 37.84 ;
        RECT  696.44 35.12 706.475 35.6 ;
        RECT  12.12 35.12 694.44 35.6 ;
        RECT  0 35.12 10.12 35.6 ;
        RECT  0 33.56 706.475 35.12 ;
        RECT  0 33.42 705.88 33.56 ;
        RECT  0 32.88 706.475 33.42 ;
        RECT  696.44 32.74 706.475 32.88 ;
        RECT  12.12 32.74 694.44 32.88 ;
        RECT  0.595 32.74 10.12 32.88 ;
        RECT  696.44 32.4 706.475 32.74 ;
        RECT  12.12 32.4 694.44 32.74 ;
        RECT  0 32.4 10.12 32.74 ;
        RECT  0 30.16 706.475 32.4 ;
        RECT  696.44 29.68 706.475 30.16 ;
        RECT  12.12 29.68 694.44 30.16 ;
        RECT  0 29.68 10.12 30.16 ;
        RECT  0 28.12 706.475 29.68 ;
        RECT  0 27.98 705.88 28.12 ;
        RECT  0 27.44 706.475 27.98 ;
        RECT  696.44 27.3 706.475 27.44 ;
        RECT  12.12 27.3 694.44 27.44 ;
        RECT  0.595 27.3 10.12 27.44 ;
        RECT  696.44 26.96 706.475 27.3 ;
        RECT  12.12 26.96 694.44 27.3 ;
        RECT  0 26.96 10.12 27.3 ;
        RECT  0 24.72 706.475 26.96 ;
        RECT  696.44 24.24 706.475 24.72 ;
        RECT  12.12 24.24 694.44 24.72 ;
        RECT  0 24.24 10.12 24.72 ;
        RECT  0 22.68 706.475 24.24 ;
        RECT  0 22.54 705.88 22.68 ;
        RECT  0 22 706.475 22.54 ;
        RECT  696.44 21.86 706.475 22 ;
        RECT  12.12 21.86 694.44 22 ;
        RECT  0.595 21.86 10.12 22 ;
        RECT  696.44 21.52 706.475 21.86 ;
        RECT  12.12 21.52 694.44 21.86 ;
        RECT  0 21.52 10.12 21.86 ;
        RECT  0 19.28 706.475 21.52 ;
        RECT  696.44 18.8 706.475 19.28 ;
        RECT  12.12 18.8 694.44 19.28 ;
        RECT  0 18.8 10.12 19.28 ;
        RECT  0 17.24 706.475 18.8 ;
        RECT  0 17.1 705.88 17.24 ;
        RECT  0 16.56 706.475 17.1 ;
        RECT  696.44 16.42 706.475 16.56 ;
        RECT  12.12 16.42 694.44 16.56 ;
        RECT  0.595 16.42 10.12 16.56 ;
        RECT  696.44 16.08 706.475 16.42 ;
        RECT  12.12 16.08 694.44 16.42 ;
        RECT  0 16.08 10.12 16.42 ;
        RECT  0 13.84 706.475 16.08 ;
        RECT  696.44 13.36 706.475 13.84 ;
        RECT  12.12 13.36 694.44 13.84 ;
        RECT  0 13.36 10.12 13.84 ;
        RECT  0 11.8 706.475 13.36 ;
        RECT  0 11.66 705.88 11.8 ;
        RECT  0 11.12 706.475 11.66 ;
        RECT  696.44 10.98 706.475 11.12 ;
        RECT  0.595 10.98 10.12 11.12 ;
        RECT  696.44 10.64 706.475 10.98 ;
        RECT  0 10.64 10.12 10.98 ;
        RECT  0 6.36 706.475 10.64 ;
        RECT  0 6.22 705.88 6.36 ;
        RECT  0 5.68 706.475 6.22 ;
        RECT  0.595 5.54 706.475 5.68 ;
        RECT  0 1.6 706.475 5.54 ;
        RECT  0 1.46 705.88 1.6 ;
        RECT  0 0 706.475 1.46 ;
      LAYER li1 ;
        RECT  0 0 706.475 706.475 ;
    END
END ember_cp
END LIBRARY
